VERSION 5.7 ;
  NOWIREEXTENSIONATPIN ON ;
  DIVIDERCHAR "/" ;
  BUSBITCHARS "[]" ;
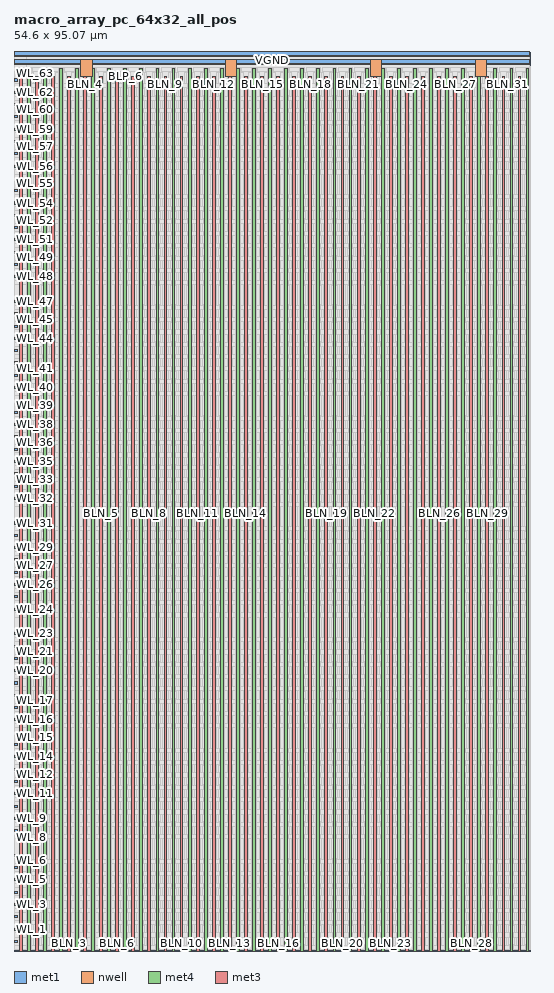
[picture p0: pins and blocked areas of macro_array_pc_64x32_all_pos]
MACRO macro_array_pc_64x32_all_pos
  CLASS BLOCK ;
  FOREIGN macro_array_pc_64x32_all_pos ;
  ORIGIN 0.000 0.000 ;
  SIZE 54.600 BY 95.070 ;
  PIN VPWR
    USE POWER ;
    PORT
      LAYER met1 ;
        RECT 0.000 93.750 54.500 94.150 ;
    END
    PORT
      LAYER nwell ;
        RECT 7.050 92.400 8.250 94.120 ;
    END
    PORT
      LAYER nwell ;
        RECT 22.350 92.400 23.550 94.120 ;
    END
    PORT
      LAYER nwell ;
        RECT 37.650 92.400 38.850 94.120 ;
    END
    PORT
      LAYER nwell ;
        RECT 48.700 92.400 49.900 94.120 ;
    END
    PORT
      LAYER met4 ;
        RECT 0.000 93.680 54.500 94.220 ;
    END
  END VPWR
  PIN VGND
    USE GROUND ;
    PORT
      LAYER met1 ;
        RECT 0.000 94.600 54.500 95.000 ;
    END
    PORT
      LAYER met4 ;
        RECT 0.000 94.530 54.500 95.070 ;
    END
  END VGND
  PIN BLP_0
    ANTENNADIFFAREA 253.343994 ;
    PORT
      LAYER met4 ;
        RECT 1.400 0.000 1.700 93.250 ;
    END
  END BLP_0
  PIN BLN_0
    PORT
      LAYER met3 ;
        RECT 0.550 0.000 0.850 92.400 ;
    END
  END BLN_0
  PIN BLP_1
    ANTENNADIFFAREA 253.222198 ;
    PORT
      LAYER met4 ;
        RECT 3.100 0.000 3.400 93.250 ;
    END
  END BLP_1
  PIN BLN_1
    PORT
      LAYER met3 ;
        RECT 2.250 0.000 2.550 92.400 ;
    END
  END BLN_1
  PIN BLP_2
    ANTENNADIFFAREA 253.100388 ;
    PORT
      LAYER met4 ;
        RECT 4.800 0.000 5.100 93.250 ;
    END
  END BLP_2
  PIN BLN_2
    PORT
      LAYER met3 ;
        RECT 3.950 0.000 4.250 92.400 ;
    END
  END BLN_2
  PIN BLP_3
    ANTENNADIFFAREA 252.978592 ;
    PORT
      LAYER met4 ;
        RECT 6.500 0.000 6.800 93.250 ;
    END
  END BLP_3
  PIN BLN_3
    PORT
      LAYER met3 ;
        RECT 5.650 0.000 5.950 92.400 ;
    END
  END BLN_3
  PIN BLP_4
    ANTENNADIFFAREA 252.856796 ;
    PORT
      LAYER met4 ;
        RECT 8.200 0.000 8.500 93.250 ;
    END
  END BLP_4
  PIN BLN_4
    PORT
      LAYER met3 ;
        RECT 7.350 0.000 7.650 92.400 ;
    END
  END BLN_4
  PIN BLP_5
    ANTENNADIFFAREA 252.735001 ;
    PORT
      LAYER met4 ;
        RECT 9.900 0.000 10.200 93.250 ;
    END
  END BLP_5
  PIN BLN_5
    PORT
      LAYER met3 ;
        RECT 9.050 0.000 9.350 92.400 ;
    END
  END BLN_5
  PIN BLP_6
    ANTENNADIFFAREA 252.613190 ;
    PORT
      LAYER met4 ;
        RECT 11.600 0.000 11.900 93.250 ;
    END
  END BLP_6
  PIN BLN_6
    PORT
      LAYER met3 ;
        RECT 10.750 0.000 11.050 92.400 ;
    END
  END BLN_6
  PIN BLP_7
    ANTENNADIFFAREA 252.491394 ;
    PORT
      LAYER met4 ;
        RECT 13.300 0.000 13.600 93.250 ;
    END
  END BLP_7
  PIN BLN_7
    PORT
      LAYER met3 ;
        RECT 12.450 0.000 12.750 92.400 ;
    END
  END BLN_7
  PIN BLP_8
    ANTENNADIFFAREA 252.369598 ;
    PORT
      LAYER met4 ;
        RECT 15.000 0.000 15.300 93.250 ;
    END
  END BLP_8
  PIN BLN_8
    PORT
      LAYER met3 ;
        RECT 14.150 0.000 14.450 92.400 ;
    END
  END BLN_8
  PIN BLP_9
    ANTENNADIFFAREA 252.247787 ;
    PORT
      LAYER met4 ;
        RECT 16.700 0.000 17.000 93.250 ;
    END
  END BLP_9
  PIN BLN_9
    PORT
      LAYER met3 ;
        RECT 15.850 0.000 16.150 92.400 ;
    END
  END BLN_9
  PIN BLP_10
    ANTENNADIFFAREA 252.125992 ;
    PORT
      LAYER met4 ;
        RECT 18.400 0.000 18.700 93.250 ;
    END
  END BLP_10
  PIN BLN_10
    PORT
      LAYER met3 ;
        RECT 17.550 0.000 17.850 92.400 ;
    END
  END BLN_10
  PIN BLP_11
    ANTENNADIFFAREA 252.004196 ;
    PORT
      LAYER met4 ;
        RECT 20.100 0.000 20.400 93.250 ;
    END
  END BLP_11
  PIN BLN_11
    PORT
      LAYER met3 ;
        RECT 19.250 0.000 19.550 92.400 ;
    END
  END BLN_11
  PIN BLP_12
    ANTENNADIFFAREA 251.882401 ;
    PORT
      LAYER met4 ;
        RECT 21.800 0.000 22.100 93.250 ;
    END
  END BLP_12
  PIN BLN_12
    PORT
      LAYER met3 ;
        RECT 20.950 0.000 21.250 92.400 ;
    END
  END BLN_12
  PIN BLP_13
    ANTENNADIFFAREA 251.760590 ;
    PORT
      LAYER met4 ;
        RECT 23.500 0.000 23.800 93.250 ;
    END
  END BLP_13
  PIN BLN_13
    PORT
      LAYER met3 ;
        RECT 22.650 0.000 22.950 92.400 ;
    END
  END BLN_13
  PIN BLP_14
    ANTENNADIFFAREA 251.638794 ;
    PORT
      LAYER met4 ;
        RECT 25.200 0.000 25.500 93.250 ;
    END
  END BLP_14
  PIN BLN_14
    PORT
      LAYER met3 ;
        RECT 24.350 0.000 24.650 92.400 ;
    END
  END BLN_14
  PIN BLP_15
    ANTENNADIFFAREA 251.516998 ;
    PORT
      LAYER met4 ;
        RECT 26.900 0.000 27.200 93.250 ;
    END
  END BLP_15
  PIN BLN_15
    PORT
      LAYER met3 ;
        RECT 26.050 0.000 26.350 92.400 ;
    END
  END BLN_15
  PIN BLP_16
    ANTENNADIFFAREA 251.395187 ;
    PORT
      LAYER met4 ;
        RECT 28.600 0.000 28.900 93.250 ;
    END
  END BLP_16
  PIN BLN_16
    PORT
      LAYER met3 ;
        RECT 27.750 0.000 28.050 92.400 ;
    END
  END BLN_16
  PIN BLP_17
    ANTENNADIFFAREA 251.273392 ;
    PORT
      LAYER met4 ;
        RECT 30.300 0.000 30.600 93.250 ;
    END
  END BLP_17
  PIN BLN_17
    PORT
      LAYER met3 ;
        RECT 29.450 0.000 29.750 92.400 ;
    END
  END BLN_17
  PIN BLP_18
    ANTENNADIFFAREA 251.151596 ;
    PORT
      LAYER met4 ;
        RECT 32.000 0.000 32.300 93.250 ;
    END
  END BLP_18
  PIN BLN_18
    PORT
      LAYER met3 ;
        RECT 31.150 0.000 31.450 92.400 ;
    END
  END BLN_18
  PIN BLP_19
    ANTENNADIFFAREA 251.029800 ;
    PORT
      LAYER met4 ;
        RECT 33.700 0.000 34.000 93.250 ;
    END
  END BLP_19
  PIN BLN_19
    PORT
      LAYER met3 ;
        RECT 32.850 0.000 33.150 92.400 ;
    END
  END BLN_19
  PIN BLP_20
    ANTENNADIFFAREA 250.907990 ;
    PORT
      LAYER met4 ;
        RECT 35.400 0.000 35.700 93.250 ;
    END
  END BLP_20
  PIN BLN_20
    PORT
      LAYER met3 ;
        RECT 34.550 0.000 34.850 92.400 ;
    END
  END BLN_20
  PIN BLP_21
    ANTENNADIFFAREA 250.786194 ;
    PORT
      LAYER met4 ;
        RECT 37.100 0.000 37.400 93.250 ;
    END
  END BLP_21
  PIN BLN_21
    PORT
      LAYER met3 ;
        RECT 36.250 0.000 36.550 92.400 ;
    END
  END BLN_21
  PIN BLP_22
    ANTENNADIFFAREA 250.664398 ;
    PORT
      LAYER met4 ;
        RECT 38.800 0.000 39.100 93.250 ;
    END
  END BLP_22
  PIN BLN_22
    PORT
      LAYER met3 ;
        RECT 37.950 0.000 38.250 92.400 ;
    END
  END BLN_22
  PIN BLP_23
    ANTENNADIFFAREA 250.542587 ;
    PORT
      LAYER met4 ;
        RECT 40.500 0.000 40.800 93.250 ;
    END
  END BLP_23
  PIN BLN_23
    PORT
      LAYER met3 ;
        RECT 39.650 0.000 39.950 92.400 ;
    END
  END BLN_23
  PIN BLP_24
    ANTENNADIFFAREA 250.420792 ;
    PORT
      LAYER met4 ;
        RECT 42.200 0.000 42.500 93.250 ;
    END
  END BLP_24
  PIN BLN_24
    PORT
      LAYER met3 ;
        RECT 41.350 0.000 41.650 92.400 ;
    END
  END BLN_24
  PIN BLP_25
    ANTENNADIFFAREA 250.298996 ;
    PORT
      LAYER met4 ;
        RECT 43.900 0.000 44.200 93.250 ;
    END
  END BLP_25
  PIN BLN_25
    PORT
      LAYER met3 ;
        RECT 43.050 0.000 43.350 92.400 ;
    END
  END BLN_25
  PIN BLP_26
    ANTENNADIFFAREA 250.177200 ;
    PORT
      LAYER met4 ;
        RECT 45.600 0.000 45.900 93.250 ;
    END
  END BLP_26
  PIN BLN_26
    PORT
      LAYER met3 ;
        RECT 44.750 0.000 45.050 92.400 ;
    END
  END BLN_26
  PIN BLP_27
    ANTENNADIFFAREA 250.055389 ;
    PORT
      LAYER met4 ;
        RECT 47.300 0.000 47.600 93.250 ;
    END
  END BLP_27
  PIN BLN_27
    PORT
      LAYER met3 ;
        RECT 46.450 0.000 46.750 92.400 ;
    END
  END BLN_27
  PIN BLP_28
    ANTENNADIFFAREA 249.933594 ;
    PORT
      LAYER met4 ;
        RECT 49.000 0.000 49.300 93.250 ;
    END
  END BLP_28
  PIN BLN_28
    PORT
      LAYER met3 ;
        RECT 48.150 0.000 48.450 92.400 ;
    END
  END BLN_28
  PIN BLP_29
    ANTENNADIFFAREA 249.811798 ;
    PORT
      LAYER met4 ;
        RECT 50.700 0.000 51.000 93.250 ;
    END
  END BLP_29
  PIN BLN_29
    PORT
      LAYER met3 ;
        RECT 49.850 0.000 50.150 92.400 ;
    END
  END BLN_29
  PIN BLP_30
    ANTENNADIFFAREA 249.689987 ;
    PORT
      LAYER met4 ;
        RECT 52.400 0.000 52.700 93.250 ;
    END
  END BLP_30
  PIN BLN_30
    PORT
      LAYER met3 ;
        RECT 51.550 0.000 51.850 92.400 ;
    END
  END BLN_30
  PIN BLP_31
    ANTENNADIFFAREA 249.568192 ;
    PORT
      LAYER met4 ;
        RECT 54.100 0.000 54.400 93.250 ;
    END
  END BLP_31
  PIN BLN_31
    PORT
      LAYER met3 ;
        RECT 53.250 0.000 53.550 92.400 ;
    END
  END BLN_31
  PIN WL_0
    ANTENNAGATEAREA 2.284800 ;
    PORT
      LAYER met1 ;
        RECT 0.000 0.900 0.390 1.120 ;
    END
  END WL_0
  PIN WL_1
    ANTENNAGATEAREA 2.284800 ;
    PORT
      LAYER met1 ;
        RECT 0.000 2.200 0.390 2.420 ;
    END
  END WL_1
  PIN WL_2
    ANTENNAGATEAREA 2.284800 ;
    PORT
      LAYER met1 ;
        RECT 0.000 3.500 0.390 3.720 ;
    END
  END WL_2
  PIN WL_3
    ANTENNAGATEAREA 2.284800 ;
    PORT
      LAYER met1 ;
        RECT 0.000 4.800 0.390 5.020 ;
    END
  END WL_3
  PIN WL_4
    ANTENNAGATEAREA 2.284800 ;
    PORT
      LAYER met1 ;
        RECT 0.000 6.100 0.390 6.320 ;
    END
  END WL_4
  PIN WL_5
    ANTENNAGATEAREA 2.284800 ;
    PORT
      LAYER met1 ;
        RECT 0.000 7.400 0.390 7.620 ;
    END
  END WL_5
  PIN WL_6
    ANTENNAGATEAREA 2.284800 ;
    PORT
      LAYER met1 ;
        RECT 0.000 8.700 0.390 8.920 ;
    END
  END WL_6
  PIN WL_7
    ANTENNAGATEAREA 2.284800 ;
    PORT
      LAYER met1 ;
        RECT 0.000 10.000 0.390 10.220 ;
    END
  END WL_7
  PIN WL_8
    ANTENNAGATEAREA 2.284800 ;
    PORT
      LAYER met1 ;
        RECT 0.000 12.600 0.390 12.820 ;
    END
  END WL_8
  PIN WL_9
    ANTENNAGATEAREA 2.284800 ;
    PORT
      LAYER met1 ;
        RECT 0.000 13.900 0.390 14.120 ;
    END
  END WL_9
  PIN WL_10
    ANTENNAGATEAREA 2.284800 ;
    PORT
      LAYER met1 ;
        RECT 0.000 15.200 0.390 15.420 ;
    END
  END WL_10
  PIN WL_11
    ANTENNAGATEAREA 2.284800 ;
    PORT
      LAYER met1 ;
        RECT 0.000 16.500 0.390 16.720 ;
    END
  END WL_11
  PIN WL_12
    ANTENNAGATEAREA 2.284800 ;
    PORT
      LAYER met1 ;
        RECT 0.000 17.800 0.390 18.020 ;
    END
  END WL_12
  PIN WL_13
    ANTENNAGATEAREA 2.284800 ;
    PORT
      LAYER met1 ;
        RECT 0.000 19.100 0.390 19.320 ;
    END
  END WL_13
  PIN WL_14
    ANTENNAGATEAREA 2.284800 ;
    PORT
      LAYER met1 ;
        RECT 0.000 20.400 0.390 20.620 ;
    END
  END WL_14
  PIN WL_15
    ANTENNAGATEAREA 2.284800 ;
    PORT
      LAYER met1 ;
        RECT 0.000 21.700 0.390 21.920 ;
    END
  END WL_15
  PIN WL_16
    ANTENNAGATEAREA 2.284800 ;
    PORT
      LAYER met1 ;
        RECT 0.000 24.300 0.390 24.520 ;
    END
  END WL_16
  PIN WL_17
    ANTENNAGATEAREA 2.284800 ;
    PORT
      LAYER met1 ;
        RECT 0.000 25.600 0.390 25.820 ;
    END
  END WL_17
  PIN WL_18
    ANTENNAGATEAREA 2.284800 ;
    PORT
      LAYER met1 ;
        RECT 0.000 26.900 0.390 27.120 ;
    END
  END WL_18
  PIN WL_19
    ANTENNAGATEAREA 2.284800 ;
    PORT
      LAYER met1 ;
        RECT 0.000 28.200 0.390 28.420 ;
    END
  END WL_19
  PIN WL_20
    ANTENNAGATEAREA 2.284800 ;
    PORT
      LAYER met1 ;
        RECT 0.000 29.500 0.390 29.720 ;
    END
  END WL_20
  PIN WL_21
    ANTENNAGATEAREA 2.284800 ;
    PORT
      LAYER met1 ;
        RECT 0.000 30.800 0.390 31.020 ;
    END
  END WL_21
  PIN WL_22
    ANTENNAGATEAREA 2.284800 ;
    PORT
      LAYER met1 ;
        RECT 0.000 32.100 0.390 32.320 ;
    END
  END WL_22
  PIN WL_23
    ANTENNAGATEAREA 2.284800 ;
    PORT
      LAYER met1 ;
        RECT 0.000 33.400 0.390 33.620 ;
    END
  END WL_23
  PIN WL_24
    ANTENNAGATEAREA 2.284800 ;
    PORT
      LAYER met1 ;
        RECT 0.000 36.000 0.390 36.220 ;
    END
  END WL_24
  PIN WL_25
    ANTENNAGATEAREA 2.284800 ;
    PORT
      LAYER met1 ;
        RECT 0.000 37.300 0.390 37.520 ;
    END
  END WL_25
  PIN WL_26
    ANTENNAGATEAREA 2.284800 ;
    PORT
      LAYER met1 ;
        RECT 0.000 38.600 0.390 38.820 ;
    END
  END WL_26
  PIN WL_27
    ANTENNAGATEAREA 2.284800 ;
    PORT
      LAYER met1 ;
        RECT 0.000 39.900 0.390 40.120 ;
    END
  END WL_27
  PIN WL_28
    ANTENNAGATEAREA 2.284800 ;
    PORT
      LAYER met1 ;
        RECT 0.000 41.200 0.390 41.420 ;
    END
  END WL_28
  PIN WL_29
    ANTENNAGATEAREA 2.284800 ;
    PORT
      LAYER met1 ;
        RECT 0.000 42.500 0.390 42.720 ;
    END
  END WL_29
  PIN WL_30
    ANTENNAGATEAREA 2.284800 ;
    PORT
      LAYER met1 ;
        RECT 0.000 43.800 0.390 44.020 ;
    END
  END WL_30
  PIN WL_31
    ANTENNAGATEAREA 2.284800 ;
    PORT
      LAYER met1 ;
        RECT 0.000 45.100 0.390 45.320 ;
    END
  END WL_31
  PIN WL_32
    ANTENNAGATEAREA 2.284800 ;
    PORT
      LAYER met1 ;
        RECT 0.000 47.700 0.390 47.920 ;
    END
  END WL_32
  PIN WL_33
    ANTENNAGATEAREA 2.284800 ;
    PORT
      LAYER met1 ;
        RECT 0.000 49.000 0.390 49.220 ;
    END
  END WL_33
  PIN WL_34
    ANTENNAGATEAREA 2.284800 ;
    PORT
      LAYER met1 ;
        RECT 0.000 50.300 0.390 50.520 ;
    END
  END WL_34
  PIN WL_35
    ANTENNAGATEAREA 2.284800 ;
    PORT
      LAYER met1 ;
        RECT 0.000 51.600 0.390 51.820 ;
    END
  END WL_35
  PIN WL_36
    ANTENNAGATEAREA 2.284800 ;
    PORT
      LAYER met1 ;
        RECT 0.000 52.900 0.390 53.120 ;
    END
  END WL_36
  PIN WL_37
    ANTENNAGATEAREA 2.284800 ;
    PORT
      LAYER met1 ;
        RECT 0.000 54.200 0.390 54.420 ;
    END
  END WL_37
  PIN WL_38
    ANTENNAGATEAREA 2.284800 ;
    PORT
      LAYER met1 ;
        RECT 0.000 55.500 0.390 55.720 ;
    END
  END WL_38
  PIN WL_39
    ANTENNAGATEAREA 2.284800 ;
    PORT
      LAYER met1 ;
        RECT 0.000 56.800 0.390 57.020 ;
    END
  END WL_39
  PIN WL_40
    ANTENNAGATEAREA 2.284800 ;
    PORT
      LAYER met1 ;
        RECT 0.000 59.400 0.390 59.620 ;
    END
  END WL_40
  PIN WL_41
    ANTENNAGATEAREA 2.284800 ;
    PORT
      LAYER met1 ;
        RECT 0.000 60.700 0.390 60.920 ;
    END
  END WL_41
  PIN WL_42
    ANTENNAGATEAREA 2.284800 ;
    PORT
      LAYER met1 ;
        RECT 0.000 62.000 0.390 62.220 ;
    END
  END WL_42
  PIN WL_43
    ANTENNAGATEAREA 2.284800 ;
    PORT
      LAYER met1 ;
        RECT 0.000 63.300 0.390 63.520 ;
    END
  END WL_43
  PIN WL_44
    ANTENNAGATEAREA 2.284800 ;
    PORT
      LAYER met1 ;
        RECT 0.000 64.600 0.390 64.820 ;
    END
  END WL_44
  PIN WL_45
    ANTENNAGATEAREA 2.284800 ;
    PORT
      LAYER met1 ;
        RECT 0.000 65.900 0.390 66.120 ;
    END
  END WL_45
  PIN WL_46
    ANTENNAGATEAREA 2.284800 ;
    PORT
      LAYER met1 ;
        RECT 0.000 67.200 0.390 67.420 ;
    END
  END WL_46
  PIN WL_47
    ANTENNAGATEAREA 2.284800 ;
    PORT
      LAYER met1 ;
        RECT 0.000 68.500 0.390 68.720 ;
    END
  END WL_47
  PIN WL_48
    ANTENNAGATEAREA 2.284800 ;
    PORT
      LAYER met1 ;
        RECT 0.000 71.100 0.390 71.320 ;
    END
  END WL_48
  PIN WL_49
    ANTENNAGATEAREA 2.284800 ;
    PORT
      LAYER met1 ;
        RECT 0.000 72.400 0.390 72.620 ;
    END
  END WL_49
  PIN WL_50
    ANTENNAGATEAREA 2.284800 ;
    PORT
      LAYER met1 ;
        RECT 0.000 73.700 0.390 73.920 ;
    END
  END WL_50
  PIN WL_51
    ANTENNAGATEAREA 2.284800 ;
    PORT
      LAYER met1 ;
        RECT 0.000 75.000 0.390 75.220 ;
    END
  END WL_51
  PIN WL_52
    ANTENNAGATEAREA 2.284800 ;
    PORT
      LAYER met1 ;
        RECT 0.000 76.300 0.390 76.520 ;
    END
  END WL_52
  PIN WL_53
    ANTENNAGATEAREA 2.284800 ;
    PORT
      LAYER met1 ;
        RECT 0.000 77.600 0.390 77.820 ;
    END
  END WL_53
  PIN WL_54
    ANTENNAGATEAREA 2.284800 ;
    PORT
      LAYER met1 ;
        RECT 0.000 78.900 0.390 79.120 ;
    END
  END WL_54
  PIN WL_55
    ANTENNAGATEAREA 2.284800 ;
    PORT
      LAYER met1 ;
        RECT 0.000 80.200 0.390 80.420 ;
    END
  END WL_55
  PIN WL_56
    ANTENNAGATEAREA 2.284800 ;
    PORT
      LAYER met1 ;
        RECT 0.000 82.800 0.390 83.020 ;
    END
  END WL_56
  PIN WL_57
    ANTENNAGATEAREA 2.284800 ;
    PORT
      LAYER met1 ;
        RECT 0.000 84.100 0.390 84.320 ;
    END
  END WL_57
  PIN WL_58
    ANTENNAGATEAREA 2.284800 ;
    PORT
      LAYER met1 ;
        RECT 0.000 85.400 0.390 85.620 ;
    END
  END WL_58
  PIN WL_59
    ANTENNAGATEAREA 2.284800 ;
    PORT
      LAYER met1 ;
        RECT 0.000 86.700 0.390 86.920 ;
    END
  END WL_59
  PIN WL_60
    ANTENNAGATEAREA 2.284800 ;
    PORT
      LAYER met1 ;
        RECT 0.000 88.000 0.390 88.220 ;
    END
  END WL_60
  PIN WL_61
    ANTENNAGATEAREA 2.284800 ;
    PORT
      LAYER met1 ;
        RECT 0.000 89.300 0.390 89.520 ;
    END
  END WL_61
  PIN WL_62
    ANTENNAGATEAREA 2.284800 ;
    PORT
      LAYER met1 ;
        RECT 0.000 90.600 0.390 90.820 ;
    END
  END WL_62
  PIN WL_63
    ANTENNAGATEAREA 2.284800 ;
    PORT
      LAYER met1 ;
        RECT 0.000 91.900 0.390 92.120 ;
    END
  END WL_63
  OBS
      LAYER nwell ;
        RECT 0.100 92.400 5.780 93.550 ;
        RECT 9.520 92.400 21.080 93.550 ;
        RECT 24.820 92.400 36.380 93.550 ;
        RECT 40.120 92.400 47.430 93.550 ;
        RECT 51.170 92.400 54.040 93.550 ;
      LAYER li1 ;
        RECT 0.140 0.160 53.750 93.845 ;
      LAYER met1 ;
        RECT 0.080 92.400 54.600 93.470 ;
        RECT 0.670 91.620 54.600 92.400 ;
        RECT 0.080 91.100 54.600 91.620 ;
        RECT 0.670 90.320 54.600 91.100 ;
        RECT 0.080 89.800 54.600 90.320 ;
        RECT 0.670 89.020 54.600 89.800 ;
        RECT 0.080 88.500 54.600 89.020 ;
        RECT 0.670 87.720 54.600 88.500 ;
        RECT 0.080 87.200 54.600 87.720 ;
        RECT 0.670 86.420 54.600 87.200 ;
        RECT 0.080 85.900 54.600 86.420 ;
        RECT 0.670 85.120 54.600 85.900 ;
        RECT 0.080 84.600 54.600 85.120 ;
        RECT 0.670 83.820 54.600 84.600 ;
        RECT 0.080 83.300 54.600 83.820 ;
        RECT 0.670 82.520 54.600 83.300 ;
        RECT 0.080 80.700 54.600 82.520 ;
        RECT 0.670 79.920 54.600 80.700 ;
        RECT 0.080 79.400 54.600 79.920 ;
        RECT 0.670 78.620 54.600 79.400 ;
        RECT 0.080 78.100 54.600 78.620 ;
        RECT 0.670 77.320 54.600 78.100 ;
        RECT 0.080 76.800 54.600 77.320 ;
        RECT 0.670 76.020 54.600 76.800 ;
        RECT 0.080 75.500 54.600 76.020 ;
        RECT 0.670 74.720 54.600 75.500 ;
        RECT 0.080 74.200 54.600 74.720 ;
        RECT 0.670 73.420 54.600 74.200 ;
        RECT 0.080 72.900 54.600 73.420 ;
        RECT 0.670 72.120 54.600 72.900 ;
        RECT 0.080 71.600 54.600 72.120 ;
        RECT 0.670 70.820 54.600 71.600 ;
        RECT 0.080 69.000 54.600 70.820 ;
        RECT 0.670 68.220 54.600 69.000 ;
        RECT 0.080 67.700 54.600 68.220 ;
        RECT 0.670 66.920 54.600 67.700 ;
        RECT 0.080 66.400 54.600 66.920 ;
        RECT 0.670 65.620 54.600 66.400 ;
        RECT 0.080 65.100 54.600 65.620 ;
        RECT 0.670 64.320 54.600 65.100 ;
        RECT 0.080 63.800 54.600 64.320 ;
        RECT 0.670 63.020 54.600 63.800 ;
        RECT 0.080 62.500 54.600 63.020 ;
        RECT 0.670 61.720 54.600 62.500 ;
        RECT 0.080 61.200 54.600 61.720 ;
        RECT 0.670 60.420 54.600 61.200 ;
        RECT 0.080 59.900 54.600 60.420 ;
        RECT 0.670 59.120 54.600 59.900 ;
        RECT 0.080 57.300 54.600 59.120 ;
        RECT 0.670 56.520 54.600 57.300 ;
        RECT 0.080 56.000 54.600 56.520 ;
        RECT 0.670 55.220 54.600 56.000 ;
        RECT 0.080 54.700 54.600 55.220 ;
        RECT 0.670 53.920 54.600 54.700 ;
        RECT 0.080 53.400 54.600 53.920 ;
        RECT 0.670 52.620 54.600 53.400 ;
        RECT 0.080 52.100 54.600 52.620 ;
        RECT 0.670 51.320 54.600 52.100 ;
        RECT 0.080 50.800 54.600 51.320 ;
        RECT 0.670 50.020 54.600 50.800 ;
        RECT 0.080 49.500 54.600 50.020 ;
        RECT 0.670 48.720 54.600 49.500 ;
        RECT 0.080 48.200 54.600 48.720 ;
        RECT 0.670 47.420 54.600 48.200 ;
        RECT 0.080 45.600 54.600 47.420 ;
        RECT 0.670 44.820 54.600 45.600 ;
        RECT 0.080 44.300 54.600 44.820 ;
        RECT 0.670 43.520 54.600 44.300 ;
        RECT 0.080 43.000 54.600 43.520 ;
        RECT 0.670 42.220 54.600 43.000 ;
        RECT 0.080 41.700 54.600 42.220 ;
        RECT 0.670 40.920 54.600 41.700 ;
        RECT 0.080 40.400 54.600 40.920 ;
        RECT 0.670 39.620 54.600 40.400 ;
        RECT 0.080 39.100 54.600 39.620 ;
        RECT 0.670 38.320 54.600 39.100 ;
        RECT 0.080 37.800 54.600 38.320 ;
        RECT 0.670 37.020 54.600 37.800 ;
        RECT 0.080 36.500 54.600 37.020 ;
        RECT 0.670 35.720 54.600 36.500 ;
        RECT 0.080 33.900 54.600 35.720 ;
        RECT 0.670 33.120 54.600 33.900 ;
        RECT 0.080 32.600 54.600 33.120 ;
        RECT 0.670 31.820 54.600 32.600 ;
        RECT 0.080 31.300 54.600 31.820 ;
        RECT 0.670 30.520 54.600 31.300 ;
        RECT 0.080 30.000 54.600 30.520 ;
        RECT 0.670 29.220 54.600 30.000 ;
        RECT 0.080 28.700 54.600 29.220 ;
        RECT 0.670 27.920 54.600 28.700 ;
        RECT 0.080 27.400 54.600 27.920 ;
        RECT 0.670 26.620 54.600 27.400 ;
        RECT 0.080 26.100 54.600 26.620 ;
        RECT 0.670 25.320 54.600 26.100 ;
        RECT 0.080 24.800 54.600 25.320 ;
        RECT 0.670 24.020 54.600 24.800 ;
        RECT 0.080 22.200 54.600 24.020 ;
        RECT 0.670 21.420 54.600 22.200 ;
        RECT 0.080 20.900 54.600 21.420 ;
        RECT 0.670 20.120 54.600 20.900 ;
        RECT 0.080 19.600 54.600 20.120 ;
        RECT 0.670 18.820 54.600 19.600 ;
        RECT 0.080 18.300 54.600 18.820 ;
        RECT 0.670 17.520 54.600 18.300 ;
        RECT 0.080 17.000 54.600 17.520 ;
        RECT 0.670 16.220 54.600 17.000 ;
        RECT 0.080 15.700 54.600 16.220 ;
        RECT 0.670 14.920 54.600 15.700 ;
        RECT 0.080 14.400 54.600 14.920 ;
        RECT 0.670 13.620 54.600 14.400 ;
        RECT 0.080 13.100 54.600 13.620 ;
        RECT 0.670 12.320 54.600 13.100 ;
        RECT 0.080 10.500 54.600 12.320 ;
        RECT 0.670 9.720 54.600 10.500 ;
        RECT 0.080 9.200 54.600 9.720 ;
        RECT 0.670 8.420 54.600 9.200 ;
        RECT 0.080 7.900 54.600 8.420 ;
        RECT 0.670 7.120 54.600 7.900 ;
        RECT 0.080 6.600 54.600 7.120 ;
        RECT 0.670 5.820 54.600 6.600 ;
        RECT 0.080 5.300 54.600 5.820 ;
        RECT 0.670 4.520 54.600 5.300 ;
        RECT 0.080 4.000 54.600 4.520 ;
        RECT 0.670 3.220 54.600 4.000 ;
        RECT 0.080 2.700 54.600 3.220 ;
        RECT 0.670 1.920 54.600 2.700 ;
        RECT 0.080 1.400 54.600 1.920 ;
        RECT 0.670 0.620 54.600 1.400 ;
        RECT 0.080 0.170 54.600 0.620 ;
      LAYER met2 ;
        RECT 0.080 0.170 54.500 95.060 ;
      LAYER met3 ;
        RECT 1.300 92.800 54.500 95.070 ;
        RECT 1.300 0.140 1.850 92.800 ;
        RECT 2.950 0.140 3.550 92.800 ;
        RECT 4.650 0.140 5.250 92.800 ;
        RECT 6.350 0.140 6.950 92.800 ;
        RECT 8.050 0.140 8.650 92.800 ;
        RECT 9.750 0.140 10.350 92.800 ;
        RECT 11.450 0.140 12.050 92.800 ;
        RECT 13.150 0.140 13.750 92.800 ;
        RECT 14.850 0.140 15.450 92.800 ;
        RECT 16.550 0.140 17.150 92.800 ;
        RECT 18.250 0.140 18.850 92.800 ;
        RECT 19.950 0.140 20.550 92.800 ;
        RECT 21.650 0.140 22.250 92.800 ;
        RECT 23.350 0.140 23.950 92.800 ;
        RECT 25.050 0.140 25.650 92.800 ;
        RECT 26.750 0.140 27.350 92.800 ;
        RECT 28.450 0.140 29.050 92.800 ;
        RECT 30.150 0.140 30.750 92.800 ;
        RECT 31.850 0.140 32.450 92.800 ;
        RECT 33.550 0.140 34.150 92.800 ;
        RECT 35.250 0.140 35.850 92.800 ;
        RECT 36.950 0.140 37.550 92.800 ;
        RECT 38.650 0.140 39.250 92.800 ;
        RECT 40.350 0.140 40.950 92.800 ;
        RECT 42.050 0.140 42.650 92.800 ;
        RECT 43.750 0.140 44.350 92.800 ;
        RECT 45.450 0.140 46.050 92.800 ;
        RECT 47.150 0.140 47.750 92.800 ;
        RECT 48.850 0.140 49.450 92.800 ;
        RECT 50.550 0.140 51.150 92.800 ;
        RECT 52.250 0.140 52.850 92.800 ;
        RECT 53.950 0.140 54.500 92.800 ;
      LAYER met4 ;
        RECT 2.100 0.140 2.700 93.280 ;
        RECT 3.800 0.140 4.400 93.280 ;
        RECT 5.500 0.140 6.100 93.280 ;
        RECT 7.200 0.140 7.800 93.280 ;
        RECT 8.900 0.140 9.500 93.280 ;
        RECT 10.600 0.140 11.200 93.280 ;
        RECT 12.300 0.140 12.900 93.280 ;
        RECT 14.000 0.140 14.600 93.280 ;
        RECT 15.700 0.140 16.300 93.280 ;
        RECT 17.400 0.140 18.000 93.280 ;
        RECT 19.100 0.140 19.700 93.280 ;
        RECT 20.800 0.140 21.400 93.280 ;
        RECT 22.500 0.140 23.100 93.280 ;
        RECT 24.200 0.140 24.800 93.280 ;
        RECT 25.900 0.140 26.500 93.280 ;
        RECT 27.600 0.140 28.200 93.280 ;
        RECT 29.300 0.140 29.900 93.280 ;
        RECT 31.000 0.140 31.600 93.280 ;
        RECT 32.700 0.140 33.300 93.280 ;
        RECT 34.400 0.140 35.000 93.280 ;
        RECT 36.100 0.140 36.700 93.280 ;
        RECT 37.800 0.140 38.400 93.280 ;
        RECT 39.500 0.140 40.100 93.280 ;
        RECT 41.200 0.140 41.800 93.280 ;
        RECT 42.900 0.140 43.500 93.280 ;
        RECT 44.600 0.140 45.200 93.280 ;
        RECT 46.300 0.140 46.900 93.280 ;
        RECT 48.000 0.140 48.600 93.280 ;
        RECT 49.700 0.140 50.300 93.280 ;
        RECT 51.400 0.140 52.000 93.280 ;
        RECT 53.100 0.140 53.700 93.280 ;
      LAYER met2 ;
        RECT 0.080 0.170 54.500 0.610 ;
        RECT 0.080 1.470 54.500 1.910 ;
        RECT 0.080 2.770 54.500 3.210 ;
        RECT 0.080 4.070 54.500 4.510 ;
        RECT 0.080 5.370 54.500 5.810 ;
        RECT 0.080 6.670 54.500 7.110 ;
        RECT 0.080 7.970 54.500 8.410 ;
        RECT 0.080 9.270 54.500 9.710 ;
        RECT 0.080 11.870 54.500 12.310 ;
        RECT 0.080 13.170 54.500 13.610 ;
        RECT 0.080 14.470 54.500 14.910 ;
        RECT 0.080 15.770 54.500 16.210 ;
        RECT 0.080 17.070 54.500 17.510 ;
        RECT 0.080 18.370 54.500 18.810 ;
        RECT 0.080 19.670 54.500 20.110 ;
        RECT 0.080 20.970 54.500 21.410 ;
        RECT 0.080 23.570 54.500 24.010 ;
        RECT 0.080 24.870 54.500 25.310 ;
        RECT 0.080 26.170 54.500 26.610 ;
        RECT 0.080 27.470 54.500 27.910 ;
        RECT 0.080 28.770 54.500 29.210 ;
        RECT 0.080 30.070 54.500 30.510 ;
        RECT 0.080 31.370 54.500 31.810 ;
        RECT 0.080 32.670 54.500 33.110 ;
        RECT 0.080 35.270 54.500 35.710 ;
        RECT 0.080 36.570 54.500 37.010 ;
        RECT 0.080 37.870 54.500 38.310 ;
        RECT 0.080 39.170 54.500 39.610 ;
        RECT 0.080 40.470 54.500 40.910 ;
        RECT 0.080 41.770 54.500 42.210 ;
        RECT 0.080 43.070 54.500 43.510 ;
        RECT 0.080 44.370 54.500 44.810 ;
        RECT 0.080 46.970 54.500 47.410 ;
        RECT 0.080 48.270 54.500 48.710 ;
        RECT 0.080 49.570 54.500 50.010 ;
        RECT 0.080 50.870 54.500 51.310 ;
        RECT 0.080 52.170 54.500 52.610 ;
        RECT 0.080 53.470 54.500 53.910 ;
        RECT 0.080 54.770 54.500 55.210 ;
        RECT 0.080 56.070 54.500 56.510 ;
        RECT 0.080 58.670 54.500 59.110 ;
        RECT 0.080 59.970 54.500 60.410 ;
        RECT 0.080 61.270 54.500 61.710 ;
        RECT 0.080 62.570 54.500 63.010 ;
        RECT 0.080 63.870 54.500 64.310 ;
        RECT 0.080 65.170 54.500 65.610 ;
        RECT 0.080 66.470 54.500 66.910 ;
        RECT 0.080 67.770 54.500 68.210 ;
        RECT 0.080 70.370 54.500 70.810 ;
        RECT 0.080 71.670 54.500 72.110 ;
        RECT 0.080 72.970 54.500 73.410 ;
        RECT 0.080 74.270 54.500 74.710 ;
        RECT 0.080 75.570 54.500 76.010 ;
        RECT 0.080 76.870 54.500 77.310 ;
        RECT 0.080 78.170 54.500 78.610 ;
        RECT 0.080 79.470 54.500 79.910 ;
        RECT 0.080 82.070 54.500 82.510 ;
        RECT 0.080 83.370 54.500 83.810 ;
        RECT 0.080 84.670 54.500 85.110 ;
        RECT 0.080 85.970 54.500 86.410 ;
        RECT 0.080 87.270 54.500 87.710 ;
        RECT 0.080 88.570 54.500 89.010 ;
        RECT 0.080 89.870 54.500 90.310 ;
        RECT 0.080 91.170 54.500 91.610 ;
        RECT 0.245 92.870 1.800 93.340 ;
        RECT 1.945 92.870 3.500 93.340 ;
        RECT 3.645 92.870 5.200 93.340 ;
        RECT 5.345 92.870 6.900 93.340 ;
        RECT 7.045 92.870 8.600 93.340 ;
        RECT 8.745 92.870 10.300 93.340 ;
        RECT 10.445 92.870 12.000 93.340 ;
        RECT 12.145 92.870 13.700 93.340 ;
        RECT 13.845 92.870 15.400 93.340 ;
        RECT 15.545 92.870 17.100 93.340 ;
        RECT 17.245 92.870 18.800 93.340 ;
        RECT 18.945 92.870 20.500 93.340 ;
        RECT 20.645 92.870 22.200 93.340 ;
        RECT 22.345 92.870 23.900 93.340 ;
        RECT 24.045 92.870 25.600 93.340 ;
        RECT 25.745 92.870 27.300 93.340 ;
        RECT 27.445 92.870 29.000 93.340 ;
        RECT 29.145 92.870 30.700 93.340 ;
        RECT 30.845 92.870 32.400 93.340 ;
        RECT 32.545 92.870 34.100 93.340 ;
        RECT 34.245 92.870 35.800 93.340 ;
        RECT 35.945 92.870 37.500 93.340 ;
        RECT 37.645 92.870 39.200 93.340 ;
        RECT 39.345 92.870 40.900 93.340 ;
        RECT 41.045 92.870 42.600 93.340 ;
        RECT 42.745 92.870 44.300 93.340 ;
        RECT 44.445 92.870 46.000 93.340 ;
        RECT 46.145 92.870 47.700 93.340 ;
        RECT 47.845 92.870 49.400 93.340 ;
        RECT 49.545 92.870 51.100 93.340 ;
        RECT 51.245 92.870 52.800 93.340 ;
        RECT 52.945 92.870 54.500 93.340 ;
        RECT 7.940 93.690 8.460 94.210 ;
        RECT 29.940 94.540 30.460 95.060 ;
      LAYER met3 ;
        RECT 48.900 83.340 49.400 83.840 ;
        RECT 50.600 83.340 51.100 83.840 ;
        RECT 52.300 83.340 52.800 83.840 ;
        RECT 54.000 83.340 54.500 83.840 ;
        RECT 48.900 84.640 49.400 85.140 ;
        RECT 50.600 84.640 51.100 85.140 ;
        RECT 52.300 84.640 52.800 85.140 ;
        RECT 54.000 84.640 54.500 85.140 ;
        RECT 48.900 85.940 49.400 86.440 ;
        RECT 50.600 85.940 51.100 86.440 ;
        RECT 52.300 85.940 52.800 86.440 ;
        RECT 54.000 85.940 54.500 86.440 ;
        RECT 48.900 87.240 49.400 87.740 ;
        RECT 50.600 87.240 51.100 87.740 ;
        RECT 52.300 87.240 52.800 87.740 ;
        RECT 54.000 87.240 54.500 87.740 ;
        RECT 48.900 88.540 49.400 89.040 ;
        RECT 50.600 88.540 51.100 89.040 ;
        RECT 52.300 88.540 52.800 89.040 ;
        RECT 54.000 88.540 54.500 89.040 ;
        RECT 48.900 89.840 49.400 90.340 ;
        RECT 50.600 89.840 51.100 90.340 ;
        RECT 52.300 89.840 52.800 90.340 ;
        RECT 54.000 89.840 54.500 90.340 ;
        RECT 48.900 91.140 49.400 91.640 ;
        RECT 50.600 91.140 51.100 91.640 ;
        RECT 52.300 91.140 52.800 91.640 ;
        RECT 54.000 91.140 54.500 91.640 ;
        RECT 48.900 92.820 49.400 93.320 ;
        RECT 50.600 92.820 51.100 93.320 ;
        RECT 52.300 92.820 52.800 93.320 ;
        RECT 54.000 92.820 54.500 93.320 ;
        RECT 42.100 88.540 42.600 89.040 ;
        RECT 43.800 88.540 44.300 89.040 ;
        RECT 45.500 88.540 46.000 89.040 ;
        RECT 47.200 88.540 47.700 89.040 ;
        RECT 42.100 85.940 42.600 86.440 ;
        RECT 43.800 85.940 44.300 86.440 ;
        RECT 45.500 85.940 46.000 86.440 ;
        RECT 47.200 85.940 47.700 86.440 ;
        RECT 42.100 89.840 42.600 90.340 ;
        RECT 43.800 89.840 44.300 90.340 ;
        RECT 45.500 89.840 46.000 90.340 ;
        RECT 47.200 89.840 47.700 90.340 ;
        RECT 42.100 84.640 42.600 85.140 ;
        RECT 43.800 84.640 44.300 85.140 ;
        RECT 45.500 84.640 46.000 85.140 ;
        RECT 47.200 84.640 47.700 85.140 ;
        RECT 42.100 91.140 42.600 91.640 ;
        RECT 43.800 91.140 44.300 91.640 ;
        RECT 45.500 91.140 46.000 91.640 ;
        RECT 47.200 91.140 47.700 91.640 ;
        RECT 42.100 87.240 42.600 87.740 ;
        RECT 43.800 87.240 44.300 87.740 ;
        RECT 45.500 87.240 46.000 87.740 ;
        RECT 47.200 87.240 47.700 87.740 ;
        RECT 42.100 92.820 42.600 93.320 ;
        RECT 43.800 92.820 44.300 93.320 ;
        RECT 45.500 92.820 46.000 93.320 ;
        RECT 47.200 92.820 47.700 93.320 ;
        RECT 42.100 83.340 42.600 83.840 ;
        RECT 43.800 83.340 44.300 83.840 ;
        RECT 45.500 83.340 46.000 83.840 ;
        RECT 47.200 83.340 47.700 83.840 ;
        RECT 42.100 71.640 42.600 72.140 ;
        RECT 43.800 71.640 44.300 72.140 ;
        RECT 45.500 71.640 46.000 72.140 ;
        RECT 47.200 71.640 47.700 72.140 ;
        RECT 42.100 72.940 42.600 73.440 ;
        RECT 43.800 72.940 44.300 73.440 ;
        RECT 45.500 72.940 46.000 73.440 ;
        RECT 47.200 72.940 47.700 73.440 ;
        RECT 42.100 74.240 42.600 74.740 ;
        RECT 43.800 74.240 44.300 74.740 ;
        RECT 45.500 74.240 46.000 74.740 ;
        RECT 47.200 74.240 47.700 74.740 ;
        RECT 42.100 75.540 42.600 76.040 ;
        RECT 43.800 75.540 44.300 76.040 ;
        RECT 45.500 75.540 46.000 76.040 ;
        RECT 47.200 75.540 47.700 76.040 ;
        RECT 42.100 76.840 42.600 77.340 ;
        RECT 43.800 76.840 44.300 77.340 ;
        RECT 45.500 76.840 46.000 77.340 ;
        RECT 47.200 76.840 47.700 77.340 ;
        RECT 42.100 78.140 42.600 78.640 ;
        RECT 43.800 78.140 44.300 78.640 ;
        RECT 45.500 78.140 46.000 78.640 ;
        RECT 47.200 78.140 47.700 78.640 ;
        RECT 42.100 79.440 42.600 79.940 ;
        RECT 43.800 79.440 44.300 79.940 ;
        RECT 45.500 79.440 46.000 79.940 ;
        RECT 47.200 79.440 47.700 79.940 ;
        RECT 42.100 82.040 42.600 82.540 ;
        RECT 43.800 82.040 44.300 82.540 ;
        RECT 45.500 82.040 46.000 82.540 ;
        RECT 47.200 82.040 47.700 82.540 ;
        RECT 48.900 71.640 49.400 72.140 ;
        RECT 50.600 71.640 51.100 72.140 ;
        RECT 52.300 71.640 52.800 72.140 ;
        RECT 54.000 71.640 54.500 72.140 ;
        RECT 48.900 76.840 49.400 77.340 ;
        RECT 50.600 76.840 51.100 77.340 ;
        RECT 52.300 76.840 52.800 77.340 ;
        RECT 54.000 76.840 54.500 77.340 ;
        RECT 48.900 74.240 49.400 74.740 ;
        RECT 50.600 74.240 51.100 74.740 ;
        RECT 52.300 74.240 52.800 74.740 ;
        RECT 54.000 74.240 54.500 74.740 ;
        RECT 48.900 78.140 49.400 78.640 ;
        RECT 50.600 78.140 51.100 78.640 ;
        RECT 52.300 78.140 52.800 78.640 ;
        RECT 54.000 78.140 54.500 78.640 ;
        RECT 48.900 72.940 49.400 73.440 ;
        RECT 50.600 72.940 51.100 73.440 ;
        RECT 52.300 72.940 52.800 73.440 ;
        RECT 54.000 72.940 54.500 73.440 ;
        RECT 48.900 79.440 49.400 79.940 ;
        RECT 50.600 79.440 51.100 79.940 ;
        RECT 52.300 79.440 52.800 79.940 ;
        RECT 54.000 79.440 54.500 79.940 ;
        RECT 48.900 75.540 49.400 76.040 ;
        RECT 50.600 75.540 51.100 76.040 ;
        RECT 52.300 75.540 52.800 76.040 ;
        RECT 54.000 75.540 54.500 76.040 ;
        RECT 48.900 82.040 49.400 82.540 ;
        RECT 50.600 82.040 51.100 82.540 ;
        RECT 52.300 82.040 52.800 82.540 ;
        RECT 54.000 82.040 54.500 82.540 ;
        RECT 35.300 83.340 35.800 83.840 ;
        RECT 37.000 83.340 37.500 83.840 ;
        RECT 38.700 83.340 39.200 83.840 ;
        RECT 40.400 83.340 40.900 83.840 ;
        RECT 35.300 84.640 35.800 85.140 ;
        RECT 37.000 84.640 37.500 85.140 ;
        RECT 38.700 84.640 39.200 85.140 ;
        RECT 40.400 84.640 40.900 85.140 ;
        RECT 35.300 85.940 35.800 86.440 ;
        RECT 37.000 85.940 37.500 86.440 ;
        RECT 38.700 85.940 39.200 86.440 ;
        RECT 40.400 85.940 40.900 86.440 ;
        RECT 35.300 87.240 35.800 87.740 ;
        RECT 37.000 87.240 37.500 87.740 ;
        RECT 38.700 87.240 39.200 87.740 ;
        RECT 40.400 87.240 40.900 87.740 ;
        RECT 35.300 88.540 35.800 89.040 ;
        RECT 37.000 88.540 37.500 89.040 ;
        RECT 38.700 88.540 39.200 89.040 ;
        RECT 40.400 88.540 40.900 89.040 ;
        RECT 35.300 89.840 35.800 90.340 ;
        RECT 37.000 89.840 37.500 90.340 ;
        RECT 38.700 89.840 39.200 90.340 ;
        RECT 40.400 89.840 40.900 90.340 ;
        RECT 35.300 91.140 35.800 91.640 ;
        RECT 37.000 91.140 37.500 91.640 ;
        RECT 38.700 91.140 39.200 91.640 ;
        RECT 40.400 91.140 40.900 91.640 ;
        RECT 35.300 92.820 35.800 93.320 ;
        RECT 37.000 92.820 37.500 93.320 ;
        RECT 38.700 92.820 39.200 93.320 ;
        RECT 40.400 92.820 40.900 93.320 ;
        RECT 28.500 88.540 29.000 89.040 ;
        RECT 30.200 88.540 30.700 89.040 ;
        RECT 31.900 88.540 32.400 89.040 ;
        RECT 33.600 88.540 34.100 89.040 ;
        RECT 28.500 85.940 29.000 86.440 ;
        RECT 30.200 85.940 30.700 86.440 ;
        RECT 31.900 85.940 32.400 86.440 ;
        RECT 33.600 85.940 34.100 86.440 ;
        RECT 28.500 89.840 29.000 90.340 ;
        RECT 30.200 89.840 30.700 90.340 ;
        RECT 31.900 89.840 32.400 90.340 ;
        RECT 33.600 89.840 34.100 90.340 ;
        RECT 28.500 84.640 29.000 85.140 ;
        RECT 30.200 84.640 30.700 85.140 ;
        RECT 31.900 84.640 32.400 85.140 ;
        RECT 33.600 84.640 34.100 85.140 ;
        RECT 28.500 91.140 29.000 91.640 ;
        RECT 30.200 91.140 30.700 91.640 ;
        RECT 31.900 91.140 32.400 91.640 ;
        RECT 33.600 91.140 34.100 91.640 ;
        RECT 28.500 87.240 29.000 87.740 ;
        RECT 30.200 87.240 30.700 87.740 ;
        RECT 31.900 87.240 32.400 87.740 ;
        RECT 33.600 87.240 34.100 87.740 ;
        RECT 28.500 92.820 29.000 93.320 ;
        RECT 30.200 92.820 30.700 93.320 ;
        RECT 31.900 92.820 32.400 93.320 ;
        RECT 33.600 92.820 34.100 93.320 ;
        RECT 28.500 83.340 29.000 83.840 ;
        RECT 30.200 83.340 30.700 83.840 ;
        RECT 31.900 83.340 32.400 83.840 ;
        RECT 33.600 83.340 34.100 83.840 ;
        RECT 29.930 94.530 30.470 95.070 ;
        RECT 30.200 72.940 30.700 73.440 ;
        RECT 31.900 72.940 32.400 73.440 ;
        RECT 33.600 72.940 34.100 73.440 ;
        RECT 28.500 75.540 29.000 76.040 ;
        RECT 30.200 75.540 30.700 76.040 ;
        RECT 31.900 75.540 32.400 76.040 ;
        RECT 33.600 75.540 34.100 76.040 ;
        RECT 28.500 78.140 29.000 78.640 ;
        RECT 30.200 78.140 30.700 78.640 ;
        RECT 31.900 78.140 32.400 78.640 ;
        RECT 33.600 78.140 34.100 78.640 ;
        RECT 28.500 76.840 29.000 77.340 ;
        RECT 30.200 76.840 30.700 77.340 ;
        RECT 31.900 76.840 32.400 77.340 ;
        RECT 33.600 76.840 34.100 77.340 ;
        RECT 28.500 82.040 29.000 82.540 ;
        RECT 30.200 82.040 30.700 82.540 ;
        RECT 31.900 82.040 32.400 82.540 ;
        RECT 33.600 82.040 34.100 82.540 ;
        RECT 28.500 79.440 29.000 79.940 ;
        RECT 30.200 79.440 30.700 79.940 ;
        RECT 31.900 79.440 32.400 79.940 ;
        RECT 33.600 79.440 34.100 79.940 ;
        RECT 28.500 74.240 29.000 74.740 ;
        RECT 30.200 74.240 30.700 74.740 ;
        RECT 31.900 74.240 32.400 74.740 ;
        RECT 33.600 74.240 34.100 74.740 ;
        RECT 28.500 71.640 29.000 72.140 ;
        RECT 30.200 71.640 30.700 72.140 ;
        RECT 31.900 71.640 32.400 72.140 ;
        RECT 33.600 71.640 34.100 72.140 ;
        RECT 28.500 72.940 29.000 73.440 ;
        RECT 37.000 78.140 37.500 78.640 ;
        RECT 38.700 78.140 39.200 78.640 ;
        RECT 40.400 78.140 40.900 78.640 ;
        RECT 35.300 79.440 35.800 79.940 ;
        RECT 37.000 79.440 37.500 79.940 ;
        RECT 38.700 79.440 39.200 79.940 ;
        RECT 40.400 79.440 40.900 79.940 ;
        RECT 35.300 72.940 35.800 73.440 ;
        RECT 37.000 72.940 37.500 73.440 ;
        RECT 38.700 72.940 39.200 73.440 ;
        RECT 40.400 72.940 40.900 73.440 ;
        RECT 35.300 82.040 35.800 82.540 ;
        RECT 37.000 82.040 37.500 82.540 ;
        RECT 38.700 82.040 39.200 82.540 ;
        RECT 40.400 82.040 40.900 82.540 ;
        RECT 35.300 74.240 35.800 74.740 ;
        RECT 37.000 74.240 37.500 74.740 ;
        RECT 38.700 74.240 39.200 74.740 ;
        RECT 40.400 74.240 40.900 74.740 ;
        RECT 35.300 76.840 35.800 77.340 ;
        RECT 37.000 76.840 37.500 77.340 ;
        RECT 38.700 76.840 39.200 77.340 ;
        RECT 40.400 76.840 40.900 77.340 ;
        RECT 35.300 75.540 35.800 76.040 ;
        RECT 37.000 75.540 37.500 76.040 ;
        RECT 38.700 75.540 39.200 76.040 ;
        RECT 40.400 75.540 40.900 76.040 ;
        RECT 35.300 71.640 35.800 72.140 ;
        RECT 37.000 71.640 37.500 72.140 ;
        RECT 38.700 71.640 39.200 72.140 ;
        RECT 40.400 71.640 40.900 72.140 ;
        RECT 35.300 78.140 35.800 78.640 ;
        RECT 35.300 59.940 35.800 60.440 ;
        RECT 37.000 59.940 37.500 60.440 ;
        RECT 38.700 59.940 39.200 60.440 ;
        RECT 40.400 59.940 40.900 60.440 ;
        RECT 35.300 61.240 35.800 61.740 ;
        RECT 37.000 61.240 37.500 61.740 ;
        RECT 38.700 61.240 39.200 61.740 ;
        RECT 40.400 61.240 40.900 61.740 ;
        RECT 35.300 62.540 35.800 63.040 ;
        RECT 37.000 62.540 37.500 63.040 ;
        RECT 38.700 62.540 39.200 63.040 ;
        RECT 40.400 62.540 40.900 63.040 ;
        RECT 35.300 63.840 35.800 64.340 ;
        RECT 37.000 63.840 37.500 64.340 ;
        RECT 38.700 63.840 39.200 64.340 ;
        RECT 40.400 63.840 40.900 64.340 ;
        RECT 35.300 65.140 35.800 65.640 ;
        RECT 37.000 65.140 37.500 65.640 ;
        RECT 38.700 65.140 39.200 65.640 ;
        RECT 40.400 65.140 40.900 65.640 ;
        RECT 35.300 66.440 35.800 66.940 ;
        RECT 37.000 66.440 37.500 66.940 ;
        RECT 38.700 66.440 39.200 66.940 ;
        RECT 40.400 66.440 40.900 66.940 ;
        RECT 35.300 67.740 35.800 68.240 ;
        RECT 37.000 67.740 37.500 68.240 ;
        RECT 38.700 67.740 39.200 68.240 ;
        RECT 40.400 67.740 40.900 68.240 ;
        RECT 35.300 70.340 35.800 70.840 ;
        RECT 37.000 70.340 37.500 70.840 ;
        RECT 38.700 70.340 39.200 70.840 ;
        RECT 40.400 70.340 40.900 70.840 ;
        RECT 28.500 65.140 29.000 65.640 ;
        RECT 30.200 65.140 30.700 65.640 ;
        RECT 31.900 65.140 32.400 65.640 ;
        RECT 33.600 65.140 34.100 65.640 ;
        RECT 28.500 62.540 29.000 63.040 ;
        RECT 30.200 62.540 30.700 63.040 ;
        RECT 31.900 62.540 32.400 63.040 ;
        RECT 33.600 62.540 34.100 63.040 ;
        RECT 28.500 66.440 29.000 66.940 ;
        RECT 30.200 66.440 30.700 66.940 ;
        RECT 31.900 66.440 32.400 66.940 ;
        RECT 33.600 66.440 34.100 66.940 ;
        RECT 28.500 61.240 29.000 61.740 ;
        RECT 30.200 61.240 30.700 61.740 ;
        RECT 31.900 61.240 32.400 61.740 ;
        RECT 33.600 61.240 34.100 61.740 ;
        RECT 28.500 67.740 29.000 68.240 ;
        RECT 30.200 67.740 30.700 68.240 ;
        RECT 31.900 67.740 32.400 68.240 ;
        RECT 33.600 67.740 34.100 68.240 ;
        RECT 28.500 63.840 29.000 64.340 ;
        RECT 30.200 63.840 30.700 64.340 ;
        RECT 31.900 63.840 32.400 64.340 ;
        RECT 33.600 63.840 34.100 64.340 ;
        RECT 28.500 70.340 29.000 70.840 ;
        RECT 30.200 70.340 30.700 70.840 ;
        RECT 31.900 70.340 32.400 70.840 ;
        RECT 33.600 70.340 34.100 70.840 ;
        RECT 28.500 59.940 29.000 60.440 ;
        RECT 30.200 59.940 30.700 60.440 ;
        RECT 31.900 59.940 32.400 60.440 ;
        RECT 33.600 59.940 34.100 60.440 ;
        RECT 33.600 48.240 34.100 48.740 ;
        RECT 28.500 49.540 29.000 50.040 ;
        RECT 30.200 49.540 30.700 50.040 ;
        RECT 31.900 49.540 32.400 50.040 ;
        RECT 33.600 49.540 34.100 50.040 ;
        RECT 28.500 50.840 29.000 51.340 ;
        RECT 30.200 50.840 30.700 51.340 ;
        RECT 31.900 50.840 32.400 51.340 ;
        RECT 33.600 50.840 34.100 51.340 ;
        RECT 28.500 52.140 29.000 52.640 ;
        RECT 30.200 52.140 30.700 52.640 ;
        RECT 31.900 52.140 32.400 52.640 ;
        RECT 33.600 52.140 34.100 52.640 ;
        RECT 28.500 53.440 29.000 53.940 ;
        RECT 30.200 53.440 30.700 53.940 ;
        RECT 31.900 53.440 32.400 53.940 ;
        RECT 33.600 53.440 34.100 53.940 ;
        RECT 28.500 54.740 29.000 55.240 ;
        RECT 30.200 54.740 30.700 55.240 ;
        RECT 31.900 54.740 32.400 55.240 ;
        RECT 33.600 54.740 34.100 55.240 ;
        RECT 28.500 56.040 29.000 56.540 ;
        RECT 30.200 56.040 30.700 56.540 ;
        RECT 31.900 56.040 32.400 56.540 ;
        RECT 33.600 56.040 34.100 56.540 ;
        RECT 28.500 58.640 29.000 59.140 ;
        RECT 30.200 58.640 30.700 59.140 ;
        RECT 31.900 58.640 32.400 59.140 ;
        RECT 33.600 58.640 34.100 59.140 ;
        RECT 30.200 48.240 30.700 48.740 ;
        RECT 31.900 48.240 32.400 48.740 ;
        RECT 28.500 48.240 29.000 48.740 ;
        RECT 37.000 48.240 37.500 48.740 ;
        RECT 38.700 48.240 39.200 48.740 ;
        RECT 40.400 48.240 40.900 48.740 ;
        RECT 35.300 53.440 35.800 53.940 ;
        RECT 37.000 53.440 37.500 53.940 ;
        RECT 38.700 53.440 39.200 53.940 ;
        RECT 40.400 53.440 40.900 53.940 ;
        RECT 35.300 50.840 35.800 51.340 ;
        RECT 37.000 50.840 37.500 51.340 ;
        RECT 38.700 50.840 39.200 51.340 ;
        RECT 40.400 50.840 40.900 51.340 ;
        RECT 35.300 54.740 35.800 55.240 ;
        RECT 37.000 54.740 37.500 55.240 ;
        RECT 38.700 54.740 39.200 55.240 ;
        RECT 40.400 54.740 40.900 55.240 ;
        RECT 35.300 49.540 35.800 50.040 ;
        RECT 37.000 49.540 37.500 50.040 ;
        RECT 38.700 49.540 39.200 50.040 ;
        RECT 40.400 49.540 40.900 50.040 ;
        RECT 35.300 56.040 35.800 56.540 ;
        RECT 37.000 56.040 37.500 56.540 ;
        RECT 38.700 56.040 39.200 56.540 ;
        RECT 40.400 56.040 40.900 56.540 ;
        RECT 35.300 52.140 35.800 52.640 ;
        RECT 37.000 52.140 37.500 52.640 ;
        RECT 38.700 52.140 39.200 52.640 ;
        RECT 40.400 52.140 40.900 52.640 ;
        RECT 35.300 58.640 35.800 59.140 ;
        RECT 37.000 58.640 37.500 59.140 ;
        RECT 38.700 58.640 39.200 59.140 ;
        RECT 40.400 58.640 40.900 59.140 ;
        RECT 35.300 48.240 35.800 48.740 ;
        RECT 48.900 59.940 49.400 60.440 ;
        RECT 50.600 59.940 51.100 60.440 ;
        RECT 52.300 59.940 52.800 60.440 ;
        RECT 54.000 59.940 54.500 60.440 ;
        RECT 48.900 61.240 49.400 61.740 ;
        RECT 50.600 61.240 51.100 61.740 ;
        RECT 52.300 61.240 52.800 61.740 ;
        RECT 54.000 61.240 54.500 61.740 ;
        RECT 48.900 62.540 49.400 63.040 ;
        RECT 50.600 62.540 51.100 63.040 ;
        RECT 52.300 62.540 52.800 63.040 ;
        RECT 54.000 62.540 54.500 63.040 ;
        RECT 48.900 63.840 49.400 64.340 ;
        RECT 50.600 63.840 51.100 64.340 ;
        RECT 52.300 63.840 52.800 64.340 ;
        RECT 54.000 63.840 54.500 64.340 ;
        RECT 48.900 65.140 49.400 65.640 ;
        RECT 50.600 65.140 51.100 65.640 ;
        RECT 52.300 65.140 52.800 65.640 ;
        RECT 54.000 65.140 54.500 65.640 ;
        RECT 48.900 66.440 49.400 66.940 ;
        RECT 50.600 66.440 51.100 66.940 ;
        RECT 52.300 66.440 52.800 66.940 ;
        RECT 54.000 66.440 54.500 66.940 ;
        RECT 48.900 67.740 49.400 68.240 ;
        RECT 50.600 67.740 51.100 68.240 ;
        RECT 52.300 67.740 52.800 68.240 ;
        RECT 54.000 67.740 54.500 68.240 ;
        RECT 48.900 70.340 49.400 70.840 ;
        RECT 50.600 70.340 51.100 70.840 ;
        RECT 52.300 70.340 52.800 70.840 ;
        RECT 54.000 70.340 54.500 70.840 ;
        RECT 42.100 65.140 42.600 65.640 ;
        RECT 43.800 65.140 44.300 65.640 ;
        RECT 45.500 65.140 46.000 65.640 ;
        RECT 47.200 65.140 47.700 65.640 ;
        RECT 42.100 62.540 42.600 63.040 ;
        RECT 43.800 62.540 44.300 63.040 ;
        RECT 45.500 62.540 46.000 63.040 ;
        RECT 47.200 62.540 47.700 63.040 ;
        RECT 42.100 66.440 42.600 66.940 ;
        RECT 43.800 66.440 44.300 66.940 ;
        RECT 45.500 66.440 46.000 66.940 ;
        RECT 47.200 66.440 47.700 66.940 ;
        RECT 42.100 61.240 42.600 61.740 ;
        RECT 43.800 61.240 44.300 61.740 ;
        RECT 45.500 61.240 46.000 61.740 ;
        RECT 47.200 61.240 47.700 61.740 ;
        RECT 42.100 67.740 42.600 68.240 ;
        RECT 43.800 67.740 44.300 68.240 ;
        RECT 45.500 67.740 46.000 68.240 ;
        RECT 47.200 67.740 47.700 68.240 ;
        RECT 42.100 63.840 42.600 64.340 ;
        RECT 43.800 63.840 44.300 64.340 ;
        RECT 45.500 63.840 46.000 64.340 ;
        RECT 47.200 63.840 47.700 64.340 ;
        RECT 42.100 70.340 42.600 70.840 ;
        RECT 43.800 70.340 44.300 70.840 ;
        RECT 45.500 70.340 46.000 70.840 ;
        RECT 47.200 70.340 47.700 70.840 ;
        RECT 42.100 59.940 42.600 60.440 ;
        RECT 43.800 59.940 44.300 60.440 ;
        RECT 45.500 59.940 46.000 60.440 ;
        RECT 47.200 59.940 47.700 60.440 ;
        RECT 47.200 50.840 47.700 51.340 ;
        RECT 43.800 48.240 44.300 48.740 ;
        RECT 45.500 48.240 46.000 48.740 ;
        RECT 42.100 53.440 42.600 53.940 ;
        RECT 43.800 53.440 44.300 53.940 ;
        RECT 45.500 53.440 46.000 53.940 ;
        RECT 42.100 49.540 42.600 50.040 ;
        RECT 42.100 52.140 42.600 52.640 ;
        RECT 43.800 52.140 44.300 52.640 ;
        RECT 45.500 52.140 46.000 52.640 ;
        RECT 47.200 52.140 47.700 52.640 ;
        RECT 43.800 49.540 44.300 50.040 ;
        RECT 45.500 49.540 46.000 50.040 ;
        RECT 47.200 49.540 47.700 50.040 ;
        RECT 47.200 53.440 47.700 53.940 ;
        RECT 47.200 48.240 47.700 48.740 ;
        RECT 42.100 50.840 42.600 51.340 ;
        RECT 42.100 54.740 42.600 55.240 ;
        RECT 43.800 54.740 44.300 55.240 ;
        RECT 42.100 58.640 42.600 59.140 ;
        RECT 43.800 58.640 44.300 59.140 ;
        RECT 45.500 58.640 46.000 59.140 ;
        RECT 47.200 58.640 47.700 59.140 ;
        RECT 45.500 54.740 46.000 55.240 ;
        RECT 47.200 54.740 47.700 55.240 ;
        RECT 43.800 50.840 44.300 51.340 ;
        RECT 42.100 56.040 42.600 56.540 ;
        RECT 43.800 56.040 44.300 56.540 ;
        RECT 45.500 56.040 46.000 56.540 ;
        RECT 47.200 56.040 47.700 56.540 ;
        RECT 45.500 50.840 46.000 51.340 ;
        RECT 42.100 48.240 42.600 48.740 ;
        RECT 50.600 54.740 51.100 55.240 ;
        RECT 52.300 54.740 52.800 55.240 ;
        RECT 54.000 54.740 54.500 55.240 ;
        RECT 48.900 52.140 49.400 52.640 ;
        RECT 50.600 52.140 51.100 52.640 ;
        RECT 52.300 52.140 52.800 52.640 ;
        RECT 54.000 52.140 54.500 52.640 ;
        RECT 48.900 53.440 49.400 53.940 ;
        RECT 50.600 53.440 51.100 53.940 ;
        RECT 52.300 53.440 52.800 53.940 ;
        RECT 54.000 53.440 54.500 53.940 ;
        RECT 48.900 48.240 49.400 48.740 ;
        RECT 50.600 48.240 51.100 48.740 ;
        RECT 52.300 48.240 52.800 48.740 ;
        RECT 54.000 48.240 54.500 48.740 ;
        RECT 48.900 56.040 49.400 56.540 ;
        RECT 50.600 56.040 51.100 56.540 ;
        RECT 52.300 56.040 52.800 56.540 ;
        RECT 54.000 56.040 54.500 56.540 ;
        RECT 48.900 58.640 49.400 59.140 ;
        RECT 50.600 58.640 51.100 59.140 ;
        RECT 52.300 58.640 52.800 59.140 ;
        RECT 54.000 58.640 54.500 59.140 ;
        RECT 48.900 50.840 49.400 51.340 ;
        RECT 50.600 50.840 51.100 51.340 ;
        RECT 52.300 50.840 52.800 51.340 ;
        RECT 54.000 50.840 54.500 51.340 ;
        RECT 48.900 49.540 49.400 50.040 ;
        RECT 50.600 49.540 51.100 50.040 ;
        RECT 52.300 49.540 52.800 50.040 ;
        RECT 54.000 49.540 54.500 50.040 ;
        RECT 48.900 54.740 49.400 55.240 ;
        RECT 21.700 83.340 22.200 83.840 ;
        RECT 23.400 83.340 23.900 83.840 ;
        RECT 25.100 83.340 25.600 83.840 ;
        RECT 26.800 83.340 27.300 83.840 ;
        RECT 21.700 84.640 22.200 85.140 ;
        RECT 23.400 84.640 23.900 85.140 ;
        RECT 25.100 84.640 25.600 85.140 ;
        RECT 26.800 84.640 27.300 85.140 ;
        RECT 21.700 85.940 22.200 86.440 ;
        RECT 23.400 85.940 23.900 86.440 ;
        RECT 25.100 85.940 25.600 86.440 ;
        RECT 26.800 85.940 27.300 86.440 ;
        RECT 21.700 87.240 22.200 87.740 ;
        RECT 23.400 87.240 23.900 87.740 ;
        RECT 25.100 87.240 25.600 87.740 ;
        RECT 26.800 87.240 27.300 87.740 ;
        RECT 21.700 88.540 22.200 89.040 ;
        RECT 23.400 88.540 23.900 89.040 ;
        RECT 25.100 88.540 25.600 89.040 ;
        RECT 26.800 88.540 27.300 89.040 ;
        RECT 21.700 89.840 22.200 90.340 ;
        RECT 23.400 89.840 23.900 90.340 ;
        RECT 25.100 89.840 25.600 90.340 ;
        RECT 26.800 89.840 27.300 90.340 ;
        RECT 21.700 91.140 22.200 91.640 ;
        RECT 23.400 91.140 23.900 91.640 ;
        RECT 25.100 91.140 25.600 91.640 ;
        RECT 26.800 91.140 27.300 91.640 ;
        RECT 21.700 92.820 22.200 93.320 ;
        RECT 23.400 92.820 23.900 93.320 ;
        RECT 25.100 92.820 25.600 93.320 ;
        RECT 26.800 92.820 27.300 93.320 ;
        RECT 14.900 88.540 15.400 89.040 ;
        RECT 16.600 88.540 17.100 89.040 ;
        RECT 18.300 88.540 18.800 89.040 ;
        RECT 20.000 88.540 20.500 89.040 ;
        RECT 14.900 85.940 15.400 86.440 ;
        RECT 16.600 85.940 17.100 86.440 ;
        RECT 18.300 85.940 18.800 86.440 ;
        RECT 20.000 85.940 20.500 86.440 ;
        RECT 14.900 89.840 15.400 90.340 ;
        RECT 16.600 89.840 17.100 90.340 ;
        RECT 18.300 89.840 18.800 90.340 ;
        RECT 20.000 89.840 20.500 90.340 ;
        RECT 14.900 84.640 15.400 85.140 ;
        RECT 16.600 84.640 17.100 85.140 ;
        RECT 18.300 84.640 18.800 85.140 ;
        RECT 20.000 84.640 20.500 85.140 ;
        RECT 14.900 91.140 15.400 91.640 ;
        RECT 16.600 91.140 17.100 91.640 ;
        RECT 18.300 91.140 18.800 91.640 ;
        RECT 20.000 91.140 20.500 91.640 ;
        RECT 14.900 87.240 15.400 87.740 ;
        RECT 16.600 87.240 17.100 87.740 ;
        RECT 18.300 87.240 18.800 87.740 ;
        RECT 20.000 87.240 20.500 87.740 ;
        RECT 14.900 92.820 15.400 93.320 ;
        RECT 16.600 92.820 17.100 93.320 ;
        RECT 18.300 92.820 18.800 93.320 ;
        RECT 20.000 92.820 20.500 93.320 ;
        RECT 14.900 83.340 15.400 83.840 ;
        RECT 16.600 83.340 17.100 83.840 ;
        RECT 18.300 83.340 18.800 83.840 ;
        RECT 20.000 83.340 20.500 83.840 ;
        RECT 14.900 71.640 15.400 72.140 ;
        RECT 16.600 71.640 17.100 72.140 ;
        RECT 18.300 71.640 18.800 72.140 ;
        RECT 20.000 71.640 20.500 72.140 ;
        RECT 14.900 72.940 15.400 73.440 ;
        RECT 16.600 72.940 17.100 73.440 ;
        RECT 18.300 72.940 18.800 73.440 ;
        RECT 20.000 72.940 20.500 73.440 ;
        RECT 14.900 74.240 15.400 74.740 ;
        RECT 16.600 74.240 17.100 74.740 ;
        RECT 18.300 74.240 18.800 74.740 ;
        RECT 20.000 74.240 20.500 74.740 ;
        RECT 14.900 75.540 15.400 76.040 ;
        RECT 16.600 75.540 17.100 76.040 ;
        RECT 18.300 75.540 18.800 76.040 ;
        RECT 20.000 75.540 20.500 76.040 ;
        RECT 14.900 76.840 15.400 77.340 ;
        RECT 16.600 76.840 17.100 77.340 ;
        RECT 18.300 76.840 18.800 77.340 ;
        RECT 20.000 76.840 20.500 77.340 ;
        RECT 14.900 78.140 15.400 78.640 ;
        RECT 16.600 78.140 17.100 78.640 ;
        RECT 18.300 78.140 18.800 78.640 ;
        RECT 20.000 78.140 20.500 78.640 ;
        RECT 14.900 79.440 15.400 79.940 ;
        RECT 16.600 79.440 17.100 79.940 ;
        RECT 18.300 79.440 18.800 79.940 ;
        RECT 20.000 79.440 20.500 79.940 ;
        RECT 14.900 82.040 15.400 82.540 ;
        RECT 16.600 82.040 17.100 82.540 ;
        RECT 18.300 82.040 18.800 82.540 ;
        RECT 20.000 82.040 20.500 82.540 ;
        RECT 21.700 71.640 22.200 72.140 ;
        RECT 23.400 71.640 23.900 72.140 ;
        RECT 25.100 71.640 25.600 72.140 ;
        RECT 26.800 71.640 27.300 72.140 ;
        RECT 21.700 76.840 22.200 77.340 ;
        RECT 23.400 76.840 23.900 77.340 ;
        RECT 25.100 76.840 25.600 77.340 ;
        RECT 26.800 76.840 27.300 77.340 ;
        RECT 21.700 74.240 22.200 74.740 ;
        RECT 23.400 74.240 23.900 74.740 ;
        RECT 25.100 74.240 25.600 74.740 ;
        RECT 26.800 74.240 27.300 74.740 ;
        RECT 21.700 78.140 22.200 78.640 ;
        RECT 23.400 78.140 23.900 78.640 ;
        RECT 25.100 78.140 25.600 78.640 ;
        RECT 26.800 78.140 27.300 78.640 ;
        RECT 21.700 72.940 22.200 73.440 ;
        RECT 23.400 72.940 23.900 73.440 ;
        RECT 25.100 72.940 25.600 73.440 ;
        RECT 26.800 72.940 27.300 73.440 ;
        RECT 21.700 79.440 22.200 79.940 ;
        RECT 23.400 79.440 23.900 79.940 ;
        RECT 25.100 79.440 25.600 79.940 ;
        RECT 26.800 79.440 27.300 79.940 ;
        RECT 21.700 75.540 22.200 76.040 ;
        RECT 23.400 75.540 23.900 76.040 ;
        RECT 25.100 75.540 25.600 76.040 ;
        RECT 26.800 75.540 27.300 76.040 ;
        RECT 21.700 82.040 22.200 82.540 ;
        RECT 23.400 82.040 23.900 82.540 ;
        RECT 25.100 82.040 25.600 82.540 ;
        RECT 26.800 82.040 27.300 82.540 ;
        RECT 7.930 93.680 8.470 94.220 ;
        RECT 9.800 83.340 10.300 83.840 ;
        RECT 11.500 83.340 12.000 83.840 ;
        RECT 13.200 83.340 13.700 83.840 ;
        RECT 8.100 84.640 8.600 85.140 ;
        RECT 9.800 84.640 10.300 85.140 ;
        RECT 11.500 84.640 12.000 85.140 ;
        RECT 13.200 84.640 13.700 85.140 ;
        RECT 8.100 85.940 8.600 86.440 ;
        RECT 9.800 85.940 10.300 86.440 ;
        RECT 11.500 85.940 12.000 86.440 ;
        RECT 13.200 85.940 13.700 86.440 ;
        RECT 8.100 87.240 8.600 87.740 ;
        RECT 9.800 87.240 10.300 87.740 ;
        RECT 11.500 87.240 12.000 87.740 ;
        RECT 13.200 87.240 13.700 87.740 ;
        RECT 8.100 88.540 8.600 89.040 ;
        RECT 9.800 88.540 10.300 89.040 ;
        RECT 11.500 88.540 12.000 89.040 ;
        RECT 13.200 88.540 13.700 89.040 ;
        RECT 8.100 89.840 8.600 90.340 ;
        RECT 9.800 89.840 10.300 90.340 ;
        RECT 11.500 89.840 12.000 90.340 ;
        RECT 13.200 89.840 13.700 90.340 ;
        RECT 8.100 91.140 8.600 91.640 ;
        RECT 9.800 91.140 10.300 91.640 ;
        RECT 11.500 91.140 12.000 91.640 ;
        RECT 13.200 91.140 13.700 91.640 ;
        RECT 8.100 92.820 8.600 93.320 ;
        RECT 9.800 92.820 10.300 93.320 ;
        RECT 11.500 92.820 12.000 93.320 ;
        RECT 13.200 92.820 13.700 93.320 ;
        RECT 8.100 83.340 8.600 83.840 ;
        RECT 4.700 88.540 5.200 89.040 ;
        RECT 6.400 88.540 6.900 89.040 ;
        RECT 3.000 85.940 3.500 86.440 ;
        RECT 4.700 85.940 5.200 86.440 ;
        RECT 6.400 85.940 6.900 86.440 ;
        RECT 3.000 84.640 3.500 85.140 ;
        RECT 1.300 89.840 1.800 90.340 ;
        RECT 3.000 89.840 3.500 90.340 ;
        RECT 4.700 89.840 5.200 90.340 ;
        RECT 6.400 89.840 6.900 90.340 ;
        RECT 4.700 84.640 5.200 85.140 ;
        RECT 6.400 84.640 6.900 85.140 ;
        RECT 4.700 83.340 5.200 83.840 ;
        RECT 1.300 87.240 1.800 87.740 ;
        RECT 1.300 91.140 1.800 91.640 ;
        RECT 3.000 91.140 3.500 91.640 ;
        RECT 4.700 91.140 5.200 91.640 ;
        RECT 6.400 91.140 6.900 91.640 ;
        RECT 3.000 87.240 3.500 87.740 ;
        RECT 4.700 87.240 5.200 87.740 ;
        RECT 6.400 87.240 6.900 87.740 ;
        RECT 6.400 83.340 6.900 83.840 ;
        RECT 1.300 92.820 1.800 93.320 ;
        RECT 3.000 92.820 3.500 93.320 ;
        RECT 4.700 92.820 5.200 93.320 ;
        RECT 6.400 92.820 6.900 93.320 ;
        RECT 3.000 83.340 3.500 83.840 ;
        RECT 1.300 84.640 1.800 85.140 ;
        RECT 1.300 85.940 1.800 86.440 ;
        RECT 1.300 88.540 1.800 89.040 ;
        RECT 1.300 83.340 1.800 83.840 ;
        RECT 3.000 88.540 3.500 89.040 ;
        RECT 1.300 75.540 1.800 76.040 ;
        RECT 1.300 79.440 1.800 79.940 ;
        RECT 4.700 75.540 5.200 76.040 ;
        RECT 6.400 75.540 6.900 76.040 ;
        RECT 6.400 71.640 6.900 72.140 ;
        RECT 1.300 82.040 1.800 82.540 ;
        RECT 3.000 78.140 3.500 78.640 ;
        RECT 4.700 78.140 5.200 78.640 ;
        RECT 6.400 78.140 6.900 78.640 ;
        RECT 4.700 72.940 5.200 73.440 ;
        RECT 3.000 76.840 3.500 77.340 ;
        RECT 4.700 76.840 5.200 77.340 ;
        RECT 6.400 76.840 6.900 77.340 ;
        RECT 3.000 74.240 3.500 74.740 ;
        RECT 3.000 82.040 3.500 82.540 ;
        RECT 4.700 82.040 5.200 82.540 ;
        RECT 6.400 82.040 6.900 82.540 ;
        RECT 3.000 79.440 3.500 79.940 ;
        RECT 4.700 79.440 5.200 79.940 ;
        RECT 6.400 79.440 6.900 79.940 ;
        RECT 3.000 75.540 3.500 76.040 ;
        RECT 4.700 74.240 5.200 74.740 ;
        RECT 6.400 74.240 6.900 74.740 ;
        RECT 3.000 72.940 3.500 73.440 ;
        RECT 1.300 78.140 1.800 78.640 ;
        RECT 3.000 71.640 3.500 72.140 ;
        RECT 1.300 72.940 1.800 73.440 ;
        RECT 1.300 74.240 1.800 74.740 ;
        RECT 1.300 76.840 1.800 77.340 ;
        RECT 6.400 72.940 6.900 73.440 ;
        RECT 4.700 71.640 5.200 72.140 ;
        RECT 1.300 71.640 1.800 72.140 ;
        RECT 9.800 72.940 10.300 73.440 ;
        RECT 8.100 79.440 8.600 79.940 ;
        RECT 9.800 79.440 10.300 79.940 ;
        RECT 11.500 79.440 12.000 79.940 ;
        RECT 13.200 79.440 13.700 79.940 ;
        RECT 11.500 72.940 12.000 73.440 ;
        RECT 13.200 72.940 13.700 73.440 ;
        RECT 11.500 78.140 12.000 78.640 ;
        RECT 13.200 78.140 13.700 78.640 ;
        RECT 8.100 82.040 8.600 82.540 ;
        RECT 9.800 82.040 10.300 82.540 ;
        RECT 11.500 82.040 12.000 82.540 ;
        RECT 13.200 82.040 13.700 82.540 ;
        RECT 8.100 71.640 8.600 72.140 ;
        RECT 9.800 74.240 10.300 74.740 ;
        RECT 11.500 74.240 12.000 74.740 ;
        RECT 13.200 74.240 13.700 74.740 ;
        RECT 13.200 76.840 13.700 77.340 ;
        RECT 8.100 76.840 8.600 77.340 ;
        RECT 9.800 76.840 10.300 77.340 ;
        RECT 11.500 76.840 12.000 77.340 ;
        RECT 8.100 75.540 8.600 76.040 ;
        RECT 9.800 71.640 10.300 72.140 ;
        RECT 11.500 71.640 12.000 72.140 ;
        RECT 13.200 71.640 13.700 72.140 ;
        RECT 9.800 75.540 10.300 76.040 ;
        RECT 11.500 75.540 12.000 76.040 ;
        RECT 13.200 75.540 13.700 76.040 ;
        RECT 8.100 74.240 8.600 74.740 ;
        RECT 8.100 78.140 8.600 78.640 ;
        RECT 9.800 78.140 10.300 78.640 ;
        RECT 8.100 72.940 8.600 73.440 ;
        RECT 8.100 66.440 8.600 66.940 ;
        RECT 9.800 66.440 10.300 66.940 ;
        RECT 11.500 66.440 12.000 66.940 ;
        RECT 13.200 66.440 13.700 66.940 ;
        RECT 8.100 67.740 8.600 68.240 ;
        RECT 9.800 67.740 10.300 68.240 ;
        RECT 11.500 67.740 12.000 68.240 ;
        RECT 13.200 67.740 13.700 68.240 ;
        RECT 8.100 65.140 8.600 65.640 ;
        RECT 9.800 65.140 10.300 65.640 ;
        RECT 11.500 65.140 12.000 65.640 ;
        RECT 13.200 65.140 13.700 65.640 ;
        RECT 8.100 61.240 8.600 61.740 ;
        RECT 9.800 61.240 10.300 61.740 ;
        RECT 11.500 61.240 12.000 61.740 ;
        RECT 13.200 61.240 13.700 61.740 ;
        RECT 8.100 59.940 8.600 60.440 ;
        RECT 9.800 59.940 10.300 60.440 ;
        RECT 11.500 59.940 12.000 60.440 ;
        RECT 13.200 59.940 13.700 60.440 ;
        RECT 8.100 70.340 8.600 70.840 ;
        RECT 9.800 70.340 10.300 70.840 ;
        RECT 11.500 70.340 12.000 70.840 ;
        RECT 13.200 70.340 13.700 70.840 ;
        RECT 8.100 63.840 8.600 64.340 ;
        RECT 9.800 63.840 10.300 64.340 ;
        RECT 11.500 63.840 12.000 64.340 ;
        RECT 13.200 63.840 13.700 64.340 ;
        RECT 8.100 62.540 8.600 63.040 ;
        RECT 9.800 62.540 10.300 63.040 ;
        RECT 11.500 62.540 12.000 63.040 ;
        RECT 13.200 62.540 13.700 63.040 ;
        RECT 4.700 59.940 5.200 60.440 ;
        RECT 6.400 59.940 6.900 60.440 ;
        RECT 4.700 65.140 5.200 65.640 ;
        RECT 6.400 65.140 6.900 65.640 ;
        RECT 4.700 67.740 5.200 68.240 ;
        RECT 6.400 67.740 6.900 68.240 ;
        RECT 1.300 70.340 1.800 70.840 ;
        RECT 3.000 70.340 3.500 70.840 ;
        RECT 4.700 70.340 5.200 70.840 ;
        RECT 6.400 70.340 6.900 70.840 ;
        RECT 4.700 66.440 5.200 66.940 ;
        RECT 6.400 66.440 6.900 66.940 ;
        RECT 1.300 61.240 1.800 61.740 ;
        RECT 3.000 61.240 3.500 61.740 ;
        RECT 1.300 63.840 1.800 64.340 ;
        RECT 3.000 63.840 3.500 64.340 ;
        RECT 4.700 63.840 5.200 64.340 ;
        RECT 6.400 63.840 6.900 64.340 ;
        RECT 4.700 61.240 5.200 61.740 ;
        RECT 6.400 61.240 6.900 61.740 ;
        RECT 1.300 67.740 1.800 68.240 ;
        RECT 3.000 67.740 3.500 68.240 ;
        RECT 1.300 62.540 1.800 63.040 ;
        RECT 3.000 62.540 3.500 63.040 ;
        RECT 4.700 62.540 5.200 63.040 ;
        RECT 6.400 62.540 6.900 63.040 ;
        RECT 1.300 65.140 1.800 65.640 ;
        RECT 3.000 65.140 3.500 65.640 ;
        RECT 1.300 59.940 1.800 60.440 ;
        RECT 3.000 59.940 3.500 60.440 ;
        RECT 1.300 66.440 1.800 66.940 ;
        RECT 3.000 66.440 3.500 66.940 ;
        RECT 4.700 56.040 5.200 56.540 ;
        RECT 6.400 56.040 6.900 56.540 ;
        RECT 1.300 50.840 1.800 51.340 ;
        RECT 3.000 50.840 3.500 51.340 ;
        RECT 4.700 50.840 5.200 51.340 ;
        RECT 6.400 50.840 6.900 51.340 ;
        RECT 1.300 54.740 1.800 55.240 ;
        RECT 3.000 54.740 3.500 55.240 ;
        RECT 4.700 54.740 5.200 55.240 ;
        RECT 6.400 54.740 6.900 55.240 ;
        RECT 1.300 53.440 1.800 53.940 ;
        RECT 3.000 53.440 3.500 53.940 ;
        RECT 4.700 53.440 5.200 53.940 ;
        RECT 6.400 53.440 6.900 53.940 ;
        RECT 1.300 58.640 1.800 59.140 ;
        RECT 3.000 58.640 3.500 59.140 ;
        RECT 4.700 58.640 5.200 59.140 ;
        RECT 6.400 58.640 6.900 59.140 ;
        RECT 1.300 49.540 1.800 50.040 ;
        RECT 3.000 49.540 3.500 50.040 ;
        RECT 4.700 49.540 5.200 50.040 ;
        RECT 6.400 49.540 6.900 50.040 ;
        RECT 1.300 52.140 1.800 52.640 ;
        RECT 3.000 52.140 3.500 52.640 ;
        RECT 4.700 52.140 5.200 52.640 ;
        RECT 6.400 52.140 6.900 52.640 ;
        RECT 1.300 48.240 1.800 48.740 ;
        RECT 3.000 48.240 3.500 48.740 ;
        RECT 4.700 48.240 5.200 48.740 ;
        RECT 6.400 48.240 6.900 48.740 ;
        RECT 1.300 56.040 1.800 56.540 ;
        RECT 3.000 56.040 3.500 56.540 ;
        RECT 11.500 52.140 12.000 52.640 ;
        RECT 13.200 52.140 13.700 52.640 ;
        RECT 8.100 49.540 8.600 50.040 ;
        RECT 9.800 49.540 10.300 50.040 ;
        RECT 11.500 49.540 12.000 50.040 ;
        RECT 13.200 49.540 13.700 50.040 ;
        RECT 8.100 58.640 8.600 59.140 ;
        RECT 9.800 58.640 10.300 59.140 ;
        RECT 11.500 58.640 12.000 59.140 ;
        RECT 13.200 58.640 13.700 59.140 ;
        RECT 8.100 50.840 8.600 51.340 ;
        RECT 9.800 50.840 10.300 51.340 ;
        RECT 11.500 50.840 12.000 51.340 ;
        RECT 13.200 50.840 13.700 51.340 ;
        RECT 8.100 53.440 8.600 53.940 ;
        RECT 9.800 53.440 10.300 53.940 ;
        RECT 11.500 53.440 12.000 53.940 ;
        RECT 13.200 53.440 13.700 53.940 ;
        RECT 8.100 54.740 8.600 55.240 ;
        RECT 9.800 54.740 10.300 55.240 ;
        RECT 11.500 54.740 12.000 55.240 ;
        RECT 13.200 54.740 13.700 55.240 ;
        RECT 8.100 56.040 8.600 56.540 ;
        RECT 9.800 56.040 10.300 56.540 ;
        RECT 11.500 56.040 12.000 56.540 ;
        RECT 13.200 56.040 13.700 56.540 ;
        RECT 8.100 48.240 8.600 48.740 ;
        RECT 9.800 48.240 10.300 48.740 ;
        RECT 11.500 48.240 12.000 48.740 ;
        RECT 13.200 48.240 13.700 48.740 ;
        RECT 8.100 52.140 8.600 52.640 ;
        RECT 9.800 52.140 10.300 52.640 ;
        RECT 21.700 63.840 22.200 64.340 ;
        RECT 23.400 63.840 23.900 64.340 ;
        RECT 25.100 63.840 25.600 64.340 ;
        RECT 26.800 63.840 27.300 64.340 ;
        RECT 21.700 59.940 22.200 60.440 ;
        RECT 23.400 59.940 23.900 60.440 ;
        RECT 25.100 59.940 25.600 60.440 ;
        RECT 26.800 59.940 27.300 60.440 ;
        RECT 21.700 67.740 22.200 68.240 ;
        RECT 23.400 67.740 23.900 68.240 ;
        RECT 25.100 67.740 25.600 68.240 ;
        RECT 26.800 67.740 27.300 68.240 ;
        RECT 21.700 61.240 22.200 61.740 ;
        RECT 23.400 61.240 23.900 61.740 ;
        RECT 25.100 61.240 25.600 61.740 ;
        RECT 26.800 61.240 27.300 61.740 ;
        RECT 21.700 66.440 22.200 66.940 ;
        RECT 23.400 66.440 23.900 66.940 ;
        RECT 25.100 66.440 25.600 66.940 ;
        RECT 26.800 66.440 27.300 66.940 ;
        RECT 21.700 62.540 22.200 63.040 ;
        RECT 23.400 62.540 23.900 63.040 ;
        RECT 25.100 62.540 25.600 63.040 ;
        RECT 26.800 62.540 27.300 63.040 ;
        RECT 21.700 70.340 22.200 70.840 ;
        RECT 23.400 70.340 23.900 70.840 ;
        RECT 25.100 70.340 25.600 70.840 ;
        RECT 26.800 70.340 27.300 70.840 ;
        RECT 21.700 65.140 22.200 65.640 ;
        RECT 23.400 65.140 23.900 65.640 ;
        RECT 25.100 65.140 25.600 65.640 ;
        RECT 26.800 65.140 27.300 65.640 ;
        RECT 18.300 66.440 18.800 66.940 ;
        RECT 20.000 66.440 20.500 66.940 ;
        RECT 18.300 67.740 18.800 68.240 ;
        RECT 20.000 67.740 20.500 68.240 ;
        RECT 18.300 59.940 18.800 60.440 ;
        RECT 20.000 59.940 20.500 60.440 ;
        RECT 14.900 62.540 15.400 63.040 ;
        RECT 16.600 62.540 17.100 63.040 ;
        RECT 18.300 62.540 18.800 63.040 ;
        RECT 20.000 62.540 20.500 63.040 ;
        RECT 18.300 63.840 18.800 64.340 ;
        RECT 20.000 63.840 20.500 64.340 ;
        RECT 14.900 61.240 15.400 61.740 ;
        RECT 16.600 61.240 17.100 61.740 ;
        RECT 14.900 70.340 15.400 70.840 ;
        RECT 16.600 70.340 17.100 70.840 ;
        RECT 18.300 70.340 18.800 70.840 ;
        RECT 20.000 70.340 20.500 70.840 ;
        RECT 18.300 61.240 18.800 61.740 ;
        RECT 20.000 61.240 20.500 61.740 ;
        RECT 14.900 59.940 15.400 60.440 ;
        RECT 16.600 59.940 17.100 60.440 ;
        RECT 14.900 65.140 15.400 65.640 ;
        RECT 16.600 65.140 17.100 65.640 ;
        RECT 18.300 65.140 18.800 65.640 ;
        RECT 20.000 65.140 20.500 65.640 ;
        RECT 14.900 67.740 15.400 68.240 ;
        RECT 16.600 67.740 17.100 68.240 ;
        RECT 14.900 66.440 15.400 66.940 ;
        RECT 16.600 66.440 17.100 66.940 ;
        RECT 14.900 63.840 15.400 64.340 ;
        RECT 16.600 63.840 17.100 64.340 ;
        RECT 18.300 53.440 18.800 53.940 ;
        RECT 20.000 53.440 20.500 53.940 ;
        RECT 14.900 56.040 15.400 56.540 ;
        RECT 16.600 56.040 17.100 56.540 ;
        RECT 18.300 56.040 18.800 56.540 ;
        RECT 20.000 56.040 20.500 56.540 ;
        RECT 14.900 54.740 15.400 55.240 ;
        RECT 16.600 54.740 17.100 55.240 ;
        RECT 18.300 54.740 18.800 55.240 ;
        RECT 20.000 54.740 20.500 55.240 ;
        RECT 14.900 50.840 15.400 51.340 ;
        RECT 16.600 50.840 17.100 51.340 ;
        RECT 18.300 50.840 18.800 51.340 ;
        RECT 20.000 50.840 20.500 51.340 ;
        RECT 14.900 49.540 15.400 50.040 ;
        RECT 16.600 49.540 17.100 50.040 ;
        RECT 18.300 49.540 18.800 50.040 ;
        RECT 20.000 49.540 20.500 50.040 ;
        RECT 14.900 58.640 15.400 59.140 ;
        RECT 16.600 58.640 17.100 59.140 ;
        RECT 18.300 58.640 18.800 59.140 ;
        RECT 20.000 58.640 20.500 59.140 ;
        RECT 14.900 52.140 15.400 52.640 ;
        RECT 16.600 52.140 17.100 52.640 ;
        RECT 18.300 52.140 18.800 52.640 ;
        RECT 20.000 52.140 20.500 52.640 ;
        RECT 14.900 48.240 15.400 48.740 ;
        RECT 16.600 48.240 17.100 48.740 ;
        RECT 18.300 48.240 18.800 48.740 ;
        RECT 20.000 48.240 20.500 48.740 ;
        RECT 14.900 53.440 15.400 53.940 ;
        RECT 16.600 53.440 17.100 53.940 ;
        RECT 25.100 53.440 25.600 53.940 ;
        RECT 26.800 53.440 27.300 53.940 ;
        RECT 21.700 50.840 22.200 51.340 ;
        RECT 23.400 50.840 23.900 51.340 ;
        RECT 25.100 50.840 25.600 51.340 ;
        RECT 26.800 50.840 27.300 51.340 ;
        RECT 21.700 58.640 22.200 59.140 ;
        RECT 23.400 58.640 23.900 59.140 ;
        RECT 25.100 58.640 25.600 59.140 ;
        RECT 26.800 58.640 27.300 59.140 ;
        RECT 21.700 54.740 22.200 55.240 ;
        RECT 23.400 54.740 23.900 55.240 ;
        RECT 25.100 54.740 25.600 55.240 ;
        RECT 26.800 54.740 27.300 55.240 ;
        RECT 21.700 56.040 22.200 56.540 ;
        RECT 23.400 56.040 23.900 56.540 ;
        RECT 25.100 56.040 25.600 56.540 ;
        RECT 26.800 56.040 27.300 56.540 ;
        RECT 21.700 52.140 22.200 52.640 ;
        RECT 23.400 52.140 23.900 52.640 ;
        RECT 25.100 52.140 25.600 52.640 ;
        RECT 26.800 52.140 27.300 52.640 ;
        RECT 21.700 49.540 22.200 50.040 ;
        RECT 23.400 49.540 23.900 50.040 ;
        RECT 25.100 49.540 25.600 50.040 ;
        RECT 26.800 49.540 27.300 50.040 ;
        RECT 21.700 48.240 22.200 48.740 ;
        RECT 23.400 48.240 23.900 48.740 ;
        RECT 25.100 48.240 25.600 48.740 ;
        RECT 26.800 48.240 27.300 48.740 ;
        RECT 21.700 53.440 22.200 53.940 ;
        RECT 23.400 53.440 23.900 53.940 ;
        RECT 1.300 23.540 1.800 24.040 ;
        RECT 3.000 23.540 3.500 24.040 ;
        RECT 4.700 23.540 5.200 24.040 ;
        RECT 6.400 23.540 6.900 24.040 ;
        RECT 8.100 23.540 8.600 24.040 ;
        RECT 9.800 23.540 10.300 24.040 ;
        RECT 11.500 23.540 12.000 24.040 ;
        RECT 13.200 23.540 13.700 24.040 ;
        RECT 14.900 23.540 15.400 24.040 ;
        RECT 16.600 23.540 17.100 24.040 ;
        RECT 18.300 23.540 18.800 24.040 ;
        RECT 20.000 23.540 20.500 24.040 ;
        RECT 21.700 23.540 22.200 24.040 ;
        RECT 23.400 23.540 23.900 24.040 ;
        RECT 25.100 23.540 25.600 24.040 ;
        RECT 26.800 23.540 27.300 24.040 ;
        RECT 14.900 35.240 15.400 35.740 ;
        RECT 16.600 35.240 17.100 35.740 ;
        RECT 18.300 35.240 18.800 35.740 ;
        RECT 20.000 35.240 20.500 35.740 ;
        RECT 21.700 35.240 22.200 35.740 ;
        RECT 23.400 35.240 23.900 35.740 ;
        RECT 25.100 35.240 25.600 35.740 ;
        RECT 26.800 35.240 27.300 35.740 ;
        RECT 21.700 44.340 22.200 44.840 ;
        RECT 23.400 44.340 23.900 44.840 ;
        RECT 25.100 44.340 25.600 44.840 ;
        RECT 26.800 44.340 27.300 44.840 ;
        RECT 21.700 46.940 22.200 47.440 ;
        RECT 23.400 46.940 23.900 47.440 ;
        RECT 25.100 46.940 25.600 47.440 ;
        RECT 26.800 46.940 27.300 47.440 ;
        RECT 21.700 36.540 22.200 37.040 ;
        RECT 23.400 36.540 23.900 37.040 ;
        RECT 25.100 36.540 25.600 37.040 ;
        RECT 26.800 36.540 27.300 37.040 ;
        RECT 21.700 37.840 22.200 38.340 ;
        RECT 23.400 37.840 23.900 38.340 ;
        RECT 25.100 37.840 25.600 38.340 ;
        RECT 26.800 37.840 27.300 38.340 ;
        RECT 21.700 39.140 22.200 39.640 ;
        RECT 23.400 39.140 23.900 39.640 ;
        RECT 25.100 39.140 25.600 39.640 ;
        RECT 26.800 39.140 27.300 39.640 ;
        RECT 21.700 40.440 22.200 40.940 ;
        RECT 23.400 40.440 23.900 40.940 ;
        RECT 25.100 40.440 25.600 40.940 ;
        RECT 26.800 40.440 27.300 40.940 ;
        RECT 21.700 41.740 22.200 42.240 ;
        RECT 23.400 41.740 23.900 42.240 ;
        RECT 25.100 41.740 25.600 42.240 ;
        RECT 26.800 41.740 27.300 42.240 ;
        RECT 21.700 43.040 22.200 43.540 ;
        RECT 23.400 43.040 23.900 43.540 ;
        RECT 25.100 43.040 25.600 43.540 ;
        RECT 26.800 43.040 27.300 43.540 ;
        RECT 14.900 39.140 15.400 39.640 ;
        RECT 16.600 39.140 17.100 39.640 ;
        RECT 18.300 39.140 18.800 39.640 ;
        RECT 20.000 39.140 20.500 39.640 ;
        RECT 14.900 36.540 15.400 37.040 ;
        RECT 16.600 36.540 17.100 37.040 ;
        RECT 18.300 36.540 18.800 37.040 ;
        RECT 20.000 36.540 20.500 37.040 ;
        RECT 14.900 40.440 15.400 40.940 ;
        RECT 16.600 40.440 17.100 40.940 ;
        RECT 18.300 40.440 18.800 40.940 ;
        RECT 20.000 40.440 20.500 40.940 ;
        RECT 14.900 46.940 15.400 47.440 ;
        RECT 16.600 46.940 17.100 47.440 ;
        RECT 18.300 46.940 18.800 47.440 ;
        RECT 20.000 46.940 20.500 47.440 ;
        RECT 14.900 41.740 15.400 42.240 ;
        RECT 16.600 41.740 17.100 42.240 ;
        RECT 18.300 41.740 18.800 42.240 ;
        RECT 20.000 41.740 20.500 42.240 ;
        RECT 14.900 37.840 15.400 38.340 ;
        RECT 16.600 37.840 17.100 38.340 ;
        RECT 18.300 37.840 18.800 38.340 ;
        RECT 20.000 37.840 20.500 38.340 ;
        RECT 14.900 43.040 15.400 43.540 ;
        RECT 16.600 43.040 17.100 43.540 ;
        RECT 18.300 43.040 18.800 43.540 ;
        RECT 20.000 43.040 20.500 43.540 ;
        RECT 14.900 44.340 15.400 44.840 ;
        RECT 16.600 44.340 17.100 44.840 ;
        RECT 18.300 44.340 18.800 44.840 ;
        RECT 20.000 44.340 20.500 44.840 ;
        RECT 14.900 24.840 15.400 25.340 ;
        RECT 16.600 24.840 17.100 25.340 ;
        RECT 18.300 24.840 18.800 25.340 ;
        RECT 20.000 24.840 20.500 25.340 ;
        RECT 14.900 26.140 15.400 26.640 ;
        RECT 16.600 26.140 17.100 26.640 ;
        RECT 18.300 26.140 18.800 26.640 ;
        RECT 20.000 26.140 20.500 26.640 ;
        RECT 14.900 27.440 15.400 27.940 ;
        RECT 16.600 27.440 17.100 27.940 ;
        RECT 18.300 27.440 18.800 27.940 ;
        RECT 20.000 27.440 20.500 27.940 ;
        RECT 14.900 28.740 15.400 29.240 ;
        RECT 16.600 28.740 17.100 29.240 ;
        RECT 18.300 28.740 18.800 29.240 ;
        RECT 20.000 28.740 20.500 29.240 ;
        RECT 14.900 30.040 15.400 30.540 ;
        RECT 16.600 30.040 17.100 30.540 ;
        RECT 18.300 30.040 18.800 30.540 ;
        RECT 20.000 30.040 20.500 30.540 ;
        RECT 14.900 31.340 15.400 31.840 ;
        RECT 16.600 31.340 17.100 31.840 ;
        RECT 18.300 31.340 18.800 31.840 ;
        RECT 20.000 31.340 20.500 31.840 ;
        RECT 14.900 32.640 15.400 33.140 ;
        RECT 16.600 32.640 17.100 33.140 ;
        RECT 18.300 32.640 18.800 33.140 ;
        RECT 20.000 32.640 20.500 33.140 ;
        RECT 21.700 28.740 22.200 29.240 ;
        RECT 23.400 28.740 23.900 29.240 ;
        RECT 25.100 28.740 25.600 29.240 ;
        RECT 26.800 28.740 27.300 29.240 ;
        RECT 21.700 24.840 22.200 25.340 ;
        RECT 23.400 24.840 23.900 25.340 ;
        RECT 25.100 24.840 25.600 25.340 ;
        RECT 26.800 24.840 27.300 25.340 ;
        RECT 21.700 30.040 22.200 30.540 ;
        RECT 23.400 30.040 23.900 30.540 ;
        RECT 25.100 30.040 25.600 30.540 ;
        RECT 26.800 30.040 27.300 30.540 ;
        RECT 21.700 27.440 22.200 27.940 ;
        RECT 23.400 27.440 23.900 27.940 ;
        RECT 25.100 27.440 25.600 27.940 ;
        RECT 26.800 27.440 27.300 27.940 ;
        RECT 21.700 31.340 22.200 31.840 ;
        RECT 23.400 31.340 23.900 31.840 ;
        RECT 25.100 31.340 25.600 31.840 ;
        RECT 26.800 31.340 27.300 31.840 ;
        RECT 21.700 26.140 22.200 26.640 ;
        RECT 23.400 26.140 23.900 26.640 ;
        RECT 25.100 26.140 25.600 26.640 ;
        RECT 26.800 26.140 27.300 26.640 ;
        RECT 21.700 32.640 22.200 33.140 ;
        RECT 23.400 32.640 23.900 33.140 ;
        RECT 25.100 32.640 25.600 33.140 ;
        RECT 26.800 32.640 27.300 33.140 ;
        RECT 1.300 35.240 1.800 35.740 ;
        RECT 3.000 35.240 3.500 35.740 ;
        RECT 4.700 35.240 5.200 35.740 ;
        RECT 6.400 35.240 6.900 35.740 ;
        RECT 8.100 35.240 8.600 35.740 ;
        RECT 9.800 35.240 10.300 35.740 ;
        RECT 11.500 35.240 12.000 35.740 ;
        RECT 13.200 35.240 13.700 35.740 ;
        RECT 8.100 46.940 8.600 47.440 ;
        RECT 9.800 46.940 10.300 47.440 ;
        RECT 8.100 36.540 8.600 37.040 ;
        RECT 9.800 36.540 10.300 37.040 ;
        RECT 11.500 36.540 12.000 37.040 ;
        RECT 13.200 36.540 13.700 37.040 ;
        RECT 11.500 46.940 12.000 47.440 ;
        RECT 13.200 46.940 13.700 47.440 ;
        RECT 8.100 37.840 8.600 38.340 ;
        RECT 9.800 37.840 10.300 38.340 ;
        RECT 11.500 37.840 12.000 38.340 ;
        RECT 13.200 37.840 13.700 38.340 ;
        RECT 8.100 44.340 8.600 44.840 ;
        RECT 9.800 44.340 10.300 44.840 ;
        RECT 11.500 44.340 12.000 44.840 ;
        RECT 13.200 44.340 13.700 44.840 ;
        RECT 8.100 39.140 8.600 39.640 ;
        RECT 9.800 39.140 10.300 39.640 ;
        RECT 11.500 39.140 12.000 39.640 ;
        RECT 13.200 39.140 13.700 39.640 ;
        RECT 8.100 40.440 8.600 40.940 ;
        RECT 9.800 40.440 10.300 40.940 ;
        RECT 11.500 40.440 12.000 40.940 ;
        RECT 13.200 40.440 13.700 40.940 ;
        RECT 8.100 41.740 8.600 42.240 ;
        RECT 9.800 41.740 10.300 42.240 ;
        RECT 11.500 41.740 12.000 42.240 ;
        RECT 13.200 41.740 13.700 42.240 ;
        RECT 8.100 43.040 8.600 43.540 ;
        RECT 9.800 43.040 10.300 43.540 ;
        RECT 11.500 43.040 12.000 43.540 ;
        RECT 13.200 43.040 13.700 43.540 ;
        RECT 1.300 40.440 1.800 40.940 ;
        RECT 3.000 40.440 3.500 40.940 ;
        RECT 4.700 40.440 5.200 40.940 ;
        RECT 6.400 40.440 6.900 40.940 ;
        RECT 1.300 37.840 1.800 38.340 ;
        RECT 3.000 37.840 3.500 38.340 ;
        RECT 4.700 37.840 5.200 38.340 ;
        RECT 6.400 37.840 6.900 38.340 ;
        RECT 4.700 44.340 5.200 44.840 ;
        RECT 6.400 44.340 6.900 44.840 ;
        RECT 1.300 41.740 1.800 42.240 ;
        RECT 3.000 41.740 3.500 42.240 ;
        RECT 4.700 41.740 5.200 42.240 ;
        RECT 6.400 41.740 6.900 42.240 ;
        RECT 1.300 39.140 1.800 39.640 ;
        RECT 3.000 39.140 3.500 39.640 ;
        RECT 4.700 39.140 5.200 39.640 ;
        RECT 6.400 39.140 6.900 39.640 ;
        RECT 1.300 46.940 1.800 47.440 ;
        RECT 3.000 46.940 3.500 47.440 ;
        RECT 1.300 43.040 1.800 43.540 ;
        RECT 3.000 43.040 3.500 43.540 ;
        RECT 4.700 43.040 5.200 43.540 ;
        RECT 6.400 43.040 6.900 43.540 ;
        RECT 4.700 36.540 5.200 37.040 ;
        RECT 6.400 36.540 6.900 37.040 ;
        RECT 1.300 36.540 1.800 37.040 ;
        RECT 3.000 36.540 3.500 37.040 ;
        RECT 4.700 46.940 5.200 47.440 ;
        RECT 6.400 46.940 6.900 47.440 ;
        RECT 1.300 44.340 1.800 44.840 ;
        RECT 3.000 44.340 3.500 44.840 ;
        RECT 4.700 24.840 5.200 25.340 ;
        RECT 6.400 24.840 6.900 25.340 ;
        RECT 4.700 30.040 5.200 30.540 ;
        RECT 6.400 30.040 6.900 30.540 ;
        RECT 4.700 26.140 5.200 26.640 ;
        RECT 6.400 26.140 6.900 26.640 ;
        RECT 4.700 31.340 5.200 31.840 ;
        RECT 6.400 31.340 6.900 31.840 ;
        RECT 4.700 32.640 5.200 33.140 ;
        RECT 6.400 32.640 6.900 33.140 ;
        RECT 1.300 26.140 1.800 26.640 ;
        RECT 3.000 26.140 3.500 26.640 ;
        RECT 1.300 30.040 1.800 30.540 ;
        RECT 3.000 30.040 3.500 30.540 ;
        RECT 4.700 27.440 5.200 27.940 ;
        RECT 6.400 27.440 6.900 27.940 ;
        RECT 1.300 28.740 1.800 29.240 ;
        RECT 3.000 28.740 3.500 29.240 ;
        RECT 1.300 31.340 1.800 31.840 ;
        RECT 3.000 31.340 3.500 31.840 ;
        RECT 1.300 24.840 1.800 25.340 ;
        RECT 3.000 24.840 3.500 25.340 ;
        RECT 1.300 27.440 1.800 27.940 ;
        RECT 3.000 27.440 3.500 27.940 ;
        RECT 1.300 32.640 1.800 33.140 ;
        RECT 3.000 32.640 3.500 33.140 ;
        RECT 4.700 28.740 5.200 29.240 ;
        RECT 6.400 28.740 6.900 29.240 ;
        RECT 8.100 28.740 8.600 29.240 ;
        RECT 9.800 28.740 10.300 29.240 ;
        RECT 11.500 28.740 12.000 29.240 ;
        RECT 13.200 28.740 13.700 29.240 ;
        RECT 8.100 31.340 8.600 31.840 ;
        RECT 9.800 31.340 10.300 31.840 ;
        RECT 11.500 31.340 12.000 31.840 ;
        RECT 13.200 31.340 13.700 31.840 ;
        RECT 8.100 27.440 8.600 27.940 ;
        RECT 9.800 27.440 10.300 27.940 ;
        RECT 11.500 27.440 12.000 27.940 ;
        RECT 13.200 27.440 13.700 27.940 ;
        RECT 11.500 32.640 12.000 33.140 ;
        RECT 13.200 32.640 13.700 33.140 ;
        RECT 8.100 26.140 8.600 26.640 ;
        RECT 9.800 26.140 10.300 26.640 ;
        RECT 11.500 26.140 12.000 26.640 ;
        RECT 13.200 26.140 13.700 26.640 ;
        RECT 8.100 24.840 8.600 25.340 ;
        RECT 9.800 24.840 10.300 25.340 ;
        RECT 11.500 24.840 12.000 25.340 ;
        RECT 13.200 24.840 13.700 25.340 ;
        RECT 8.100 32.640 8.600 33.140 ;
        RECT 9.800 32.640 10.300 33.140 ;
        RECT 8.100 30.040 8.600 30.540 ;
        RECT 9.800 30.040 10.300 30.540 ;
        RECT 11.500 30.040 12.000 30.540 ;
        RECT 13.200 30.040 13.700 30.540 ;
        RECT 1.300 11.840 1.800 12.340 ;
        RECT 3.000 11.840 3.500 12.340 ;
        RECT 4.700 11.840 5.200 12.340 ;
        RECT 6.400 11.840 6.900 12.340 ;
        RECT 8.100 11.840 8.600 12.340 ;
        RECT 9.800 11.840 10.300 12.340 ;
        RECT 11.500 11.840 12.000 12.340 ;
        RECT 13.200 11.840 13.700 12.340 ;
        RECT 8.100 19.640 8.600 20.140 ;
        RECT 9.800 19.640 10.300 20.140 ;
        RECT 11.500 19.640 12.000 20.140 ;
        RECT 13.200 19.640 13.700 20.140 ;
        RECT 8.100 20.940 8.600 21.440 ;
        RECT 9.800 20.940 10.300 21.440 ;
        RECT 11.500 20.940 12.000 21.440 ;
        RECT 13.200 20.940 13.700 21.440 ;
        RECT 8.100 13.140 8.600 13.640 ;
        RECT 9.800 13.140 10.300 13.640 ;
        RECT 11.500 13.140 12.000 13.640 ;
        RECT 13.200 13.140 13.700 13.640 ;
        RECT 8.100 14.440 8.600 14.940 ;
        RECT 9.800 14.440 10.300 14.940 ;
        RECT 11.500 14.440 12.000 14.940 ;
        RECT 13.200 14.440 13.700 14.940 ;
        RECT 8.100 15.740 8.600 16.240 ;
        RECT 9.800 15.740 10.300 16.240 ;
        RECT 11.500 15.740 12.000 16.240 ;
        RECT 13.200 15.740 13.700 16.240 ;
        RECT 8.100 17.040 8.600 17.540 ;
        RECT 9.800 17.040 10.300 17.540 ;
        RECT 11.500 17.040 12.000 17.540 ;
        RECT 13.200 17.040 13.700 17.540 ;
        RECT 8.100 18.340 8.600 18.840 ;
        RECT 9.800 18.340 10.300 18.840 ;
        RECT 11.500 18.340 12.000 18.840 ;
        RECT 13.200 18.340 13.700 18.840 ;
        RECT 1.300 13.140 1.800 13.640 ;
        RECT 3.000 13.140 3.500 13.640 ;
        RECT 1.300 15.740 1.800 16.240 ;
        RECT 3.000 15.740 3.500 16.240 ;
        RECT 4.700 15.740 5.200 16.240 ;
        RECT 6.400 15.740 6.900 16.240 ;
        RECT 4.700 13.140 5.200 13.640 ;
        RECT 6.400 13.140 6.900 13.640 ;
        RECT 4.700 19.640 5.200 20.140 ;
        RECT 6.400 19.640 6.900 20.140 ;
        RECT 1.300 17.040 1.800 17.540 ;
        RECT 3.000 17.040 3.500 17.540 ;
        RECT 4.700 17.040 5.200 17.540 ;
        RECT 6.400 17.040 6.900 17.540 ;
        RECT 1.300 20.940 1.800 21.440 ;
        RECT 3.000 20.940 3.500 21.440 ;
        RECT 1.300 14.440 1.800 14.940 ;
        RECT 3.000 14.440 3.500 14.940 ;
        RECT 1.300 18.340 1.800 18.840 ;
        RECT 3.000 18.340 3.500 18.840 ;
        RECT 4.700 18.340 5.200 18.840 ;
        RECT 6.400 18.340 6.900 18.840 ;
        RECT 4.700 14.440 5.200 14.940 ;
        RECT 6.400 14.440 6.900 14.940 ;
        RECT 4.700 20.940 5.200 21.440 ;
        RECT 6.400 20.940 6.900 21.440 ;
        RECT 1.300 19.640 1.800 20.140 ;
        RECT 3.000 19.640 3.500 20.140 ;
        RECT 4.700 5.340 5.200 5.840 ;
        RECT 6.400 5.340 6.900 5.840 ;
        RECT 1.300 6.640 1.800 7.140 ;
        RECT 3.000 6.640 3.500 7.140 ;
        RECT 4.700 6.640 5.200 7.140 ;
        RECT 6.400 6.640 6.900 7.140 ;
        RECT 1.300 7.940 1.800 8.440 ;
        RECT 3.000 7.940 3.500 8.440 ;
        RECT 4.700 7.940 5.200 8.440 ;
        RECT 6.400 7.940 6.900 8.440 ;
        RECT 1.300 9.240 1.800 9.740 ;
        RECT 3.000 9.240 3.500 9.740 ;
        RECT 4.700 9.240 5.200 9.740 ;
        RECT 6.400 9.240 6.900 9.740 ;
        RECT 1.300 0.140 1.800 0.640 ;
        RECT 3.000 0.140 3.500 0.640 ;
        RECT 4.700 0.140 5.200 0.640 ;
        RECT 6.400 0.140 6.900 0.640 ;
        RECT 1.300 1.440 1.800 1.940 ;
        RECT 3.000 1.440 3.500 1.940 ;
        RECT 4.700 1.440 5.200 1.940 ;
        RECT 6.400 1.440 6.900 1.940 ;
        RECT 1.300 2.740 1.800 3.240 ;
        RECT 3.000 2.740 3.500 3.240 ;
        RECT 4.700 2.740 5.200 3.240 ;
        RECT 6.400 2.740 6.900 3.240 ;
        RECT 1.300 4.040 1.800 4.540 ;
        RECT 3.000 4.040 3.500 4.540 ;
        RECT 4.700 4.040 5.200 4.540 ;
        RECT 6.400 4.040 6.900 4.540 ;
        RECT 1.300 5.340 1.800 5.840 ;
        RECT 3.000 5.340 3.500 5.840 ;
        RECT 11.500 1.440 12.000 1.940 ;
        RECT 13.200 1.440 13.700 1.940 ;
        RECT 8.100 7.940 8.600 8.440 ;
        RECT 9.800 7.940 10.300 8.440 ;
        RECT 11.500 7.940 12.000 8.440 ;
        RECT 13.200 7.940 13.700 8.440 ;
        RECT 8.100 4.040 8.600 4.540 ;
        RECT 9.800 4.040 10.300 4.540 ;
        RECT 11.500 4.040 12.000 4.540 ;
        RECT 13.200 4.040 13.700 4.540 ;
        RECT 8.100 9.240 8.600 9.740 ;
        RECT 9.800 9.240 10.300 9.740 ;
        RECT 11.500 9.240 12.000 9.740 ;
        RECT 13.200 9.240 13.700 9.740 ;
        RECT 8.100 0.140 8.600 0.640 ;
        RECT 9.800 0.140 10.300 0.640 ;
        RECT 11.500 0.140 12.000 0.640 ;
        RECT 13.200 0.140 13.700 0.640 ;
        RECT 8.100 5.340 8.600 5.840 ;
        RECT 9.800 5.340 10.300 5.840 ;
        RECT 11.500 5.340 12.000 5.840 ;
        RECT 13.200 5.340 13.700 5.840 ;
        RECT 8.100 2.740 8.600 3.240 ;
        RECT 9.800 2.740 10.300 3.240 ;
        RECT 11.500 2.740 12.000 3.240 ;
        RECT 13.200 2.740 13.700 3.240 ;
        RECT 8.100 6.640 8.600 7.140 ;
        RECT 9.800 6.640 10.300 7.140 ;
        RECT 11.500 6.640 12.000 7.140 ;
        RECT 13.200 6.640 13.700 7.140 ;
        RECT 8.100 1.440 8.600 1.940 ;
        RECT 9.800 1.440 10.300 1.940 ;
        RECT 14.900 11.840 15.400 12.340 ;
        RECT 16.600 11.840 17.100 12.340 ;
        RECT 18.300 11.840 18.800 12.340 ;
        RECT 20.000 11.840 20.500 12.340 ;
        RECT 21.700 11.840 22.200 12.340 ;
        RECT 23.400 11.840 23.900 12.340 ;
        RECT 25.100 11.840 25.600 12.340 ;
        RECT 26.800 11.840 27.300 12.340 ;
        RECT 21.700 20.940 22.200 21.440 ;
        RECT 23.400 20.940 23.900 21.440 ;
        RECT 25.100 20.940 25.600 21.440 ;
        RECT 26.800 20.940 27.300 21.440 ;
        RECT 21.700 13.140 22.200 13.640 ;
        RECT 23.400 13.140 23.900 13.640 ;
        RECT 25.100 13.140 25.600 13.640 ;
        RECT 26.800 13.140 27.300 13.640 ;
        RECT 21.700 14.440 22.200 14.940 ;
        RECT 23.400 14.440 23.900 14.940 ;
        RECT 25.100 14.440 25.600 14.940 ;
        RECT 26.800 14.440 27.300 14.940 ;
        RECT 21.700 15.740 22.200 16.240 ;
        RECT 23.400 15.740 23.900 16.240 ;
        RECT 25.100 15.740 25.600 16.240 ;
        RECT 26.800 15.740 27.300 16.240 ;
        RECT 21.700 17.040 22.200 17.540 ;
        RECT 23.400 17.040 23.900 17.540 ;
        RECT 25.100 17.040 25.600 17.540 ;
        RECT 26.800 17.040 27.300 17.540 ;
        RECT 21.700 18.340 22.200 18.840 ;
        RECT 23.400 18.340 23.900 18.840 ;
        RECT 25.100 18.340 25.600 18.840 ;
        RECT 26.800 18.340 27.300 18.840 ;
        RECT 21.700 19.640 22.200 20.140 ;
        RECT 23.400 19.640 23.900 20.140 ;
        RECT 25.100 19.640 25.600 20.140 ;
        RECT 26.800 19.640 27.300 20.140 ;
        RECT 14.900 20.940 15.400 21.440 ;
        RECT 16.600 20.940 17.100 21.440 ;
        RECT 18.300 20.940 18.800 21.440 ;
        RECT 20.000 20.940 20.500 21.440 ;
        RECT 14.900 17.040 15.400 17.540 ;
        RECT 16.600 17.040 17.100 17.540 ;
        RECT 18.300 17.040 18.800 17.540 ;
        RECT 20.000 17.040 20.500 17.540 ;
        RECT 14.900 14.440 15.400 14.940 ;
        RECT 16.600 14.440 17.100 14.940 ;
        RECT 18.300 14.440 18.800 14.940 ;
        RECT 20.000 14.440 20.500 14.940 ;
        RECT 14.900 18.340 15.400 18.840 ;
        RECT 16.600 18.340 17.100 18.840 ;
        RECT 18.300 18.340 18.800 18.840 ;
        RECT 20.000 18.340 20.500 18.840 ;
        RECT 14.900 13.140 15.400 13.640 ;
        RECT 16.600 13.140 17.100 13.640 ;
        RECT 18.300 13.140 18.800 13.640 ;
        RECT 20.000 13.140 20.500 13.640 ;
        RECT 14.900 19.640 15.400 20.140 ;
        RECT 16.600 19.640 17.100 20.140 ;
        RECT 18.300 19.640 18.800 20.140 ;
        RECT 20.000 19.640 20.500 20.140 ;
        RECT 14.900 15.740 15.400 16.240 ;
        RECT 16.600 15.740 17.100 16.240 ;
        RECT 18.300 15.740 18.800 16.240 ;
        RECT 20.000 15.740 20.500 16.240 ;
        RECT 18.300 0.140 18.800 0.640 ;
        RECT 20.000 0.140 20.500 0.640 ;
        RECT 18.300 9.240 18.800 9.740 ;
        RECT 20.000 9.240 20.500 9.740 ;
        RECT 14.900 6.640 15.400 7.140 ;
        RECT 16.600 6.640 17.100 7.140 ;
        RECT 14.900 7.940 15.400 8.440 ;
        RECT 16.600 7.940 17.100 8.440 ;
        RECT 18.300 7.940 18.800 8.440 ;
        RECT 20.000 7.940 20.500 8.440 ;
        RECT 18.300 6.640 18.800 7.140 ;
        RECT 20.000 6.640 20.500 7.140 ;
        RECT 14.900 5.340 15.400 5.840 ;
        RECT 16.600 5.340 17.100 5.840 ;
        RECT 14.900 2.740 15.400 3.240 ;
        RECT 16.600 2.740 17.100 3.240 ;
        RECT 18.300 2.740 18.800 3.240 ;
        RECT 20.000 2.740 20.500 3.240 ;
        RECT 14.900 4.040 15.400 4.540 ;
        RECT 16.600 4.040 17.100 4.540 ;
        RECT 18.300 4.040 18.800 4.540 ;
        RECT 20.000 4.040 20.500 4.540 ;
        RECT 18.300 5.340 18.800 5.840 ;
        RECT 20.000 5.340 20.500 5.840 ;
        RECT 14.900 1.440 15.400 1.940 ;
        RECT 16.600 1.440 17.100 1.940 ;
        RECT 18.300 1.440 18.800 1.940 ;
        RECT 20.000 1.440 20.500 1.940 ;
        RECT 14.900 0.140 15.400 0.640 ;
        RECT 16.600 0.140 17.100 0.640 ;
        RECT 14.900 9.240 15.400 9.740 ;
        RECT 16.600 9.240 17.100 9.740 ;
        RECT 25.100 2.740 25.600 3.240 ;
        RECT 26.800 2.740 27.300 3.240 ;
        RECT 21.700 7.940 22.200 8.440 ;
        RECT 23.400 7.940 23.900 8.440 ;
        RECT 25.100 7.940 25.600 8.440 ;
        RECT 26.800 7.940 27.300 8.440 ;
        RECT 21.700 0.140 22.200 0.640 ;
        RECT 23.400 0.140 23.900 0.640 ;
        RECT 25.100 0.140 25.600 0.640 ;
        RECT 26.800 0.140 27.300 0.640 ;
        RECT 21.700 9.240 22.200 9.740 ;
        RECT 23.400 9.240 23.900 9.740 ;
        RECT 25.100 9.240 25.600 9.740 ;
        RECT 26.800 9.240 27.300 9.740 ;
        RECT 21.700 1.440 22.200 1.940 ;
        RECT 23.400 1.440 23.900 1.940 ;
        RECT 25.100 1.440 25.600 1.940 ;
        RECT 26.800 1.440 27.300 1.940 ;
        RECT 21.700 4.040 22.200 4.540 ;
        RECT 23.400 4.040 23.900 4.540 ;
        RECT 25.100 4.040 25.600 4.540 ;
        RECT 26.800 4.040 27.300 4.540 ;
        RECT 21.700 5.340 22.200 5.840 ;
        RECT 23.400 5.340 23.900 5.840 ;
        RECT 25.100 5.340 25.600 5.840 ;
        RECT 26.800 5.340 27.300 5.840 ;
        RECT 21.700 6.640 22.200 7.140 ;
        RECT 23.400 6.640 23.900 7.140 ;
        RECT 25.100 6.640 25.600 7.140 ;
        RECT 26.800 6.640 27.300 7.140 ;
        RECT 21.700 2.740 22.200 3.240 ;
        RECT 23.400 2.740 23.900 3.240 ;
        RECT 28.500 23.540 29.000 24.040 ;
        RECT 30.200 23.540 30.700 24.040 ;
        RECT 31.900 23.540 32.400 24.040 ;
        RECT 33.600 23.540 34.100 24.040 ;
        RECT 35.300 23.540 35.800 24.040 ;
        RECT 37.000 23.540 37.500 24.040 ;
        RECT 38.700 23.540 39.200 24.040 ;
        RECT 40.400 23.540 40.900 24.040 ;
        RECT 42.100 23.540 42.600 24.040 ;
        RECT 43.800 23.540 44.300 24.040 ;
        RECT 45.500 23.540 46.000 24.040 ;
        RECT 47.200 23.540 47.700 24.040 ;
        RECT 48.900 23.540 49.400 24.040 ;
        RECT 50.600 23.540 51.100 24.040 ;
        RECT 52.300 23.540 52.800 24.040 ;
        RECT 54.000 23.540 54.500 24.040 ;
        RECT 42.100 35.240 42.600 35.740 ;
        RECT 43.800 35.240 44.300 35.740 ;
        RECT 45.500 35.240 46.000 35.740 ;
        RECT 47.200 35.240 47.700 35.740 ;
        RECT 48.900 35.240 49.400 35.740 ;
        RECT 50.600 35.240 51.100 35.740 ;
        RECT 52.300 35.240 52.800 35.740 ;
        RECT 54.000 35.240 54.500 35.740 ;
        RECT 48.900 46.940 49.400 47.440 ;
        RECT 50.600 46.940 51.100 47.440 ;
        RECT 52.300 46.940 52.800 47.440 ;
        RECT 54.000 46.940 54.500 47.440 ;
        RECT 48.900 36.540 49.400 37.040 ;
        RECT 50.600 36.540 51.100 37.040 ;
        RECT 52.300 36.540 52.800 37.040 ;
        RECT 54.000 36.540 54.500 37.040 ;
        RECT 48.900 37.840 49.400 38.340 ;
        RECT 50.600 37.840 51.100 38.340 ;
        RECT 52.300 37.840 52.800 38.340 ;
        RECT 54.000 37.840 54.500 38.340 ;
        RECT 48.900 39.140 49.400 39.640 ;
        RECT 50.600 39.140 51.100 39.640 ;
        RECT 52.300 39.140 52.800 39.640 ;
        RECT 54.000 39.140 54.500 39.640 ;
        RECT 48.900 40.440 49.400 40.940 ;
        RECT 50.600 40.440 51.100 40.940 ;
        RECT 52.300 40.440 52.800 40.940 ;
        RECT 54.000 40.440 54.500 40.940 ;
        RECT 48.900 41.740 49.400 42.240 ;
        RECT 50.600 41.740 51.100 42.240 ;
        RECT 52.300 41.740 52.800 42.240 ;
        RECT 54.000 41.740 54.500 42.240 ;
        RECT 48.900 43.040 49.400 43.540 ;
        RECT 50.600 43.040 51.100 43.540 ;
        RECT 52.300 43.040 52.800 43.540 ;
        RECT 54.000 43.040 54.500 43.540 ;
        RECT 48.900 44.340 49.400 44.840 ;
        RECT 50.600 44.340 51.100 44.840 ;
        RECT 52.300 44.340 52.800 44.840 ;
        RECT 54.000 44.340 54.500 44.840 ;
        RECT 42.100 40.440 42.600 40.940 ;
        RECT 43.800 40.440 44.300 40.940 ;
        RECT 45.500 40.440 46.000 40.940 ;
        RECT 47.200 40.440 47.700 40.940 ;
        RECT 42.100 37.840 42.600 38.340 ;
        RECT 43.800 37.840 44.300 38.340 ;
        RECT 45.500 37.840 46.000 38.340 ;
        RECT 47.200 37.840 47.700 38.340 ;
        RECT 42.100 41.740 42.600 42.240 ;
        RECT 43.800 41.740 44.300 42.240 ;
        RECT 45.500 41.740 46.000 42.240 ;
        RECT 47.200 41.740 47.700 42.240 ;
        RECT 42.100 36.540 42.600 37.040 ;
        RECT 43.800 36.540 44.300 37.040 ;
        RECT 45.500 36.540 46.000 37.040 ;
        RECT 47.200 36.540 47.700 37.040 ;
        RECT 42.100 43.040 42.600 43.540 ;
        RECT 43.800 43.040 44.300 43.540 ;
        RECT 45.500 43.040 46.000 43.540 ;
        RECT 47.200 43.040 47.700 43.540 ;
        RECT 42.100 39.140 42.600 39.640 ;
        RECT 43.800 39.140 44.300 39.640 ;
        RECT 45.500 39.140 46.000 39.640 ;
        RECT 47.200 39.140 47.700 39.640 ;
        RECT 42.100 44.340 42.600 44.840 ;
        RECT 43.800 44.340 44.300 44.840 ;
        RECT 45.500 44.340 46.000 44.840 ;
        RECT 47.200 44.340 47.700 44.840 ;
        RECT 42.100 46.940 42.600 47.440 ;
        RECT 43.800 46.940 44.300 47.440 ;
        RECT 45.500 46.940 46.000 47.440 ;
        RECT 47.200 46.940 47.700 47.440 ;
        RECT 42.100 27.440 42.600 27.940 ;
        RECT 43.800 27.440 44.300 27.940 ;
        RECT 45.500 27.440 46.000 27.940 ;
        RECT 47.200 27.440 47.700 27.940 ;
        RECT 42.100 28.740 42.600 29.240 ;
        RECT 43.800 28.740 44.300 29.240 ;
        RECT 45.500 28.740 46.000 29.240 ;
        RECT 47.200 28.740 47.700 29.240 ;
        RECT 42.100 30.040 42.600 30.540 ;
        RECT 43.800 30.040 44.300 30.540 ;
        RECT 45.500 30.040 46.000 30.540 ;
        RECT 47.200 30.040 47.700 30.540 ;
        RECT 42.100 31.340 42.600 31.840 ;
        RECT 43.800 31.340 44.300 31.840 ;
        RECT 45.500 31.340 46.000 31.840 ;
        RECT 47.200 31.340 47.700 31.840 ;
        RECT 42.100 32.640 42.600 33.140 ;
        RECT 43.800 32.640 44.300 33.140 ;
        RECT 45.500 32.640 46.000 33.140 ;
        RECT 47.200 32.640 47.700 33.140 ;
        RECT 42.100 24.840 42.600 25.340 ;
        RECT 43.800 24.840 44.300 25.340 ;
        RECT 45.500 24.840 46.000 25.340 ;
        RECT 47.200 24.840 47.700 25.340 ;
        RECT 42.100 26.140 42.600 26.640 ;
        RECT 43.800 26.140 44.300 26.640 ;
        RECT 45.500 26.140 46.000 26.640 ;
        RECT 47.200 26.140 47.700 26.640 ;
        RECT 48.900 30.040 49.400 30.540 ;
        RECT 50.600 30.040 51.100 30.540 ;
        RECT 52.300 30.040 52.800 30.540 ;
        RECT 54.000 30.040 54.500 30.540 ;
        RECT 48.900 27.440 49.400 27.940 ;
        RECT 50.600 27.440 51.100 27.940 ;
        RECT 52.300 27.440 52.800 27.940 ;
        RECT 54.000 27.440 54.500 27.940 ;
        RECT 48.900 31.340 49.400 31.840 ;
        RECT 50.600 31.340 51.100 31.840 ;
        RECT 52.300 31.340 52.800 31.840 ;
        RECT 54.000 31.340 54.500 31.840 ;
        RECT 48.900 26.140 49.400 26.640 ;
        RECT 50.600 26.140 51.100 26.640 ;
        RECT 52.300 26.140 52.800 26.640 ;
        RECT 54.000 26.140 54.500 26.640 ;
        RECT 48.900 32.640 49.400 33.140 ;
        RECT 50.600 32.640 51.100 33.140 ;
        RECT 52.300 32.640 52.800 33.140 ;
        RECT 54.000 32.640 54.500 33.140 ;
        RECT 48.900 28.740 49.400 29.240 ;
        RECT 50.600 28.740 51.100 29.240 ;
        RECT 52.300 28.740 52.800 29.240 ;
        RECT 54.000 28.740 54.500 29.240 ;
        RECT 48.900 24.840 49.400 25.340 ;
        RECT 50.600 24.840 51.100 25.340 ;
        RECT 52.300 24.840 52.800 25.340 ;
        RECT 54.000 24.840 54.500 25.340 ;
        RECT 28.500 35.240 29.000 35.740 ;
        RECT 30.200 35.240 30.700 35.740 ;
        RECT 31.900 35.240 32.400 35.740 ;
        RECT 33.600 35.240 34.100 35.740 ;
        RECT 35.300 35.240 35.800 35.740 ;
        RECT 37.000 35.240 37.500 35.740 ;
        RECT 38.700 35.240 39.200 35.740 ;
        RECT 40.400 35.240 40.900 35.740 ;
        RECT 35.300 36.540 35.800 37.040 ;
        RECT 37.000 36.540 37.500 37.040 ;
        RECT 38.700 36.540 39.200 37.040 ;
        RECT 40.400 36.540 40.900 37.040 ;
        RECT 35.300 37.840 35.800 38.340 ;
        RECT 37.000 37.840 37.500 38.340 ;
        RECT 38.700 37.840 39.200 38.340 ;
        RECT 40.400 37.840 40.900 38.340 ;
        RECT 35.300 39.140 35.800 39.640 ;
        RECT 37.000 39.140 37.500 39.640 ;
        RECT 38.700 39.140 39.200 39.640 ;
        RECT 40.400 39.140 40.900 39.640 ;
        RECT 35.300 40.440 35.800 40.940 ;
        RECT 37.000 40.440 37.500 40.940 ;
        RECT 38.700 40.440 39.200 40.940 ;
        RECT 40.400 40.440 40.900 40.940 ;
        RECT 35.300 41.740 35.800 42.240 ;
        RECT 37.000 41.740 37.500 42.240 ;
        RECT 38.700 41.740 39.200 42.240 ;
        RECT 40.400 41.740 40.900 42.240 ;
        RECT 35.300 43.040 35.800 43.540 ;
        RECT 37.000 43.040 37.500 43.540 ;
        RECT 38.700 43.040 39.200 43.540 ;
        RECT 40.400 43.040 40.900 43.540 ;
        RECT 35.300 44.340 35.800 44.840 ;
        RECT 37.000 44.340 37.500 44.840 ;
        RECT 38.700 44.340 39.200 44.840 ;
        RECT 40.400 44.340 40.900 44.840 ;
        RECT 35.300 46.940 35.800 47.440 ;
        RECT 37.000 46.940 37.500 47.440 ;
        RECT 38.700 46.940 39.200 47.440 ;
        RECT 40.400 46.940 40.900 47.440 ;
        RECT 28.500 41.740 29.000 42.240 ;
        RECT 30.200 41.740 30.700 42.240 ;
        RECT 31.900 41.740 32.400 42.240 ;
        RECT 33.600 41.740 34.100 42.240 ;
        RECT 28.500 39.140 29.000 39.640 ;
        RECT 30.200 39.140 30.700 39.640 ;
        RECT 31.900 39.140 32.400 39.640 ;
        RECT 33.600 39.140 34.100 39.640 ;
        RECT 28.500 43.040 29.000 43.540 ;
        RECT 30.200 43.040 30.700 43.540 ;
        RECT 31.900 43.040 32.400 43.540 ;
        RECT 33.600 43.040 34.100 43.540 ;
        RECT 28.500 37.840 29.000 38.340 ;
        RECT 30.200 37.840 30.700 38.340 ;
        RECT 31.900 37.840 32.400 38.340 ;
        RECT 33.600 37.840 34.100 38.340 ;
        RECT 28.500 44.340 29.000 44.840 ;
        RECT 30.200 44.340 30.700 44.840 ;
        RECT 31.900 44.340 32.400 44.840 ;
        RECT 33.600 44.340 34.100 44.840 ;
        RECT 28.500 40.440 29.000 40.940 ;
        RECT 30.200 40.440 30.700 40.940 ;
        RECT 31.900 40.440 32.400 40.940 ;
        RECT 33.600 40.440 34.100 40.940 ;
        RECT 28.500 46.940 29.000 47.440 ;
        RECT 30.200 46.940 30.700 47.440 ;
        RECT 31.900 46.940 32.400 47.440 ;
        RECT 33.600 46.940 34.100 47.440 ;
        RECT 28.500 36.540 29.000 37.040 ;
        RECT 30.200 36.540 30.700 37.040 ;
        RECT 31.900 36.540 32.400 37.040 ;
        RECT 33.600 36.540 34.100 37.040 ;
        RECT 28.500 30.040 29.000 30.540 ;
        RECT 30.200 30.040 30.700 30.540 ;
        RECT 31.900 30.040 32.400 30.540 ;
        RECT 33.600 30.040 34.100 30.540 ;
        RECT 28.500 28.740 29.000 29.240 ;
        RECT 30.200 28.740 30.700 29.240 ;
        RECT 31.900 28.740 32.400 29.240 ;
        RECT 33.600 28.740 34.100 29.240 ;
        RECT 28.500 32.640 29.000 33.140 ;
        RECT 30.200 32.640 30.700 33.140 ;
        RECT 31.900 32.640 32.400 33.140 ;
        RECT 33.600 32.640 34.100 33.140 ;
        RECT 28.500 31.340 29.000 31.840 ;
        RECT 30.200 31.340 30.700 31.840 ;
        RECT 31.900 31.340 32.400 31.840 ;
        RECT 33.600 31.340 34.100 31.840 ;
        RECT 28.500 26.140 29.000 26.640 ;
        RECT 30.200 26.140 30.700 26.640 ;
        RECT 31.900 26.140 32.400 26.640 ;
        RECT 33.600 26.140 34.100 26.640 ;
        RECT 28.500 24.840 29.000 25.340 ;
        RECT 30.200 24.840 30.700 25.340 ;
        RECT 31.900 24.840 32.400 25.340 ;
        RECT 33.600 24.840 34.100 25.340 ;
        RECT 28.500 27.440 29.000 27.940 ;
        RECT 30.200 27.440 30.700 27.940 ;
        RECT 31.900 27.440 32.400 27.940 ;
        RECT 33.600 27.440 34.100 27.940 ;
        RECT 35.300 31.340 35.800 31.840 ;
        RECT 37.000 31.340 37.500 31.840 ;
        RECT 38.700 31.340 39.200 31.840 ;
        RECT 40.400 31.340 40.900 31.840 ;
        RECT 35.300 24.840 35.800 25.340 ;
        RECT 37.000 24.840 37.500 25.340 ;
        RECT 38.700 24.840 39.200 25.340 ;
        RECT 40.400 24.840 40.900 25.340 ;
        RECT 35.300 32.640 35.800 33.140 ;
        RECT 37.000 32.640 37.500 33.140 ;
        RECT 38.700 32.640 39.200 33.140 ;
        RECT 40.400 32.640 40.900 33.140 ;
        RECT 35.300 26.140 35.800 26.640 ;
        RECT 37.000 26.140 37.500 26.640 ;
        RECT 38.700 26.140 39.200 26.640 ;
        RECT 40.400 26.140 40.900 26.640 ;
        RECT 35.300 28.740 35.800 29.240 ;
        RECT 37.000 28.740 37.500 29.240 ;
        RECT 38.700 28.740 39.200 29.240 ;
        RECT 40.400 28.740 40.900 29.240 ;
        RECT 35.300 27.440 35.800 27.940 ;
        RECT 37.000 27.440 37.500 27.940 ;
        RECT 38.700 27.440 39.200 27.940 ;
        RECT 40.400 27.440 40.900 27.940 ;
        RECT 35.300 30.040 35.800 30.540 ;
        RECT 37.000 30.040 37.500 30.540 ;
        RECT 38.700 30.040 39.200 30.540 ;
        RECT 40.400 30.040 40.900 30.540 ;
        RECT 28.500 11.840 29.000 12.340 ;
        RECT 30.200 11.840 30.700 12.340 ;
        RECT 31.900 11.840 32.400 12.340 ;
        RECT 33.600 11.840 34.100 12.340 ;
        RECT 35.300 11.840 35.800 12.340 ;
        RECT 37.000 11.840 37.500 12.340 ;
        RECT 38.700 11.840 39.200 12.340 ;
        RECT 40.400 11.840 40.900 12.340 ;
        RECT 38.700 18.340 39.200 18.840 ;
        RECT 40.400 18.340 40.900 18.840 ;
        RECT 38.700 13.140 39.200 13.640 ;
        RECT 40.400 13.140 40.900 13.640 ;
        RECT 35.300 14.440 35.800 14.940 ;
        RECT 37.000 14.440 37.500 14.940 ;
        RECT 38.700 14.440 39.200 14.940 ;
        RECT 40.400 14.440 40.900 14.940 ;
        RECT 35.300 15.740 35.800 16.240 ;
        RECT 37.000 15.740 37.500 16.240 ;
        RECT 38.700 15.740 39.200 16.240 ;
        RECT 40.400 15.740 40.900 16.240 ;
        RECT 35.300 19.640 35.800 20.140 ;
        RECT 37.000 19.640 37.500 20.140 ;
        RECT 38.700 19.640 39.200 20.140 ;
        RECT 40.400 19.640 40.900 20.140 ;
        RECT 35.300 13.140 35.800 13.640 ;
        RECT 37.000 13.140 37.500 13.640 ;
        RECT 35.300 17.040 35.800 17.540 ;
        RECT 37.000 17.040 37.500 17.540 ;
        RECT 38.700 17.040 39.200 17.540 ;
        RECT 40.400 17.040 40.900 17.540 ;
        RECT 35.300 18.340 35.800 18.840 ;
        RECT 37.000 18.340 37.500 18.840 ;
        RECT 35.300 20.940 35.800 21.440 ;
        RECT 37.000 20.940 37.500 21.440 ;
        RECT 38.700 20.940 39.200 21.440 ;
        RECT 40.400 20.940 40.900 21.440 ;
        RECT 28.500 14.440 29.000 14.940 ;
        RECT 30.200 14.440 30.700 14.940 ;
        RECT 28.500 17.040 29.000 17.540 ;
        RECT 30.200 17.040 30.700 17.540 ;
        RECT 31.900 17.040 32.400 17.540 ;
        RECT 33.600 17.040 34.100 17.540 ;
        RECT 31.900 14.440 32.400 14.940 ;
        RECT 33.600 14.440 34.100 14.940 ;
        RECT 28.500 19.640 29.000 20.140 ;
        RECT 30.200 19.640 30.700 20.140 ;
        RECT 31.900 19.640 32.400 20.140 ;
        RECT 33.600 19.640 34.100 20.140 ;
        RECT 28.500 20.940 29.000 21.440 ;
        RECT 30.200 20.940 30.700 21.440 ;
        RECT 31.900 20.940 32.400 21.440 ;
        RECT 33.600 20.940 34.100 21.440 ;
        RECT 31.900 18.340 32.400 18.840 ;
        RECT 33.600 18.340 34.100 18.840 ;
        RECT 28.500 18.340 29.000 18.840 ;
        RECT 30.200 18.340 30.700 18.840 ;
        RECT 28.500 13.140 29.000 13.640 ;
        RECT 30.200 13.140 30.700 13.640 ;
        RECT 31.900 13.140 32.400 13.640 ;
        RECT 33.600 13.140 34.100 13.640 ;
        RECT 28.500 15.740 29.000 16.240 ;
        RECT 30.200 15.740 30.700 16.240 ;
        RECT 31.900 15.740 32.400 16.240 ;
        RECT 33.600 15.740 34.100 16.240 ;
        RECT 28.500 9.240 29.000 9.740 ;
        RECT 30.200 9.240 30.700 9.740 ;
        RECT 31.900 9.240 32.400 9.740 ;
        RECT 33.600 9.240 34.100 9.740 ;
        RECT 31.900 2.740 32.400 3.240 ;
        RECT 33.600 2.740 34.100 3.240 ;
        RECT 31.900 0.140 32.400 0.640 ;
        RECT 33.600 0.140 34.100 0.640 ;
        RECT 28.500 7.940 29.000 8.440 ;
        RECT 30.200 7.940 30.700 8.440 ;
        RECT 31.900 5.340 32.400 5.840 ;
        RECT 33.600 5.340 34.100 5.840 ;
        RECT 28.500 2.740 29.000 3.240 ;
        RECT 30.200 2.740 30.700 3.240 ;
        RECT 28.500 6.640 29.000 7.140 ;
        RECT 30.200 6.640 30.700 7.140 ;
        RECT 28.500 1.440 29.000 1.940 ;
        RECT 30.200 1.440 30.700 1.940 ;
        RECT 31.900 7.940 32.400 8.440 ;
        RECT 33.600 7.940 34.100 8.440 ;
        RECT 28.500 5.340 29.000 5.840 ;
        RECT 30.200 5.340 30.700 5.840 ;
        RECT 28.500 4.040 29.000 4.540 ;
        RECT 30.200 4.040 30.700 4.540 ;
        RECT 31.900 4.040 32.400 4.540 ;
        RECT 33.600 4.040 34.100 4.540 ;
        RECT 31.900 1.440 32.400 1.940 ;
        RECT 33.600 1.440 34.100 1.940 ;
        RECT 31.900 6.640 32.400 7.140 ;
        RECT 33.600 6.640 34.100 7.140 ;
        RECT 28.500 0.140 29.000 0.640 ;
        RECT 30.200 0.140 30.700 0.640 ;
        RECT 38.700 1.440 39.200 1.940 ;
        RECT 40.400 1.440 40.900 1.940 ;
        RECT 35.300 0.140 35.800 0.640 ;
        RECT 37.000 0.140 37.500 0.640 ;
        RECT 38.700 5.340 39.200 5.840 ;
        RECT 40.400 5.340 40.900 5.840 ;
        RECT 38.700 0.140 39.200 0.640 ;
        RECT 40.400 0.140 40.900 0.640 ;
        RECT 35.300 4.040 35.800 4.540 ;
        RECT 37.000 4.040 37.500 4.540 ;
        RECT 38.700 4.040 39.200 4.540 ;
        RECT 40.400 4.040 40.900 4.540 ;
        RECT 35.300 5.340 35.800 5.840 ;
        RECT 37.000 5.340 37.500 5.840 ;
        RECT 35.300 9.240 35.800 9.740 ;
        RECT 37.000 9.240 37.500 9.740 ;
        RECT 35.300 7.940 35.800 8.440 ;
        RECT 37.000 7.940 37.500 8.440 ;
        RECT 38.700 7.940 39.200 8.440 ;
        RECT 40.400 7.940 40.900 8.440 ;
        RECT 38.700 9.240 39.200 9.740 ;
        RECT 40.400 9.240 40.900 9.740 ;
        RECT 35.300 6.640 35.800 7.140 ;
        RECT 37.000 6.640 37.500 7.140 ;
        RECT 38.700 6.640 39.200 7.140 ;
        RECT 40.400 6.640 40.900 7.140 ;
        RECT 35.300 1.440 35.800 1.940 ;
        RECT 37.000 1.440 37.500 1.940 ;
        RECT 35.300 2.740 35.800 3.240 ;
        RECT 37.000 2.740 37.500 3.240 ;
        RECT 38.700 2.740 39.200 3.240 ;
        RECT 40.400 2.740 40.900 3.240 ;
        RECT 42.100 11.840 42.600 12.340 ;
        RECT 43.800 11.840 44.300 12.340 ;
        RECT 45.500 11.840 46.000 12.340 ;
        RECT 47.200 11.840 47.700 12.340 ;
        RECT 48.900 11.840 49.400 12.340 ;
        RECT 50.600 11.840 51.100 12.340 ;
        RECT 52.300 11.840 52.800 12.340 ;
        RECT 54.000 11.840 54.500 12.340 ;
        RECT 48.900 15.740 49.400 16.240 ;
        RECT 50.600 15.740 51.100 16.240 ;
        RECT 52.300 15.740 52.800 16.240 ;
        RECT 54.000 15.740 54.500 16.240 ;
        RECT 48.900 19.640 49.400 20.140 ;
        RECT 50.600 19.640 51.100 20.140 ;
        RECT 52.300 19.640 52.800 20.140 ;
        RECT 54.000 19.640 54.500 20.140 ;
        RECT 48.900 13.140 49.400 13.640 ;
        RECT 50.600 13.140 51.100 13.640 ;
        RECT 52.300 13.140 52.800 13.640 ;
        RECT 54.000 13.140 54.500 13.640 ;
        RECT 48.900 18.340 49.400 18.840 ;
        RECT 50.600 18.340 51.100 18.840 ;
        RECT 52.300 18.340 52.800 18.840 ;
        RECT 54.000 18.340 54.500 18.840 ;
        RECT 48.900 20.940 49.400 21.440 ;
        RECT 50.600 20.940 51.100 21.440 ;
        RECT 52.300 20.940 52.800 21.440 ;
        RECT 54.000 20.940 54.500 21.440 ;
        RECT 48.900 17.040 49.400 17.540 ;
        RECT 50.600 17.040 51.100 17.540 ;
        RECT 52.300 17.040 52.800 17.540 ;
        RECT 54.000 17.040 54.500 17.540 ;
        RECT 48.900 14.440 49.400 14.940 ;
        RECT 50.600 14.440 51.100 14.940 ;
        RECT 52.300 14.440 52.800 14.940 ;
        RECT 54.000 14.440 54.500 14.940 ;
        RECT 42.100 15.740 42.600 16.240 ;
        RECT 43.800 15.740 44.300 16.240 ;
        RECT 45.500 15.740 46.000 16.240 ;
        RECT 47.200 15.740 47.700 16.240 ;
        RECT 42.100 18.340 42.600 18.840 ;
        RECT 43.800 18.340 44.300 18.840 ;
        RECT 45.500 18.340 46.000 18.840 ;
        RECT 47.200 18.340 47.700 18.840 ;
        RECT 42.100 14.440 42.600 14.940 ;
        RECT 43.800 14.440 44.300 14.940 ;
        RECT 45.500 14.440 46.000 14.940 ;
        RECT 47.200 14.440 47.700 14.940 ;
        RECT 42.100 20.940 42.600 21.440 ;
        RECT 43.800 20.940 44.300 21.440 ;
        RECT 45.500 20.940 46.000 21.440 ;
        RECT 47.200 20.940 47.700 21.440 ;
        RECT 42.100 19.640 42.600 20.140 ;
        RECT 43.800 19.640 44.300 20.140 ;
        RECT 45.500 19.640 46.000 20.140 ;
        RECT 47.200 19.640 47.700 20.140 ;
        RECT 42.100 17.040 42.600 17.540 ;
        RECT 43.800 17.040 44.300 17.540 ;
        RECT 45.500 17.040 46.000 17.540 ;
        RECT 47.200 17.040 47.700 17.540 ;
        RECT 42.100 13.140 42.600 13.640 ;
        RECT 43.800 13.140 44.300 13.640 ;
        RECT 45.500 13.140 46.000 13.640 ;
        RECT 47.200 13.140 47.700 13.640 ;
        RECT 45.500 1.440 46.000 1.940 ;
        RECT 47.200 1.440 47.700 1.940 ;
        RECT 45.500 5.340 46.000 5.840 ;
        RECT 47.200 5.340 47.700 5.840 ;
        RECT 42.100 7.940 42.600 8.440 ;
        RECT 43.800 7.940 44.300 8.440 ;
        RECT 45.500 7.940 46.000 8.440 ;
        RECT 47.200 7.940 47.700 8.440 ;
        RECT 42.100 2.740 42.600 3.240 ;
        RECT 43.800 2.740 44.300 3.240 ;
        RECT 45.500 2.740 46.000 3.240 ;
        RECT 47.200 2.740 47.700 3.240 ;
        RECT 42.100 9.240 42.600 9.740 ;
        RECT 43.800 9.240 44.300 9.740 ;
        RECT 45.500 9.240 46.000 9.740 ;
        RECT 47.200 9.240 47.700 9.740 ;
        RECT 42.100 4.040 42.600 4.540 ;
        RECT 43.800 4.040 44.300 4.540 ;
        RECT 42.100 6.640 42.600 7.140 ;
        RECT 43.800 6.640 44.300 7.140 ;
        RECT 45.500 6.640 46.000 7.140 ;
        RECT 47.200 6.640 47.700 7.140 ;
        RECT 45.500 4.040 46.000 4.540 ;
        RECT 47.200 4.040 47.700 4.540 ;
        RECT 45.500 0.140 46.000 0.640 ;
        RECT 47.200 0.140 47.700 0.640 ;
        RECT 42.100 5.340 42.600 5.840 ;
        RECT 43.800 5.340 44.300 5.840 ;
        RECT 42.100 1.440 42.600 1.940 ;
        RECT 43.800 1.440 44.300 1.940 ;
        RECT 42.100 0.140 42.600 0.640 ;
        RECT 43.800 0.140 44.300 0.640 ;
        RECT 52.300 2.740 52.800 3.240 ;
        RECT 54.000 2.740 54.500 3.240 ;
        RECT 48.900 5.340 49.400 5.840 ;
        RECT 50.600 5.340 51.100 5.840 ;
        RECT 52.300 5.340 52.800 5.840 ;
        RECT 54.000 5.340 54.500 5.840 ;
        RECT 48.900 9.240 49.400 9.740 ;
        RECT 50.600 9.240 51.100 9.740 ;
        RECT 52.300 9.240 52.800 9.740 ;
        RECT 54.000 9.240 54.500 9.740 ;
        RECT 48.900 4.040 49.400 4.540 ;
        RECT 50.600 4.040 51.100 4.540 ;
        RECT 52.300 4.040 52.800 4.540 ;
        RECT 54.000 4.040 54.500 4.540 ;
        RECT 48.900 7.940 49.400 8.440 ;
        RECT 50.600 7.940 51.100 8.440 ;
        RECT 52.300 7.940 52.800 8.440 ;
        RECT 54.000 7.940 54.500 8.440 ;
        RECT 48.900 6.640 49.400 7.140 ;
        RECT 50.600 6.640 51.100 7.140 ;
        RECT 52.300 6.640 52.800 7.140 ;
        RECT 54.000 6.640 54.500 7.140 ;
        RECT 48.900 0.140 49.400 0.640 ;
        RECT 50.600 0.140 51.100 0.640 ;
        RECT 52.300 0.140 52.800 0.640 ;
        RECT 54.000 0.140 54.500 0.640 ;
        RECT 48.900 1.440 49.400 1.940 ;
        RECT 50.600 1.440 51.100 1.940 ;
        RECT 52.300 1.440 52.800 1.940 ;
        RECT 54.000 1.440 54.500 1.940 ;
        RECT 48.900 2.740 49.400 3.240 ;
        RECT 50.600 2.740 51.100 3.240 ;
      LAYER met4 ;
        RECT 27.200 0.140 27.300 0.640 ;
        RECT 27.200 1.440 27.300 1.940 ;
        RECT 27.200 2.740 27.300 3.240 ;
        RECT 27.200 4.040 27.300 4.540 ;
        RECT 27.200 5.340 27.300 5.840 ;
        RECT 27.200 6.640 27.300 7.140 ;
        RECT 27.200 7.940 27.300 8.440 ;
        RECT 27.200 9.240 27.300 9.740 ;
        RECT 27.200 11.840 27.300 12.340 ;
        RECT 27.200 13.140 27.300 13.640 ;
        RECT 27.200 14.440 27.300 14.940 ;
        RECT 27.200 15.740 27.300 16.240 ;
        RECT 27.200 17.040 27.300 17.540 ;
        RECT 27.200 18.340 27.300 18.840 ;
        RECT 27.200 19.640 27.300 20.140 ;
        RECT 27.200 20.940 27.300 21.440 ;
        RECT 27.200 23.540 27.300 24.040 ;
        RECT 27.200 24.840 27.300 25.340 ;
        RECT 27.200 26.140 27.300 26.640 ;
        RECT 27.200 27.440 27.300 27.940 ;
        RECT 27.200 28.740 27.300 29.240 ;
        RECT 27.200 30.040 27.300 30.540 ;
        RECT 27.200 31.340 27.300 31.840 ;
        RECT 27.200 32.640 27.300 33.140 ;
        RECT 27.200 35.240 27.300 35.740 ;
        RECT 27.200 36.540 27.300 37.040 ;
        RECT 27.200 37.840 27.300 38.340 ;
        RECT 27.200 39.140 27.300 39.640 ;
        RECT 27.200 40.440 27.300 40.940 ;
        RECT 27.200 41.740 27.300 42.240 ;
        RECT 27.200 43.040 27.300 43.540 ;
        RECT 27.200 44.340 27.300 44.840 ;
        RECT 27.200 46.940 27.300 47.440 ;
        RECT 27.200 48.240 27.300 48.740 ;
        RECT 27.200 49.540 27.300 50.040 ;
        RECT 27.200 50.840 27.300 51.340 ;
        RECT 27.200 52.140 27.300 52.640 ;
        RECT 27.200 53.440 27.300 53.940 ;
        RECT 27.200 54.740 27.300 55.240 ;
        RECT 27.200 56.040 27.300 56.540 ;
        RECT 27.200 58.640 27.300 59.140 ;
        RECT 27.200 59.940 27.300 60.440 ;
        RECT 27.200 61.240 27.300 61.740 ;
        RECT 27.200 62.540 27.300 63.040 ;
        RECT 27.200 63.840 27.300 64.340 ;
        RECT 27.200 65.140 27.300 65.640 ;
        RECT 27.200 66.440 27.300 66.940 ;
        RECT 27.200 67.740 27.300 68.240 ;
        RECT 27.200 70.340 27.300 70.840 ;
        RECT 27.200 71.640 27.300 72.140 ;
        RECT 27.200 72.940 27.300 73.440 ;
        RECT 27.200 74.240 27.300 74.740 ;
        RECT 27.200 75.540 27.300 76.040 ;
        RECT 27.200 76.840 27.300 77.340 ;
        RECT 27.200 78.140 27.300 78.640 ;
        RECT 27.200 79.440 27.300 79.940 ;
        RECT 27.200 82.040 27.300 82.540 ;
        RECT 27.200 83.340 27.300 83.840 ;
        RECT 27.200 84.640 27.300 85.140 ;
        RECT 27.200 85.940 27.300 86.440 ;
        RECT 27.200 87.240 27.300 87.740 ;
        RECT 27.200 88.540 27.300 89.040 ;
        RECT 27.200 89.840 27.300 90.340 ;
        RECT 27.200 91.140 27.300 91.640 ;
        RECT 26.800 92.820 27.300 93.320 ;
        RECT 0.000 93.680 54.500 94.220 ;
        RECT 0.000 94.530 54.500 95.070 ;
        RECT 40.800 49.540 40.900 50.040 ;
        RECT 40.800 50.840 40.900 51.340 ;
        RECT 40.800 52.140 40.900 52.640 ;
        RECT 40.800 53.440 40.900 53.940 ;
        RECT 40.800 54.740 40.900 55.240 ;
        RECT 40.800 56.040 40.900 56.540 ;
        RECT 40.800 58.640 40.900 59.140 ;
        RECT 40.800 59.940 40.900 60.440 ;
        RECT 40.800 61.240 40.900 61.740 ;
        RECT 40.800 62.540 40.900 63.040 ;
        RECT 40.800 63.840 40.900 64.340 ;
        RECT 40.800 65.140 40.900 65.640 ;
        RECT 40.800 66.440 40.900 66.940 ;
        RECT 40.800 67.740 40.900 68.240 ;
        RECT 40.800 70.340 40.900 70.840 ;
        RECT 40.800 48.240 40.900 48.740 ;
        RECT 40.800 71.640 40.900 72.140 ;
        RECT 40.800 72.940 40.900 73.440 ;
        RECT 40.800 74.240 40.900 74.740 ;
        RECT 40.800 75.540 40.900 76.040 ;
        RECT 40.800 76.840 40.900 77.340 ;
        RECT 40.800 78.140 40.900 78.640 ;
        RECT 40.800 79.440 40.900 79.940 ;
        RECT 40.800 82.040 40.900 82.540 ;
        RECT 40.800 83.340 40.900 83.840 ;
        RECT 40.800 84.640 40.900 85.140 ;
        RECT 40.800 85.940 40.900 86.440 ;
        RECT 40.800 87.240 40.900 87.740 ;
        RECT 40.800 88.540 40.900 89.040 ;
        RECT 40.800 89.840 40.900 90.340 ;
        RECT 40.800 91.140 40.900 91.640 ;
        RECT 40.400 92.820 40.900 93.320 ;
        RECT 47.600 72.940 47.700 73.440 ;
        RECT 47.600 74.240 47.700 74.740 ;
        RECT 47.600 75.540 47.700 76.040 ;
        RECT 47.600 76.840 47.700 77.340 ;
        RECT 47.600 78.140 47.700 78.640 ;
        RECT 47.600 79.440 47.700 79.940 ;
        RECT 47.600 82.040 47.700 82.540 ;
        RECT 47.600 71.640 47.700 72.140 ;
        RECT 47.600 83.340 47.700 83.840 ;
        RECT 47.600 84.640 47.700 85.140 ;
        RECT 47.600 85.940 47.700 86.440 ;
        RECT 47.600 87.240 47.700 87.740 ;
        RECT 47.600 88.540 47.700 89.040 ;
        RECT 47.600 89.840 47.700 90.340 ;
        RECT 47.600 91.140 47.700 91.640 ;
        RECT 47.200 92.820 47.700 93.320 ;
        RECT 54.400 83.340 54.500 83.840 ;
        RECT 48.900 83.340 49.000 83.840 ;
        RECT 48.900 84.640 49.000 85.140 ;
        RECT 49.300 84.640 49.400 85.140 ;
        RECT 50.600 84.640 50.700 85.140 ;
        RECT 51.000 84.640 51.100 85.140 ;
        RECT 52.300 84.640 52.400 85.140 ;
        RECT 52.700 84.640 52.800 85.140 ;
        RECT 54.000 84.640 54.100 85.140 ;
        RECT 54.400 84.640 54.500 85.140 ;
        RECT 49.300 83.340 49.400 83.840 ;
        RECT 48.900 85.940 49.000 86.440 ;
        RECT 49.300 85.940 49.400 86.440 ;
        RECT 50.600 85.940 50.700 86.440 ;
        RECT 51.000 85.940 51.100 86.440 ;
        RECT 52.300 85.940 52.400 86.440 ;
        RECT 52.700 85.940 52.800 86.440 ;
        RECT 54.000 85.940 54.100 86.440 ;
        RECT 54.400 85.940 54.500 86.440 ;
        RECT 50.600 83.340 50.700 83.840 ;
        RECT 48.900 87.240 49.000 87.740 ;
        RECT 49.300 87.240 49.400 87.740 ;
        RECT 50.600 87.240 50.700 87.740 ;
        RECT 51.000 87.240 51.100 87.740 ;
        RECT 52.300 87.240 52.400 87.740 ;
        RECT 52.700 87.240 52.800 87.740 ;
        RECT 54.000 87.240 54.100 87.740 ;
        RECT 54.400 87.240 54.500 87.740 ;
        RECT 51.000 83.340 51.100 83.840 ;
        RECT 48.900 88.540 49.000 89.040 ;
        RECT 49.300 88.540 49.400 89.040 ;
        RECT 50.600 88.540 50.700 89.040 ;
        RECT 51.000 88.540 51.100 89.040 ;
        RECT 52.300 88.540 52.400 89.040 ;
        RECT 52.700 88.540 52.800 89.040 ;
        RECT 54.000 88.540 54.100 89.040 ;
        RECT 54.400 88.540 54.500 89.040 ;
        RECT 52.300 83.340 52.400 83.840 ;
        RECT 48.900 89.840 49.000 90.340 ;
        RECT 49.300 89.840 49.400 90.340 ;
        RECT 50.600 89.840 50.700 90.340 ;
        RECT 51.000 89.840 51.100 90.340 ;
        RECT 52.300 89.840 52.400 90.340 ;
        RECT 52.700 89.840 52.800 90.340 ;
        RECT 54.000 89.840 54.100 90.340 ;
        RECT 54.400 89.840 54.500 90.340 ;
        RECT 52.700 83.340 52.800 83.840 ;
        RECT 48.900 91.140 49.000 91.640 ;
        RECT 49.300 91.140 49.400 91.640 ;
        RECT 50.600 91.140 50.700 91.640 ;
        RECT 51.000 91.140 51.100 91.640 ;
        RECT 52.300 91.140 52.400 91.640 ;
        RECT 52.700 91.140 52.800 91.640 ;
        RECT 54.000 91.140 54.100 91.640 ;
        RECT 54.400 91.140 54.500 91.640 ;
        RECT 54.000 83.340 54.100 83.840 ;
        RECT 48.900 92.820 49.400 93.320 ;
        RECT 50.600 92.820 51.100 93.320 ;
        RECT 52.300 92.820 52.800 93.320 ;
        RECT 54.000 92.820 54.500 93.320 ;
        RECT 45.500 88.540 45.600 89.040 ;
        RECT 45.900 88.540 46.000 89.040 ;
        RECT 47.200 88.540 47.300 89.040 ;
        RECT 45.500 85.940 45.600 86.440 ;
        RECT 45.900 85.940 46.000 86.440 ;
        RECT 47.200 85.940 47.300 86.440 ;
        RECT 43.800 84.640 43.900 85.140 ;
        RECT 44.200 84.640 44.300 85.140 ;
        RECT 45.500 84.640 45.600 85.140 ;
        RECT 45.900 84.640 46.000 85.140 ;
        RECT 47.200 84.640 47.300 85.140 ;
        RECT 43.800 83.340 43.900 83.840 ;
        RECT 42.100 89.840 42.200 90.340 ;
        RECT 42.500 89.840 42.600 90.340 ;
        RECT 43.800 89.840 43.900 90.340 ;
        RECT 44.200 89.840 44.300 90.340 ;
        RECT 45.500 89.840 45.600 90.340 ;
        RECT 45.900 89.840 46.000 90.340 ;
        RECT 47.200 89.840 47.300 90.340 ;
        RECT 44.200 83.340 44.300 83.840 ;
        RECT 45.500 83.340 45.600 83.840 ;
        RECT 45.900 83.340 46.000 83.840 ;
        RECT 42.100 87.240 42.200 87.740 ;
        RECT 42.500 87.240 42.600 87.740 ;
        RECT 43.800 87.240 43.900 87.740 ;
        RECT 44.200 87.240 44.300 87.740 ;
        RECT 45.500 87.240 45.600 87.740 ;
        RECT 45.900 87.240 46.000 87.740 ;
        RECT 42.100 91.140 42.200 91.640 ;
        RECT 42.500 91.140 42.600 91.640 ;
        RECT 43.800 91.140 43.900 91.640 ;
        RECT 44.200 91.140 44.300 91.640 ;
        RECT 45.500 91.140 45.600 91.640 ;
        RECT 45.900 91.140 46.000 91.640 ;
        RECT 47.200 91.140 47.300 91.640 ;
        RECT 47.200 87.240 47.300 87.740 ;
        RECT 47.200 83.340 47.300 83.840 ;
        RECT 42.100 83.340 42.200 83.840 ;
        RECT 42.500 83.340 42.600 83.840 ;
        RECT 42.100 84.640 42.200 85.140 ;
        RECT 42.500 84.640 42.600 85.140 ;
        RECT 42.100 85.940 42.200 86.440 ;
        RECT 42.500 85.940 42.600 86.440 ;
        RECT 43.800 85.940 43.900 86.440 ;
        RECT 42.100 92.820 42.600 93.320 ;
        RECT 43.800 92.820 44.300 93.320 ;
        RECT 45.500 92.820 46.000 93.320 ;
        RECT 44.200 85.940 44.300 86.440 ;
        RECT 42.100 88.540 42.200 89.040 ;
        RECT 42.500 88.540 42.600 89.040 ;
        RECT 43.800 88.540 43.900 89.040 ;
        RECT 44.200 88.540 44.300 89.040 ;
        RECT 47.200 74.240 47.300 74.740 ;
        RECT 42.100 72.940 42.200 73.440 ;
        RECT 43.800 71.640 43.900 72.140 ;
        RECT 42.100 75.540 42.200 76.040 ;
        RECT 42.500 75.540 42.600 76.040 ;
        RECT 43.800 75.540 43.900 76.040 ;
        RECT 44.200 75.540 44.300 76.040 ;
        RECT 45.500 75.540 45.600 76.040 ;
        RECT 45.900 75.540 46.000 76.040 ;
        RECT 47.200 75.540 47.300 76.040 ;
        RECT 42.500 72.940 42.600 73.440 ;
        RECT 44.200 71.640 44.300 72.140 ;
        RECT 42.100 76.840 42.200 77.340 ;
        RECT 42.500 76.840 42.600 77.340 ;
        RECT 43.800 76.840 43.900 77.340 ;
        RECT 44.200 76.840 44.300 77.340 ;
        RECT 45.500 76.840 45.600 77.340 ;
        RECT 45.900 76.840 46.000 77.340 ;
        RECT 47.200 76.840 47.300 77.340 ;
        RECT 43.800 72.940 43.900 73.440 ;
        RECT 45.500 71.640 45.600 72.140 ;
        RECT 42.100 78.140 42.200 78.640 ;
        RECT 42.500 78.140 42.600 78.640 ;
        RECT 43.800 78.140 43.900 78.640 ;
        RECT 44.200 78.140 44.300 78.640 ;
        RECT 45.500 78.140 45.600 78.640 ;
        RECT 45.900 78.140 46.000 78.640 ;
        RECT 47.200 78.140 47.300 78.640 ;
        RECT 44.200 72.940 44.300 73.440 ;
        RECT 45.900 71.640 46.000 72.140 ;
        RECT 42.100 79.440 42.200 79.940 ;
        RECT 42.500 79.440 42.600 79.940 ;
        RECT 43.800 79.440 43.900 79.940 ;
        RECT 44.200 79.440 44.300 79.940 ;
        RECT 45.500 79.440 45.600 79.940 ;
        RECT 45.900 79.440 46.000 79.940 ;
        RECT 47.200 79.440 47.300 79.940 ;
        RECT 45.500 72.940 45.600 73.440 ;
        RECT 47.200 71.640 47.300 72.140 ;
        RECT 42.100 82.040 42.200 82.540 ;
        RECT 42.500 82.040 42.600 82.540 ;
        RECT 43.800 82.040 43.900 82.540 ;
        RECT 44.200 82.040 44.300 82.540 ;
        RECT 45.500 82.040 45.600 82.540 ;
        RECT 45.900 82.040 46.000 82.540 ;
        RECT 47.200 82.040 47.300 82.540 ;
        RECT 45.900 72.940 46.000 73.440 ;
        RECT 47.200 72.940 47.300 73.440 ;
        RECT 42.100 71.640 42.200 72.140 ;
        RECT 42.500 71.640 42.600 72.140 ;
        RECT 42.100 74.240 42.200 74.740 ;
        RECT 42.500 74.240 42.600 74.740 ;
        RECT 43.800 74.240 43.900 74.740 ;
        RECT 44.200 74.240 44.300 74.740 ;
        RECT 45.500 74.240 45.600 74.740 ;
        RECT 45.900 74.240 46.000 74.740 ;
        RECT 54.000 76.840 54.100 77.340 ;
        RECT 54.400 76.840 54.500 77.340 ;
        RECT 48.900 72.940 49.000 73.440 ;
        RECT 49.300 72.940 49.400 73.440 ;
        RECT 51.000 71.640 51.100 72.140 ;
        RECT 50.600 72.940 50.700 73.440 ;
        RECT 51.000 72.940 51.100 73.440 ;
        RECT 52.300 72.940 52.400 73.440 ;
        RECT 52.700 72.940 52.800 73.440 ;
        RECT 54.000 72.940 54.100 73.440 ;
        RECT 54.400 72.940 54.500 73.440 ;
        RECT 48.900 75.540 49.000 76.040 ;
        RECT 48.900 78.140 49.000 78.640 ;
        RECT 49.300 78.140 49.400 78.640 ;
        RECT 48.900 71.640 49.000 72.140 ;
        RECT 50.600 78.140 50.700 78.640 ;
        RECT 51.000 78.140 51.100 78.640 ;
        RECT 52.300 78.140 52.400 78.640 ;
        RECT 52.700 78.140 52.800 78.640 ;
        RECT 54.000 78.140 54.100 78.640 ;
        RECT 54.400 78.140 54.500 78.640 ;
        RECT 52.300 71.640 52.400 72.140 ;
        RECT 49.300 75.540 49.400 76.040 ;
        RECT 50.600 75.540 50.700 76.040 ;
        RECT 51.000 75.540 51.100 76.040 ;
        RECT 52.300 75.540 52.400 76.040 ;
        RECT 52.700 75.540 52.800 76.040 ;
        RECT 54.000 75.540 54.100 76.040 ;
        RECT 54.400 75.540 54.500 76.040 ;
        RECT 48.900 74.240 49.000 74.740 ;
        RECT 49.300 74.240 49.400 74.740 ;
        RECT 48.900 79.440 49.000 79.940 ;
        RECT 49.300 71.640 49.400 72.140 ;
        RECT 49.300 79.440 49.400 79.940 ;
        RECT 50.600 79.440 50.700 79.940 ;
        RECT 51.000 79.440 51.100 79.940 ;
        RECT 52.300 79.440 52.400 79.940 ;
        RECT 52.700 79.440 52.800 79.940 ;
        RECT 52.700 71.640 52.800 72.140 ;
        RECT 54.000 79.440 54.100 79.940 ;
        RECT 54.400 79.440 54.500 79.940 ;
        RECT 50.600 74.240 50.700 74.740 ;
        RECT 51.000 74.240 51.100 74.740 ;
        RECT 52.300 74.240 52.400 74.740 ;
        RECT 52.700 74.240 52.800 74.740 ;
        RECT 54.000 74.240 54.100 74.740 ;
        RECT 54.400 74.240 54.500 74.740 ;
        RECT 54.400 71.640 54.500 72.140 ;
        RECT 48.900 76.840 49.000 77.340 ;
        RECT 49.300 76.840 49.400 77.340 ;
        RECT 50.600 71.640 50.700 72.140 ;
        RECT 48.900 82.040 49.000 82.540 ;
        RECT 49.300 82.040 49.400 82.540 ;
        RECT 50.600 82.040 50.700 82.540 ;
        RECT 51.000 82.040 51.100 82.540 ;
        RECT 54.000 71.640 54.100 72.140 ;
        RECT 52.300 82.040 52.400 82.540 ;
        RECT 52.700 82.040 52.800 82.540 ;
        RECT 54.000 82.040 54.100 82.540 ;
        RECT 54.400 82.040 54.500 82.540 ;
        RECT 50.600 76.840 50.700 77.340 ;
        RECT 51.000 76.840 51.100 77.340 ;
        RECT 52.300 76.840 52.400 77.340 ;
        RECT 52.700 76.840 52.800 77.340 ;
        RECT 34.000 74.240 34.100 74.740 ;
        RECT 34.000 84.640 34.100 85.140 ;
        RECT 34.000 72.940 34.100 73.440 ;
        RECT 34.000 78.140 34.100 78.640 ;
        RECT 34.000 85.940 34.100 86.440 ;
        RECT 34.000 87.240 34.100 87.740 ;
        RECT 34.000 79.440 34.100 79.940 ;
        RECT 34.000 88.540 34.100 89.040 ;
        RECT 34.000 75.540 34.100 76.040 ;
        RECT 34.000 71.640 34.100 72.140 ;
        RECT 34.000 89.840 34.100 90.340 ;
        RECT 34.000 82.040 34.100 82.540 ;
        RECT 34.000 91.140 34.100 91.640 ;
        RECT 33.600 92.820 34.100 93.320 ;
        RECT 34.000 76.840 34.100 77.340 ;
        RECT 34.000 83.340 34.100 83.840 ;
        RECT 37.000 83.340 37.100 83.840 ;
        RECT 37.400 83.340 37.500 83.840 ;
        RECT 38.700 83.340 38.800 83.840 ;
        RECT 35.300 85.940 35.400 86.440 ;
        RECT 35.700 85.940 35.800 86.440 ;
        RECT 37.000 85.940 37.100 86.440 ;
        RECT 37.400 85.940 37.500 86.440 ;
        RECT 38.700 85.940 38.800 86.440 ;
        RECT 39.100 85.940 39.200 86.440 ;
        RECT 40.400 85.940 40.500 86.440 ;
        RECT 39.100 83.340 39.200 83.840 ;
        RECT 35.300 87.240 35.400 87.740 ;
        RECT 35.700 87.240 35.800 87.740 ;
        RECT 37.000 87.240 37.100 87.740 ;
        RECT 37.400 87.240 37.500 87.740 ;
        RECT 38.700 87.240 38.800 87.740 ;
        RECT 39.100 87.240 39.200 87.740 ;
        RECT 40.400 87.240 40.500 87.740 ;
        RECT 40.400 83.340 40.500 83.840 ;
        RECT 35.300 83.340 35.400 83.840 ;
        RECT 35.300 88.540 35.400 89.040 ;
        RECT 35.700 88.540 35.800 89.040 ;
        RECT 37.000 88.540 37.100 89.040 ;
        RECT 37.400 88.540 37.500 89.040 ;
        RECT 38.700 88.540 38.800 89.040 ;
        RECT 39.100 88.540 39.200 89.040 ;
        RECT 40.400 88.540 40.500 89.040 ;
        RECT 35.700 83.340 35.800 83.840 ;
        RECT 35.300 84.640 35.400 85.140 ;
        RECT 35.700 84.640 35.800 85.140 ;
        RECT 35.300 89.840 35.400 90.340 ;
        RECT 35.700 89.840 35.800 90.340 ;
        RECT 37.000 89.840 37.100 90.340 ;
        RECT 37.400 89.840 37.500 90.340 ;
        RECT 38.700 89.840 38.800 90.340 ;
        RECT 39.100 89.840 39.200 90.340 ;
        RECT 40.400 89.840 40.500 90.340 ;
        RECT 37.000 84.640 37.100 85.140 ;
        RECT 37.400 84.640 37.500 85.140 ;
        RECT 35.300 91.140 35.400 91.640 ;
        RECT 35.700 91.140 35.800 91.640 ;
        RECT 37.000 91.140 37.100 91.640 ;
        RECT 37.400 91.140 37.500 91.640 ;
        RECT 38.700 91.140 38.800 91.640 ;
        RECT 39.100 91.140 39.200 91.640 ;
        RECT 40.400 91.140 40.500 91.640 ;
        RECT 38.700 84.640 38.800 85.140 ;
        RECT 35.300 92.820 35.800 93.320 ;
        RECT 37.000 92.820 37.500 93.320 ;
        RECT 38.700 92.820 39.200 93.320 ;
        RECT 39.100 84.640 39.200 85.140 ;
        RECT 40.400 84.640 40.500 85.140 ;
        RECT 28.500 87.240 28.600 87.740 ;
        RECT 28.900 87.240 29.000 87.740 ;
        RECT 30.200 87.240 30.300 87.740 ;
        RECT 30.600 87.240 30.700 87.740 ;
        RECT 31.900 87.240 32.000 87.740 ;
        RECT 28.500 89.840 28.600 90.340 ;
        RECT 28.900 89.840 29.000 90.340 ;
        RECT 30.200 89.840 30.300 90.340 ;
        RECT 30.600 89.840 30.700 90.340 ;
        RECT 31.900 89.840 32.000 90.340 ;
        RECT 32.300 89.840 32.400 90.340 ;
        RECT 33.600 89.840 33.700 90.340 ;
        RECT 32.300 87.240 32.400 87.740 ;
        RECT 33.600 87.240 33.700 87.740 ;
        RECT 28.900 85.940 29.000 86.440 ;
        RECT 30.200 85.940 30.300 86.440 ;
        RECT 30.600 85.940 30.700 86.440 ;
        RECT 31.900 85.940 32.000 86.440 ;
        RECT 32.300 85.940 32.400 86.440 ;
        RECT 33.600 85.940 33.700 86.440 ;
        RECT 30.600 84.640 30.700 85.140 ;
        RECT 28.500 91.140 28.600 91.640 ;
        RECT 28.900 91.140 29.000 91.640 ;
        RECT 30.200 91.140 30.300 91.640 ;
        RECT 30.600 91.140 30.700 91.640 ;
        RECT 31.900 91.140 32.000 91.640 ;
        RECT 32.300 91.140 32.400 91.640 ;
        RECT 33.600 91.140 33.700 91.640 ;
        RECT 31.900 84.640 32.000 85.140 ;
        RECT 32.300 84.640 32.400 85.140 ;
        RECT 28.500 88.540 28.600 89.040 ;
        RECT 28.900 88.540 29.000 89.040 ;
        RECT 30.200 88.540 30.300 89.040 ;
        RECT 30.600 88.540 30.700 89.040 ;
        RECT 31.900 88.540 32.000 89.040 ;
        RECT 32.300 88.540 32.400 89.040 ;
        RECT 28.500 92.820 29.000 93.320 ;
        RECT 30.200 92.820 30.700 93.320 ;
        RECT 31.900 92.820 32.400 93.320 ;
        RECT 33.600 88.540 33.700 89.040 ;
        RECT 33.600 84.640 33.700 85.140 ;
        RECT 28.500 84.640 28.600 85.140 ;
        RECT 28.900 84.640 29.000 85.140 ;
        RECT 30.200 84.640 30.300 85.140 ;
        RECT 28.500 83.340 28.600 83.840 ;
        RECT 28.900 83.340 29.000 83.840 ;
        RECT 30.200 83.340 30.300 83.840 ;
        RECT 30.600 83.340 30.700 83.840 ;
        RECT 31.900 83.340 32.000 83.840 ;
        RECT 32.300 83.340 32.400 83.840 ;
        RECT 33.600 83.340 33.700 83.840 ;
        RECT 28.500 85.940 28.600 86.440 ;
        RECT 33.600 79.440 33.700 79.940 ;
        RECT 30.200 71.640 30.300 72.140 ;
        RECT 28.500 82.040 28.600 82.540 ;
        RECT 28.900 82.040 29.000 82.540 ;
        RECT 30.200 82.040 30.300 82.540 ;
        RECT 30.600 82.040 30.700 82.540 ;
        RECT 31.900 82.040 32.000 82.540 ;
        RECT 32.300 82.040 32.400 82.540 ;
        RECT 33.600 82.040 33.700 82.540 ;
        RECT 30.600 71.640 30.700 72.140 ;
        RECT 31.900 71.640 32.000 72.140 ;
        RECT 32.300 71.640 32.400 72.140 ;
        RECT 28.500 75.540 28.600 76.040 ;
        RECT 31.900 74.240 32.000 74.740 ;
        RECT 30.200 72.940 30.300 73.440 ;
        RECT 30.600 72.940 30.700 73.440 ;
        RECT 31.900 72.940 32.000 73.440 ;
        RECT 32.300 72.940 32.400 73.440 ;
        RECT 33.600 72.940 33.700 73.440 ;
        RECT 32.300 74.240 32.400 74.740 ;
        RECT 28.500 78.140 28.600 78.640 ;
        RECT 28.900 78.140 29.000 78.640 ;
        RECT 30.200 78.140 30.300 78.640 ;
        RECT 30.600 78.140 30.700 78.640 ;
        RECT 33.600 75.540 33.700 76.040 ;
        RECT 28.500 71.640 28.600 72.140 ;
        RECT 28.900 71.640 29.000 72.140 ;
        RECT 28.500 72.940 28.600 73.440 ;
        RECT 28.900 72.940 29.000 73.440 ;
        RECT 28.500 74.240 28.600 74.740 ;
        RECT 28.900 74.240 29.000 74.740 ;
        RECT 30.200 74.240 30.300 74.740 ;
        RECT 30.600 74.240 30.700 74.740 ;
        RECT 28.500 76.840 28.600 77.340 ;
        RECT 28.900 76.840 29.000 77.340 ;
        RECT 30.200 76.840 30.300 77.340 ;
        RECT 30.600 76.840 30.700 77.340 ;
        RECT 31.900 76.840 32.000 77.340 ;
        RECT 32.300 76.840 32.400 77.340 ;
        RECT 33.600 76.840 33.700 77.340 ;
        RECT 31.900 78.140 32.000 78.640 ;
        RECT 33.600 71.640 33.700 72.140 ;
        RECT 32.300 78.140 32.400 78.640 ;
        RECT 33.600 78.140 33.700 78.640 ;
        RECT 33.600 74.240 33.700 74.740 ;
        RECT 28.900 75.540 29.000 76.040 ;
        RECT 30.200 75.540 30.300 76.040 ;
        RECT 30.600 75.540 30.700 76.040 ;
        RECT 31.900 75.540 32.000 76.040 ;
        RECT 32.300 75.540 32.400 76.040 ;
        RECT 28.500 79.440 28.600 79.940 ;
        RECT 28.900 79.440 29.000 79.940 ;
        RECT 30.200 79.440 30.300 79.940 ;
        RECT 30.600 79.440 30.700 79.940 ;
        RECT 31.900 79.440 32.000 79.940 ;
        RECT 32.300 79.440 32.400 79.940 ;
        RECT 39.100 76.840 39.200 77.340 ;
        RECT 40.400 74.240 40.500 74.740 ;
        RECT 35.300 82.040 35.400 82.540 ;
        RECT 35.700 82.040 35.800 82.540 ;
        RECT 37.000 82.040 37.100 82.540 ;
        RECT 37.400 82.040 37.500 82.540 ;
        RECT 38.700 82.040 38.800 82.540 ;
        RECT 39.100 82.040 39.200 82.540 ;
        RECT 35.300 78.140 35.400 78.640 ;
        RECT 37.000 78.140 37.100 78.640 ;
        RECT 37.400 78.140 37.500 78.640 ;
        RECT 38.700 78.140 38.800 78.640 ;
        RECT 39.100 78.140 39.200 78.640 ;
        RECT 38.700 79.440 38.800 79.940 ;
        RECT 39.100 79.440 39.200 79.940 ;
        RECT 40.400 79.440 40.500 79.940 ;
        RECT 40.400 78.140 40.500 78.640 ;
        RECT 35.300 72.940 35.400 73.440 ;
        RECT 35.300 75.540 35.400 76.040 ;
        RECT 35.700 75.540 35.800 76.040 ;
        RECT 37.000 75.540 37.100 76.040 ;
        RECT 37.400 75.540 37.500 76.040 ;
        RECT 38.700 75.540 38.800 76.040 ;
        RECT 40.400 82.040 40.500 82.540 ;
        RECT 40.400 71.640 40.500 72.140 ;
        RECT 39.100 75.540 39.200 76.040 ;
        RECT 40.400 75.540 40.500 76.040 ;
        RECT 35.700 72.940 35.800 73.440 ;
        RECT 37.000 72.940 37.100 73.440 ;
        RECT 35.300 71.640 35.400 72.140 ;
        RECT 35.700 71.640 35.800 72.140 ;
        RECT 37.000 71.640 37.100 72.140 ;
        RECT 37.400 72.940 37.500 73.440 ;
        RECT 38.700 72.940 38.800 73.440 ;
        RECT 39.100 72.940 39.200 73.440 ;
        RECT 40.400 72.940 40.500 73.440 ;
        RECT 35.700 78.140 35.800 78.640 ;
        RECT 40.400 76.840 40.500 77.340 ;
        RECT 35.300 76.840 35.400 77.340 ;
        RECT 35.700 76.840 35.800 77.340 ;
        RECT 37.000 76.840 37.100 77.340 ;
        RECT 35.300 79.440 35.400 79.940 ;
        RECT 35.700 79.440 35.800 79.940 ;
        RECT 37.000 79.440 37.100 79.940 ;
        RECT 37.400 79.440 37.500 79.940 ;
        RECT 37.400 76.840 37.500 77.340 ;
        RECT 35.300 74.240 35.400 74.740 ;
        RECT 37.400 71.640 37.500 72.140 ;
        RECT 38.700 71.640 38.800 72.140 ;
        RECT 39.100 71.640 39.200 72.140 ;
        RECT 35.700 74.240 35.800 74.740 ;
        RECT 37.000 74.240 37.100 74.740 ;
        RECT 37.400 74.240 37.500 74.740 ;
        RECT 38.700 74.240 38.800 74.740 ;
        RECT 39.100 74.240 39.200 74.740 ;
        RECT 38.700 76.840 38.800 77.340 ;
        RECT 34.000 52.140 34.100 52.640 ;
        RECT 34.000 53.440 34.100 53.940 ;
        RECT 34.000 54.740 34.100 55.240 ;
        RECT 34.000 56.040 34.100 56.540 ;
        RECT 34.000 58.640 34.100 59.140 ;
        RECT 34.000 48.240 34.100 48.740 ;
        RECT 34.000 59.940 34.100 60.440 ;
        RECT 34.000 49.540 34.100 50.040 ;
        RECT 34.000 61.240 34.100 61.740 ;
        RECT 34.000 62.540 34.100 63.040 ;
        RECT 34.000 63.840 34.100 64.340 ;
        RECT 34.000 65.140 34.100 65.640 ;
        RECT 34.000 66.440 34.100 66.940 ;
        RECT 34.000 67.740 34.100 68.240 ;
        RECT 34.000 70.340 34.100 70.840 ;
        RECT 34.000 50.840 34.100 51.340 ;
        RECT 35.300 61.240 35.400 61.740 ;
        RECT 35.700 61.240 35.800 61.740 ;
        RECT 37.000 61.240 37.100 61.740 ;
        RECT 37.400 61.240 37.500 61.740 ;
        RECT 38.700 61.240 38.800 61.740 ;
        RECT 39.100 61.240 39.200 61.740 ;
        RECT 40.400 61.240 40.500 61.740 ;
        RECT 37.000 59.940 37.100 60.440 ;
        RECT 35.300 62.540 35.400 63.040 ;
        RECT 35.700 62.540 35.800 63.040 ;
        RECT 37.000 62.540 37.100 63.040 ;
        RECT 37.400 62.540 37.500 63.040 ;
        RECT 38.700 62.540 38.800 63.040 ;
        RECT 39.100 62.540 39.200 63.040 ;
        RECT 40.400 62.540 40.500 63.040 ;
        RECT 37.400 59.940 37.500 60.440 ;
        RECT 35.300 63.840 35.400 64.340 ;
        RECT 35.700 63.840 35.800 64.340 ;
        RECT 37.000 63.840 37.100 64.340 ;
        RECT 37.400 63.840 37.500 64.340 ;
        RECT 38.700 63.840 38.800 64.340 ;
        RECT 39.100 63.840 39.200 64.340 ;
        RECT 40.400 63.840 40.500 64.340 ;
        RECT 38.700 59.940 38.800 60.440 ;
        RECT 35.300 65.140 35.400 65.640 ;
        RECT 35.700 65.140 35.800 65.640 ;
        RECT 37.000 65.140 37.100 65.640 ;
        RECT 37.400 65.140 37.500 65.640 ;
        RECT 38.700 65.140 38.800 65.640 ;
        RECT 39.100 65.140 39.200 65.640 ;
        RECT 40.400 65.140 40.500 65.640 ;
        RECT 39.100 59.940 39.200 60.440 ;
        RECT 35.300 66.440 35.400 66.940 ;
        RECT 35.700 66.440 35.800 66.940 ;
        RECT 37.000 66.440 37.100 66.940 ;
        RECT 37.400 66.440 37.500 66.940 ;
        RECT 38.700 66.440 38.800 66.940 ;
        RECT 39.100 66.440 39.200 66.940 ;
        RECT 40.400 66.440 40.500 66.940 ;
        RECT 40.400 59.940 40.500 60.440 ;
        RECT 35.300 67.740 35.400 68.240 ;
        RECT 35.700 67.740 35.800 68.240 ;
        RECT 37.000 67.740 37.100 68.240 ;
        RECT 37.400 67.740 37.500 68.240 ;
        RECT 38.700 67.740 38.800 68.240 ;
        RECT 39.100 67.740 39.200 68.240 ;
        RECT 40.400 67.740 40.500 68.240 ;
        RECT 35.300 59.940 35.400 60.440 ;
        RECT 35.300 70.340 35.400 70.840 ;
        RECT 35.700 70.340 35.800 70.840 ;
        RECT 37.000 70.340 37.100 70.840 ;
        RECT 37.400 70.340 37.500 70.840 ;
        RECT 38.700 70.340 38.800 70.840 ;
        RECT 39.100 70.340 39.200 70.840 ;
        RECT 40.400 70.340 40.500 70.840 ;
        RECT 35.700 59.940 35.800 60.440 ;
        RECT 32.300 65.140 32.400 65.640 ;
        RECT 33.600 65.140 33.700 65.640 ;
        RECT 30.200 62.540 30.300 63.040 ;
        RECT 30.600 62.540 30.700 63.040 ;
        RECT 31.900 62.540 32.000 63.040 ;
        RECT 32.300 62.540 32.400 63.040 ;
        RECT 33.600 62.540 33.700 63.040 ;
        RECT 28.900 61.240 29.000 61.740 ;
        RECT 30.200 61.240 30.300 61.740 ;
        RECT 30.600 61.240 30.700 61.740 ;
        RECT 28.500 66.440 28.600 66.940 ;
        RECT 28.900 66.440 29.000 66.940 ;
        RECT 30.200 66.440 30.300 66.940 ;
        RECT 30.600 66.440 30.700 66.940 ;
        RECT 31.900 66.440 32.000 66.940 ;
        RECT 32.300 66.440 32.400 66.940 ;
        RECT 33.600 66.440 33.700 66.940 ;
        RECT 31.900 61.240 32.000 61.740 ;
        RECT 32.300 61.240 32.400 61.740 ;
        RECT 33.600 61.240 33.700 61.740 ;
        RECT 30.200 59.940 30.300 60.440 ;
        RECT 30.600 59.940 30.700 60.440 ;
        RECT 28.500 63.840 28.600 64.340 ;
        RECT 28.900 63.840 29.000 64.340 ;
        RECT 30.200 63.840 30.300 64.340 ;
        RECT 28.500 67.740 28.600 68.240 ;
        RECT 28.900 67.740 29.000 68.240 ;
        RECT 30.200 67.740 30.300 68.240 ;
        RECT 30.600 67.740 30.700 68.240 ;
        RECT 31.900 67.740 32.000 68.240 ;
        RECT 32.300 67.740 32.400 68.240 ;
        RECT 33.600 67.740 33.700 68.240 ;
        RECT 30.600 63.840 30.700 64.340 ;
        RECT 31.900 63.840 32.000 64.340 ;
        RECT 32.300 63.840 32.400 64.340 ;
        RECT 33.600 63.840 33.700 64.340 ;
        RECT 31.900 59.940 32.000 60.440 ;
        RECT 32.300 59.940 32.400 60.440 ;
        RECT 33.600 59.940 33.700 60.440 ;
        RECT 28.500 59.940 28.600 60.440 ;
        RECT 28.500 70.340 28.600 70.840 ;
        RECT 28.900 70.340 29.000 70.840 ;
        RECT 30.200 70.340 30.300 70.840 ;
        RECT 30.600 70.340 30.700 70.840 ;
        RECT 31.900 70.340 32.000 70.840 ;
        RECT 32.300 70.340 32.400 70.840 ;
        RECT 33.600 70.340 33.700 70.840 ;
        RECT 28.900 59.940 29.000 60.440 ;
        RECT 28.500 61.240 28.600 61.740 ;
        RECT 28.500 62.540 28.600 63.040 ;
        RECT 28.900 62.540 29.000 63.040 ;
        RECT 28.500 65.140 28.600 65.640 ;
        RECT 28.900 65.140 29.000 65.640 ;
        RECT 30.200 65.140 30.300 65.640 ;
        RECT 30.600 65.140 30.700 65.640 ;
        RECT 31.900 65.140 32.000 65.640 ;
        RECT 28.500 58.640 28.600 59.140 ;
        RECT 28.900 58.640 29.000 59.140 ;
        RECT 30.200 58.640 30.300 59.140 ;
        RECT 30.600 58.640 30.700 59.140 ;
        RECT 31.900 58.640 32.000 59.140 ;
        RECT 32.300 58.640 32.400 59.140 ;
        RECT 33.600 58.640 33.700 59.140 ;
        RECT 31.900 52.140 32.000 52.640 ;
        RECT 33.600 49.540 33.700 50.040 ;
        RECT 32.300 52.140 32.400 52.640 ;
        RECT 33.600 52.140 33.700 52.640 ;
        RECT 28.500 52.140 28.600 52.640 ;
        RECT 30.200 49.540 30.300 50.040 ;
        RECT 30.600 48.240 30.700 48.740 ;
        RECT 28.500 53.440 28.600 53.940 ;
        RECT 28.900 53.440 29.000 53.940 ;
        RECT 30.200 53.440 30.300 53.940 ;
        RECT 30.600 53.440 30.700 53.940 ;
        RECT 31.900 53.440 32.000 53.940 ;
        RECT 32.300 53.440 32.400 53.940 ;
        RECT 33.600 53.440 33.700 53.940 ;
        RECT 28.900 52.140 29.000 52.640 ;
        RECT 30.600 49.540 30.700 50.040 ;
        RECT 31.900 48.240 32.000 48.740 ;
        RECT 28.500 54.740 28.600 55.240 ;
        RECT 28.900 54.740 29.000 55.240 ;
        RECT 30.200 54.740 30.300 55.240 ;
        RECT 30.600 54.740 30.700 55.240 ;
        RECT 31.900 54.740 32.000 55.240 ;
        RECT 32.300 54.740 32.400 55.240 ;
        RECT 33.600 54.740 33.700 55.240 ;
        RECT 30.200 52.140 30.300 52.640 ;
        RECT 31.900 49.540 32.000 50.040 ;
        RECT 32.300 48.240 32.400 48.740 ;
        RECT 28.500 56.040 28.600 56.540 ;
        RECT 28.900 56.040 29.000 56.540 ;
        RECT 30.200 56.040 30.300 56.540 ;
        RECT 30.600 56.040 30.700 56.540 ;
        RECT 31.900 56.040 32.000 56.540 ;
        RECT 32.300 56.040 32.400 56.540 ;
        RECT 33.600 56.040 33.700 56.540 ;
        RECT 30.600 52.140 30.700 52.640 ;
        RECT 32.300 49.540 32.400 50.040 ;
        RECT 28.500 49.540 28.600 50.040 ;
        RECT 28.900 48.240 29.000 48.740 ;
        RECT 28.500 50.840 28.600 51.340 ;
        RECT 28.900 50.840 29.000 51.340 ;
        RECT 30.200 50.840 30.300 51.340 ;
        RECT 30.600 50.840 30.700 51.340 ;
        RECT 31.900 50.840 32.000 51.340 ;
        RECT 32.300 50.840 32.400 51.340 ;
        RECT 33.600 50.840 33.700 51.340 ;
        RECT 33.600 48.240 33.700 48.740 ;
        RECT 28.900 49.540 29.000 50.040 ;
        RECT 30.200 48.240 30.300 48.740 ;
        RECT 28.500 48.240 28.600 48.740 ;
        RECT 40.400 56.040 40.500 56.540 ;
        RECT 38.700 49.540 38.800 50.040 ;
        RECT 39.100 48.240 39.200 48.740 ;
        RECT 35.300 48.240 35.400 48.740 ;
        RECT 37.000 52.140 37.100 52.640 ;
        RECT 35.300 53.440 35.400 53.940 ;
        RECT 35.700 53.440 35.800 53.940 ;
        RECT 37.000 53.440 37.100 53.940 ;
        RECT 35.300 54.740 35.400 55.240 ;
        RECT 35.700 54.740 35.800 55.240 ;
        RECT 37.000 54.740 37.100 55.240 ;
        RECT 37.400 54.740 37.500 55.240 ;
        RECT 38.700 54.740 38.800 55.240 ;
        RECT 37.000 49.540 37.100 50.040 ;
        RECT 37.400 48.240 37.500 48.740 ;
        RECT 39.100 54.740 39.200 55.240 ;
        RECT 35.300 58.640 35.400 59.140 ;
        RECT 35.700 58.640 35.800 59.140 ;
        RECT 39.100 49.540 39.200 50.040 ;
        RECT 40.400 48.240 40.500 48.740 ;
        RECT 37.000 58.640 37.100 59.140 ;
        RECT 37.400 58.640 37.500 59.140 ;
        RECT 38.700 58.640 38.800 59.140 ;
        RECT 35.300 49.540 35.400 50.040 ;
        RECT 35.700 48.240 35.800 48.740 ;
        RECT 39.100 58.640 39.200 59.140 ;
        RECT 40.400 58.640 40.500 59.140 ;
        RECT 40.400 54.740 40.500 55.240 ;
        RECT 37.400 53.440 37.500 53.940 ;
        RECT 38.700 53.440 38.800 53.940 ;
        RECT 39.100 53.440 39.200 53.940 ;
        RECT 40.400 53.440 40.500 53.940 ;
        RECT 37.400 49.540 37.500 50.040 ;
        RECT 38.700 48.240 38.800 48.740 ;
        RECT 37.400 52.140 37.500 52.640 ;
        RECT 40.400 49.540 40.500 50.040 ;
        RECT 38.700 52.140 38.800 52.640 ;
        RECT 39.100 52.140 39.200 52.640 ;
        RECT 40.400 52.140 40.500 52.640 ;
        RECT 35.300 52.140 35.400 52.640 ;
        RECT 35.700 52.140 35.800 52.640 ;
        RECT 35.300 56.040 35.400 56.540 ;
        RECT 35.700 56.040 35.800 56.540 ;
        RECT 35.700 49.540 35.800 50.040 ;
        RECT 37.000 48.240 37.100 48.740 ;
        RECT 37.000 56.040 37.100 56.540 ;
        RECT 35.300 50.840 35.400 51.340 ;
        RECT 35.700 50.840 35.800 51.340 ;
        RECT 37.000 50.840 37.100 51.340 ;
        RECT 37.400 50.840 37.500 51.340 ;
        RECT 38.700 50.840 38.800 51.340 ;
        RECT 39.100 50.840 39.200 51.340 ;
        RECT 40.400 50.840 40.500 51.340 ;
        RECT 37.400 56.040 37.500 56.540 ;
        RECT 38.700 56.040 38.800 56.540 ;
        RECT 39.100 56.040 39.200 56.540 ;
        RECT 47.600 48.240 47.700 48.740 ;
        RECT 47.600 61.240 47.700 61.740 ;
        RECT 47.600 54.740 47.700 55.240 ;
        RECT 47.600 62.540 47.700 63.040 ;
        RECT 47.600 52.140 47.700 52.640 ;
        RECT 47.600 63.840 47.700 64.340 ;
        RECT 47.600 56.040 47.700 56.540 ;
        RECT 47.600 50.840 47.700 51.340 ;
        RECT 47.600 65.140 47.700 65.640 ;
        RECT 47.600 66.440 47.700 66.940 ;
        RECT 47.600 58.640 47.700 59.140 ;
        RECT 47.600 53.440 47.700 53.940 ;
        RECT 47.600 67.740 47.700 68.240 ;
        RECT 47.600 70.340 47.700 70.840 ;
        RECT 47.600 59.940 47.700 60.440 ;
        RECT 47.600 49.540 47.700 50.040 ;
        RECT 52.300 62.540 52.400 63.040 ;
        RECT 52.700 62.540 52.800 63.040 ;
        RECT 54.000 62.540 54.100 63.040 ;
        RECT 54.400 62.540 54.500 63.040 ;
        RECT 50.600 61.240 50.700 61.740 ;
        RECT 51.000 61.240 51.100 61.740 ;
        RECT 48.900 63.840 49.000 64.340 ;
        RECT 49.300 63.840 49.400 64.340 ;
        RECT 50.600 63.840 50.700 64.340 ;
        RECT 51.000 63.840 51.100 64.340 ;
        RECT 52.300 63.840 52.400 64.340 ;
        RECT 52.700 63.840 52.800 64.340 ;
        RECT 54.000 63.840 54.100 64.340 ;
        RECT 54.400 63.840 54.500 64.340 ;
        RECT 52.300 61.240 52.400 61.740 ;
        RECT 52.700 61.240 52.800 61.740 ;
        RECT 54.000 61.240 54.100 61.740 ;
        RECT 48.900 65.140 49.000 65.640 ;
        RECT 49.300 65.140 49.400 65.640 ;
        RECT 50.600 65.140 50.700 65.640 ;
        RECT 51.000 65.140 51.100 65.640 ;
        RECT 52.300 65.140 52.400 65.640 ;
        RECT 52.700 65.140 52.800 65.640 ;
        RECT 54.000 65.140 54.100 65.640 ;
        RECT 54.400 65.140 54.500 65.640 ;
        RECT 54.400 61.240 54.500 61.740 ;
        RECT 48.900 66.440 49.000 66.940 ;
        RECT 49.300 66.440 49.400 66.940 ;
        RECT 50.600 66.440 50.700 66.940 ;
        RECT 51.000 66.440 51.100 66.940 ;
        RECT 52.300 66.440 52.400 66.940 ;
        RECT 52.700 66.440 52.800 66.940 ;
        RECT 54.000 66.440 54.100 66.940 ;
        RECT 54.400 66.440 54.500 66.940 ;
        RECT 48.900 61.240 49.000 61.740 ;
        RECT 49.300 61.240 49.400 61.740 ;
        RECT 48.900 62.540 49.000 63.040 ;
        RECT 48.900 67.740 49.000 68.240 ;
        RECT 49.300 67.740 49.400 68.240 ;
        RECT 50.600 67.740 50.700 68.240 ;
        RECT 51.000 67.740 51.100 68.240 ;
        RECT 52.300 67.740 52.400 68.240 ;
        RECT 52.700 67.740 52.800 68.240 ;
        RECT 54.000 67.740 54.100 68.240 ;
        RECT 54.400 67.740 54.500 68.240 ;
        RECT 49.300 62.540 49.400 63.040 ;
        RECT 48.900 70.340 49.000 70.840 ;
        RECT 49.300 70.340 49.400 70.840 ;
        RECT 50.600 70.340 50.700 70.840 ;
        RECT 51.000 70.340 51.100 70.840 ;
        RECT 52.300 70.340 52.400 70.840 ;
        RECT 52.700 70.340 52.800 70.840 ;
        RECT 54.000 70.340 54.100 70.840 ;
        RECT 54.400 70.340 54.500 70.840 ;
        RECT 50.600 62.540 50.700 63.040 ;
        RECT 48.900 59.940 49.000 60.440 ;
        RECT 49.300 59.940 49.400 60.440 ;
        RECT 50.600 59.940 50.700 60.440 ;
        RECT 51.000 59.940 51.100 60.440 ;
        RECT 52.300 59.940 52.400 60.440 ;
        RECT 52.700 59.940 52.800 60.440 ;
        RECT 54.000 59.940 54.100 60.440 ;
        RECT 54.400 59.940 54.500 60.440 ;
        RECT 51.000 62.540 51.100 63.040 ;
        RECT 47.200 62.540 47.300 63.040 ;
        RECT 44.200 61.240 44.300 61.740 ;
        RECT 45.500 61.240 45.600 61.740 ;
        RECT 45.900 61.240 46.000 61.740 ;
        RECT 47.200 61.240 47.300 61.740 ;
        RECT 42.100 61.240 42.200 61.740 ;
        RECT 42.500 61.240 42.600 61.740 ;
        RECT 42.100 67.740 42.200 68.240 ;
        RECT 42.500 67.740 42.600 68.240 ;
        RECT 43.800 67.740 43.900 68.240 ;
        RECT 44.200 67.740 44.300 68.240 ;
        RECT 45.500 67.740 45.600 68.240 ;
        RECT 45.900 67.740 46.000 68.240 ;
        RECT 47.200 67.740 47.300 68.240 ;
        RECT 43.800 61.240 43.900 61.740 ;
        RECT 42.100 65.140 42.200 65.640 ;
        RECT 42.500 65.140 42.600 65.640 ;
        RECT 43.800 65.140 43.900 65.640 ;
        RECT 44.200 65.140 44.300 65.640 ;
        RECT 45.500 65.140 45.600 65.640 ;
        RECT 45.900 65.140 46.000 65.640 ;
        RECT 47.200 65.140 47.300 65.640 ;
        RECT 42.100 62.540 42.200 63.040 ;
        RECT 42.100 59.940 42.200 60.440 ;
        RECT 42.500 59.940 42.600 60.440 ;
        RECT 43.800 59.940 43.900 60.440 ;
        RECT 44.200 59.940 44.300 60.440 ;
        RECT 45.500 59.940 45.600 60.440 ;
        RECT 45.900 59.940 46.000 60.440 ;
        RECT 47.200 59.940 47.300 60.440 ;
        RECT 42.100 70.340 42.200 70.840 ;
        RECT 42.500 70.340 42.600 70.840 ;
        RECT 43.800 70.340 43.900 70.840 ;
        RECT 44.200 70.340 44.300 70.840 ;
        RECT 45.500 70.340 45.600 70.840 ;
        RECT 45.900 70.340 46.000 70.840 ;
        RECT 47.200 70.340 47.300 70.840 ;
        RECT 42.500 62.540 42.600 63.040 ;
        RECT 43.800 62.540 43.900 63.040 ;
        RECT 42.100 63.840 42.200 64.340 ;
        RECT 42.500 63.840 42.600 64.340 ;
        RECT 43.800 63.840 43.900 64.340 ;
        RECT 44.200 63.840 44.300 64.340 ;
        RECT 45.500 63.840 45.600 64.340 ;
        RECT 45.900 63.840 46.000 64.340 ;
        RECT 42.100 66.440 42.200 66.940 ;
        RECT 42.500 66.440 42.600 66.940 ;
        RECT 43.800 66.440 43.900 66.940 ;
        RECT 44.200 66.440 44.300 66.940 ;
        RECT 45.500 66.440 45.600 66.940 ;
        RECT 45.900 66.440 46.000 66.940 ;
        RECT 47.200 66.440 47.300 66.940 ;
        RECT 47.200 63.840 47.300 64.340 ;
        RECT 44.200 62.540 44.300 63.040 ;
        RECT 45.500 62.540 45.600 63.040 ;
        RECT 45.900 62.540 46.000 63.040 ;
        RECT 43.800 50.840 43.900 51.340 ;
        RECT 44.200 50.840 44.300 51.340 ;
        RECT 42.100 56.040 42.200 56.540 ;
        RECT 45.900 48.240 46.000 48.740 ;
        RECT 44.200 48.240 44.300 48.740 ;
        RECT 42.500 56.040 42.600 56.540 ;
        RECT 43.800 56.040 43.900 56.540 ;
        RECT 44.200 56.040 44.300 56.540 ;
        RECT 45.500 56.040 45.600 56.540 ;
        RECT 42.100 49.540 42.200 50.040 ;
        RECT 42.100 50.840 42.200 51.340 ;
        RECT 42.100 52.140 42.200 52.640 ;
        RECT 42.500 52.140 42.600 52.640 ;
        RECT 42.100 54.740 42.200 55.240 ;
        RECT 43.800 48.240 43.900 48.740 ;
        RECT 42.500 54.740 42.600 55.240 ;
        RECT 42.500 48.240 42.600 48.740 ;
        RECT 42.500 49.540 42.600 50.040 ;
        RECT 44.200 49.540 44.300 50.040 ;
        RECT 45.500 49.540 45.600 50.040 ;
        RECT 45.900 49.540 46.000 50.040 ;
        RECT 47.200 49.540 47.300 50.040 ;
        RECT 43.800 49.540 43.900 50.040 ;
        RECT 42.100 53.440 42.200 53.940 ;
        RECT 42.500 53.440 42.600 53.940 ;
        RECT 43.800 53.440 43.900 53.940 ;
        RECT 42.100 58.640 42.200 59.140 ;
        RECT 42.500 58.640 42.600 59.140 ;
        RECT 43.800 58.640 43.900 59.140 ;
        RECT 44.200 58.640 44.300 59.140 ;
        RECT 47.200 48.240 47.300 48.740 ;
        RECT 45.500 58.640 45.600 59.140 ;
        RECT 45.900 58.640 46.000 59.140 ;
        RECT 43.800 54.740 43.900 55.240 ;
        RECT 42.100 48.240 42.200 48.740 ;
        RECT 45.500 54.740 45.600 55.240 ;
        RECT 45.500 48.240 45.600 48.740 ;
        RECT 45.900 54.740 46.000 55.240 ;
        RECT 47.200 54.740 47.300 55.240 ;
        RECT 44.200 54.740 44.300 55.240 ;
        RECT 43.800 52.140 43.900 52.640 ;
        RECT 44.200 52.140 44.300 52.640 ;
        RECT 45.500 52.140 45.600 52.640 ;
        RECT 45.900 56.040 46.000 56.540 ;
        RECT 47.200 56.040 47.300 56.540 ;
        RECT 45.900 52.140 46.000 52.640 ;
        RECT 45.500 50.840 45.600 51.340 ;
        RECT 45.900 50.840 46.000 51.340 ;
        RECT 47.200 50.840 47.300 51.340 ;
        RECT 47.200 52.140 47.300 52.640 ;
        RECT 47.200 58.640 47.300 59.140 ;
        RECT 42.500 50.840 42.600 51.340 ;
        RECT 44.200 53.440 44.300 53.940 ;
        RECT 45.500 53.440 45.600 53.940 ;
        RECT 45.900 53.440 46.000 53.940 ;
        RECT 47.200 53.440 47.300 53.940 ;
        RECT 51.000 48.240 51.100 48.740 ;
        RECT 50.600 50.840 50.700 51.340 ;
        RECT 51.000 50.840 51.100 51.340 ;
        RECT 52.300 50.840 52.400 51.340 ;
        RECT 52.700 50.840 52.800 51.340 ;
        RECT 54.000 50.840 54.100 51.340 ;
        RECT 54.400 50.840 54.500 51.340 ;
        RECT 54.400 52.140 54.500 52.640 ;
        RECT 48.900 54.740 49.000 55.240 ;
        RECT 49.300 54.740 49.400 55.240 ;
        RECT 50.600 48.240 50.700 48.740 ;
        RECT 48.900 48.240 49.000 48.740 ;
        RECT 52.700 48.240 52.800 48.740 ;
        RECT 48.900 56.040 49.000 56.540 ;
        RECT 49.300 56.040 49.400 56.540 ;
        RECT 50.600 56.040 50.700 56.540 ;
        RECT 51.000 56.040 51.100 56.540 ;
        RECT 50.600 53.440 50.700 53.940 ;
        RECT 51.000 53.440 51.100 53.940 ;
        RECT 52.300 53.440 52.400 53.940 ;
        RECT 52.700 53.440 52.800 53.940 ;
        RECT 54.000 53.440 54.100 53.940 ;
        RECT 54.400 53.440 54.500 53.940 ;
        RECT 52.300 56.040 52.400 56.540 ;
        RECT 52.700 56.040 52.800 56.540 ;
        RECT 54.000 56.040 54.100 56.540 ;
        RECT 54.400 56.040 54.500 56.540 ;
        RECT 50.600 54.740 50.700 55.240 ;
        RECT 51.000 54.740 51.100 55.240 ;
        RECT 52.300 54.740 52.400 55.240 ;
        RECT 52.700 54.740 52.800 55.240 ;
        RECT 48.900 50.840 49.000 51.340 ;
        RECT 49.300 50.840 49.400 51.340 ;
        RECT 54.000 54.740 54.100 55.240 ;
        RECT 54.400 54.740 54.500 55.240 ;
        RECT 51.000 49.540 51.100 50.040 ;
        RECT 52.300 49.540 52.400 50.040 ;
        RECT 52.700 49.540 52.800 50.040 ;
        RECT 54.000 49.540 54.100 50.040 ;
        RECT 49.300 49.540 49.400 50.040 ;
        RECT 52.300 48.240 52.400 48.740 ;
        RECT 54.400 49.540 54.500 50.040 ;
        RECT 50.600 49.540 50.700 50.040 ;
        RECT 48.900 52.140 49.000 52.640 ;
        RECT 49.300 52.140 49.400 52.640 ;
        RECT 54.000 48.240 54.100 48.740 ;
        RECT 48.900 58.640 49.000 59.140 ;
        RECT 49.300 58.640 49.400 59.140 ;
        RECT 50.600 58.640 50.700 59.140 ;
        RECT 51.000 58.640 51.100 59.140 ;
        RECT 52.300 58.640 52.400 59.140 ;
        RECT 52.700 58.640 52.800 59.140 ;
        RECT 54.000 58.640 54.100 59.140 ;
        RECT 54.400 58.640 54.500 59.140 ;
        RECT 50.600 52.140 50.700 52.640 ;
        RECT 49.300 48.240 49.400 48.740 ;
        RECT 51.000 52.140 51.100 52.640 ;
        RECT 52.300 52.140 52.400 52.640 ;
        RECT 52.700 52.140 52.800 52.640 ;
        RECT 48.900 53.440 49.000 53.940 ;
        RECT 49.300 53.440 49.400 53.940 ;
        RECT 54.000 52.140 54.100 52.640 ;
        RECT 54.400 48.240 54.500 48.740 ;
        RECT 48.900 49.540 49.000 50.040 ;
        RECT 13.600 53.440 13.700 53.940 ;
        RECT 13.600 72.940 13.700 73.440 ;
        RECT 13.600 61.240 13.700 61.740 ;
        RECT 13.600 74.240 13.700 74.740 ;
        RECT 13.600 50.840 13.700 51.340 ;
        RECT 13.600 75.540 13.700 76.040 ;
        RECT 13.600 62.540 13.700 63.040 ;
        RECT 13.600 76.840 13.700 77.340 ;
        RECT 13.600 54.740 13.700 55.240 ;
        RECT 13.600 78.140 13.700 78.640 ;
        RECT 13.600 49.540 13.700 50.040 ;
        RECT 13.600 63.840 13.700 64.340 ;
        RECT 13.600 79.440 13.700 79.940 ;
        RECT 13.600 82.040 13.700 82.540 ;
        RECT 13.600 65.140 13.700 65.640 ;
        RECT 13.600 83.340 13.700 83.840 ;
        RECT 13.600 56.040 13.700 56.540 ;
        RECT 13.600 84.640 13.700 85.140 ;
        RECT 13.600 52.140 13.700 52.640 ;
        RECT 13.600 66.440 13.700 66.940 ;
        RECT 13.600 85.940 13.700 86.440 ;
        RECT 13.600 87.240 13.700 87.740 ;
        RECT 13.600 67.740 13.700 68.240 ;
        RECT 13.600 88.540 13.700 89.040 ;
        RECT 13.600 58.640 13.700 59.140 ;
        RECT 13.600 48.240 13.700 48.740 ;
        RECT 13.600 89.840 13.700 90.340 ;
        RECT 13.600 70.340 13.700 70.840 ;
        RECT 13.600 91.140 13.700 91.640 ;
        RECT 13.200 92.820 13.700 93.320 ;
        RECT 13.600 59.940 13.700 60.440 ;
        RECT 13.600 71.640 13.700 72.140 ;
        RECT 20.400 74.240 20.500 74.740 ;
        RECT 20.400 71.640 20.500 72.140 ;
        RECT 20.400 75.540 20.500 76.040 ;
        RECT 20.400 76.840 20.500 77.340 ;
        RECT 20.400 78.140 20.500 78.640 ;
        RECT 20.400 79.440 20.500 79.940 ;
        RECT 20.400 82.040 20.500 82.540 ;
        RECT 20.400 83.340 20.500 83.840 ;
        RECT 20.400 84.640 20.500 85.140 ;
        RECT 20.400 85.940 20.500 86.440 ;
        RECT 20.400 87.240 20.500 87.740 ;
        RECT 20.400 72.940 20.500 73.440 ;
        RECT 20.400 88.540 20.500 89.040 ;
        RECT 20.400 89.840 20.500 90.340 ;
        RECT 20.400 91.140 20.500 91.640 ;
        RECT 20.000 92.820 20.500 93.320 ;
        RECT 21.700 84.640 21.800 85.140 ;
        RECT 22.100 84.640 22.200 85.140 ;
        RECT 23.400 84.640 23.500 85.140 ;
        RECT 23.800 84.640 23.900 85.140 ;
        RECT 25.100 84.640 25.200 85.140 ;
        RECT 25.500 84.640 25.600 85.140 ;
        RECT 26.800 84.640 26.900 85.140 ;
        RECT 22.100 83.340 22.200 83.840 ;
        RECT 21.700 85.940 21.800 86.440 ;
        RECT 22.100 85.940 22.200 86.440 ;
        RECT 23.400 85.940 23.500 86.440 ;
        RECT 23.800 85.940 23.900 86.440 ;
        RECT 25.100 85.940 25.200 86.440 ;
        RECT 25.500 85.940 25.600 86.440 ;
        RECT 26.800 85.940 26.900 86.440 ;
        RECT 23.400 83.340 23.500 83.840 ;
        RECT 21.700 87.240 21.800 87.740 ;
        RECT 22.100 87.240 22.200 87.740 ;
        RECT 23.400 87.240 23.500 87.740 ;
        RECT 23.800 87.240 23.900 87.740 ;
        RECT 25.100 87.240 25.200 87.740 ;
        RECT 25.500 87.240 25.600 87.740 ;
        RECT 26.800 87.240 26.900 87.740 ;
        RECT 23.800 83.340 23.900 83.840 ;
        RECT 25.100 83.340 25.200 83.840 ;
        RECT 21.700 88.540 21.800 89.040 ;
        RECT 22.100 88.540 22.200 89.040 ;
        RECT 23.400 88.540 23.500 89.040 ;
        RECT 23.800 88.540 23.900 89.040 ;
        RECT 25.100 88.540 25.200 89.040 ;
        RECT 25.500 88.540 25.600 89.040 ;
        RECT 26.800 88.540 26.900 89.040 ;
        RECT 25.500 83.340 25.600 83.840 ;
        RECT 21.700 89.840 21.800 90.340 ;
        RECT 22.100 89.840 22.200 90.340 ;
        RECT 23.400 89.840 23.500 90.340 ;
        RECT 23.800 89.840 23.900 90.340 ;
        RECT 25.100 89.840 25.200 90.340 ;
        RECT 25.500 89.840 25.600 90.340 ;
        RECT 26.800 89.840 26.900 90.340 ;
        RECT 26.800 83.340 26.900 83.840 ;
        RECT 21.700 91.140 21.800 91.640 ;
        RECT 22.100 91.140 22.200 91.640 ;
        RECT 23.400 91.140 23.500 91.640 ;
        RECT 23.800 91.140 23.900 91.640 ;
        RECT 25.100 91.140 25.200 91.640 ;
        RECT 25.500 91.140 25.600 91.640 ;
        RECT 26.800 91.140 26.900 91.640 ;
        RECT 21.700 83.340 21.800 83.840 ;
        RECT 21.700 92.820 22.200 93.320 ;
        RECT 23.400 92.820 23.900 93.320 ;
        RECT 25.100 92.820 25.600 93.320 ;
        RECT 14.900 88.540 15.000 89.040 ;
        RECT 15.300 88.540 15.400 89.040 ;
        RECT 16.600 88.540 16.700 89.040 ;
        RECT 17.000 88.540 17.100 89.040 ;
        RECT 18.300 88.540 18.400 89.040 ;
        RECT 18.700 88.540 18.800 89.040 ;
        RECT 20.000 88.540 20.100 89.040 ;
        RECT 17.000 85.940 17.100 86.440 ;
        RECT 18.300 85.940 18.400 86.440 ;
        RECT 18.700 85.940 18.800 86.440 ;
        RECT 20.000 85.940 20.100 86.440 ;
        RECT 15.300 84.640 15.400 85.140 ;
        RECT 16.600 84.640 16.700 85.140 ;
        RECT 17.000 84.640 17.100 85.140 ;
        RECT 18.300 84.640 18.400 85.140 ;
        RECT 14.900 89.840 15.000 90.340 ;
        RECT 15.300 89.840 15.400 90.340 ;
        RECT 16.600 89.840 16.700 90.340 ;
        RECT 17.000 89.840 17.100 90.340 ;
        RECT 18.300 89.840 18.400 90.340 ;
        RECT 18.700 89.840 18.800 90.340 ;
        RECT 20.000 89.840 20.100 90.340 ;
        RECT 18.700 84.640 18.800 85.140 ;
        RECT 20.000 84.640 20.100 85.140 ;
        RECT 15.300 83.340 15.400 83.840 ;
        RECT 16.600 83.340 16.700 83.840 ;
        RECT 14.900 87.240 15.000 87.740 ;
        RECT 15.300 87.240 15.400 87.740 ;
        RECT 16.600 87.240 16.700 87.740 ;
        RECT 17.000 87.240 17.100 87.740 ;
        RECT 14.900 91.140 15.000 91.640 ;
        RECT 15.300 91.140 15.400 91.640 ;
        RECT 16.600 91.140 16.700 91.640 ;
        RECT 17.000 91.140 17.100 91.640 ;
        RECT 18.300 91.140 18.400 91.640 ;
        RECT 18.700 91.140 18.800 91.640 ;
        RECT 20.000 91.140 20.100 91.640 ;
        RECT 18.300 87.240 18.400 87.740 ;
        RECT 18.700 87.240 18.800 87.740 ;
        RECT 20.000 87.240 20.100 87.740 ;
        RECT 17.000 83.340 17.100 83.840 ;
        RECT 18.300 83.340 18.400 83.840 ;
        RECT 18.700 83.340 18.800 83.840 ;
        RECT 20.000 83.340 20.100 83.840 ;
        RECT 14.900 83.340 15.000 83.840 ;
        RECT 14.900 92.820 15.400 93.320 ;
        RECT 16.600 92.820 17.100 93.320 ;
        RECT 18.300 92.820 18.800 93.320 ;
        RECT 14.900 84.640 15.000 85.140 ;
        RECT 14.900 85.940 15.000 86.440 ;
        RECT 15.300 85.940 15.400 86.440 ;
        RECT 16.600 85.940 16.700 86.440 ;
        RECT 15.300 72.940 15.400 73.440 ;
        RECT 16.600 72.940 16.700 73.440 ;
        RECT 18.300 76.840 18.400 77.340 ;
        RECT 18.700 76.840 18.800 77.340 ;
        RECT 20.000 76.840 20.100 77.340 ;
        RECT 17.000 74.240 17.100 74.740 ;
        RECT 14.900 78.140 15.000 78.640 ;
        RECT 15.300 78.140 15.400 78.640 ;
        RECT 16.600 78.140 16.700 78.640 ;
        RECT 17.000 78.140 17.100 78.640 ;
        RECT 18.300 78.140 18.400 78.640 ;
        RECT 18.700 78.140 18.800 78.640 ;
        RECT 20.000 78.140 20.100 78.640 ;
        RECT 18.300 74.240 18.400 74.740 ;
        RECT 14.900 79.440 15.000 79.940 ;
        RECT 15.300 79.440 15.400 79.940 ;
        RECT 16.600 79.440 16.700 79.940 ;
        RECT 17.000 72.940 17.100 73.440 ;
        RECT 18.300 72.940 18.400 73.440 ;
        RECT 18.700 72.940 18.800 73.440 ;
        RECT 17.000 79.440 17.100 79.940 ;
        RECT 18.300 79.440 18.400 79.940 ;
        RECT 18.700 79.440 18.800 79.940 ;
        RECT 20.000 79.440 20.100 79.940 ;
        RECT 18.700 74.240 18.800 74.740 ;
        RECT 16.600 71.640 16.700 72.140 ;
        RECT 14.900 82.040 15.000 82.540 ;
        RECT 15.300 82.040 15.400 82.540 ;
        RECT 16.600 82.040 16.700 82.540 ;
        RECT 17.000 82.040 17.100 82.540 ;
        RECT 18.300 82.040 18.400 82.540 ;
        RECT 18.700 82.040 18.800 82.540 ;
        RECT 20.000 82.040 20.100 82.540 ;
        RECT 20.000 74.240 20.100 74.740 ;
        RECT 17.000 71.640 17.100 72.140 ;
        RECT 20.000 72.940 20.100 73.440 ;
        RECT 14.900 72.940 15.000 73.440 ;
        RECT 14.900 74.240 15.000 74.740 ;
        RECT 20.000 71.640 20.100 72.140 ;
        RECT 15.300 74.240 15.400 74.740 ;
        RECT 14.900 75.540 15.000 76.040 ;
        RECT 15.300 75.540 15.400 76.040 ;
        RECT 16.600 75.540 16.700 76.040 ;
        RECT 17.000 75.540 17.100 76.040 ;
        RECT 18.300 75.540 18.400 76.040 ;
        RECT 18.700 75.540 18.800 76.040 ;
        RECT 20.000 75.540 20.100 76.040 ;
        RECT 16.600 74.240 16.700 74.740 ;
        RECT 14.900 76.840 15.000 77.340 ;
        RECT 15.300 76.840 15.400 77.340 ;
        RECT 16.600 76.840 16.700 77.340 ;
        RECT 17.000 76.840 17.100 77.340 ;
        RECT 18.300 71.640 18.400 72.140 ;
        RECT 18.700 71.640 18.800 72.140 ;
        RECT 14.900 71.640 15.000 72.140 ;
        RECT 15.300 71.640 15.400 72.140 ;
        RECT 21.700 79.440 21.800 79.940 ;
        RECT 22.100 79.440 22.200 79.940 ;
        RECT 23.400 79.440 23.500 79.940 ;
        RECT 23.800 79.440 23.900 79.940 ;
        RECT 25.100 79.440 25.200 79.940 ;
        RECT 25.500 79.440 25.600 79.940 ;
        RECT 26.800 79.440 26.900 79.940 ;
        RECT 21.700 76.840 21.800 77.340 ;
        RECT 22.100 76.840 22.200 77.340 ;
        RECT 22.100 72.940 22.200 73.440 ;
        RECT 23.400 72.940 23.500 73.440 ;
        RECT 23.800 72.940 23.900 73.440 ;
        RECT 23.400 76.840 23.500 77.340 ;
        RECT 23.800 76.840 23.900 77.340 ;
        RECT 25.100 76.840 25.200 77.340 ;
        RECT 25.500 76.840 25.600 77.340 ;
        RECT 26.800 76.840 26.900 77.340 ;
        RECT 23.400 71.640 23.500 72.140 ;
        RECT 23.800 71.640 23.900 72.140 ;
        RECT 21.700 82.040 21.800 82.540 ;
        RECT 22.100 82.040 22.200 82.540 ;
        RECT 23.400 82.040 23.500 82.540 ;
        RECT 23.800 82.040 23.900 82.540 ;
        RECT 25.100 82.040 25.200 82.540 ;
        RECT 25.500 82.040 25.600 82.540 ;
        RECT 26.800 82.040 26.900 82.540 ;
        RECT 22.100 75.540 22.200 76.040 ;
        RECT 25.100 72.940 25.200 73.440 ;
        RECT 25.500 72.940 25.600 73.440 ;
        RECT 23.400 75.540 23.500 76.040 ;
        RECT 23.800 75.540 23.900 76.040 ;
        RECT 25.100 75.540 25.200 76.040 ;
        RECT 25.500 75.540 25.600 76.040 ;
        RECT 26.800 75.540 26.900 76.040 ;
        RECT 21.700 71.640 21.800 72.140 ;
        RECT 22.100 71.640 22.200 72.140 ;
        RECT 21.700 78.140 21.800 78.640 ;
        RECT 22.100 78.140 22.200 78.640 ;
        RECT 23.400 78.140 23.500 78.640 ;
        RECT 23.800 78.140 23.900 78.640 ;
        RECT 25.100 78.140 25.200 78.640 ;
        RECT 25.500 78.140 25.600 78.640 ;
        RECT 26.800 78.140 26.900 78.640 ;
        RECT 25.100 71.640 25.200 72.140 ;
        RECT 26.800 72.940 26.900 73.440 ;
        RECT 25.500 71.640 25.600 72.140 ;
        RECT 26.800 71.640 26.900 72.140 ;
        RECT 23.800 74.240 23.900 74.740 ;
        RECT 25.100 74.240 25.200 74.740 ;
        RECT 21.700 72.940 21.800 73.440 ;
        RECT 25.500 74.240 25.600 74.740 ;
        RECT 26.800 74.240 26.900 74.740 ;
        RECT 21.700 74.240 21.800 74.740 ;
        RECT 22.100 74.240 22.200 74.740 ;
        RECT 23.400 74.240 23.500 74.740 ;
        RECT 21.700 75.540 21.800 76.040 ;
        RECT 6.800 78.140 6.900 78.640 ;
        RECT 6.800 84.640 6.900 85.140 ;
        RECT 6.800 75.540 6.900 76.040 ;
        RECT 6.800 85.940 6.900 86.440 ;
        RECT 6.800 74.240 6.900 74.740 ;
        RECT 6.800 79.440 6.900 79.940 ;
        RECT 6.800 87.240 6.900 87.740 ;
        RECT 6.800 88.540 6.900 89.040 ;
        RECT 6.800 82.040 6.900 82.540 ;
        RECT 6.800 89.840 6.900 90.340 ;
        RECT 6.800 76.840 6.900 77.340 ;
        RECT 6.800 72.940 6.900 73.440 ;
        RECT 6.800 91.140 6.900 91.640 ;
        RECT 6.800 83.340 6.900 83.840 ;
        RECT 6.400 92.820 6.900 93.320 ;
        RECT 6.800 71.640 6.900 72.140 ;
        RECT 11.900 85.940 12.000 86.440 ;
        RECT 13.200 85.940 13.300 86.440 ;
        RECT 9.800 84.640 9.900 85.140 ;
        RECT 10.200 84.640 10.300 85.140 ;
        RECT 11.500 84.640 11.600 85.140 ;
        RECT 8.100 87.240 8.200 87.740 ;
        RECT 8.500 87.240 8.600 87.740 ;
        RECT 9.800 87.240 9.900 87.740 ;
        RECT 10.200 87.240 10.300 87.740 ;
        RECT 11.500 87.240 11.600 87.740 ;
        RECT 11.900 87.240 12.000 87.740 ;
        RECT 13.200 87.240 13.300 87.740 ;
        RECT 11.900 84.640 12.000 85.140 ;
        RECT 8.100 88.540 8.200 89.040 ;
        RECT 8.500 88.540 8.600 89.040 ;
        RECT 9.800 88.540 9.900 89.040 ;
        RECT 10.200 88.540 10.300 89.040 ;
        RECT 11.500 88.540 11.600 89.040 ;
        RECT 11.900 88.540 12.000 89.040 ;
        RECT 13.200 88.540 13.300 89.040 ;
        RECT 13.200 84.640 13.300 85.140 ;
        RECT 8.100 84.640 8.200 85.140 ;
        RECT 8.100 89.840 8.200 90.340 ;
        RECT 8.500 89.840 8.600 90.340 ;
        RECT 9.800 89.840 9.900 90.340 ;
        RECT 10.200 89.840 10.300 90.340 ;
        RECT 11.500 89.840 11.600 90.340 ;
        RECT 11.900 89.840 12.000 90.340 ;
        RECT 13.200 89.840 13.300 90.340 ;
        RECT 8.500 84.640 8.600 85.140 ;
        RECT 8.100 85.940 8.200 86.440 ;
        RECT 8.500 85.940 8.600 86.440 ;
        RECT 8.100 91.140 8.200 91.640 ;
        RECT 8.500 91.140 8.600 91.640 ;
        RECT 9.800 91.140 9.900 91.640 ;
        RECT 10.200 91.140 10.300 91.640 ;
        RECT 11.500 91.140 11.600 91.640 ;
        RECT 11.900 91.140 12.000 91.640 ;
        RECT 13.200 91.140 13.300 91.640 ;
        RECT 9.800 85.940 9.900 86.440 ;
        RECT 8.100 83.340 8.200 83.840 ;
        RECT 8.500 83.340 8.600 83.840 ;
        RECT 9.800 83.340 9.900 83.840 ;
        RECT 10.200 83.340 10.300 83.840 ;
        RECT 11.500 83.340 11.600 83.840 ;
        RECT 11.900 83.340 12.000 83.840 ;
        RECT 10.200 85.940 10.300 86.440 ;
        RECT 8.100 92.820 8.600 93.320 ;
        RECT 9.800 92.820 10.300 93.320 ;
        RECT 11.500 92.820 12.000 93.320 ;
        RECT 13.200 83.340 13.300 83.840 ;
        RECT 11.500 85.940 11.600 86.440 ;
        RECT 3.400 89.840 3.500 90.340 ;
        RECT 4.700 89.840 4.800 90.340 ;
        RECT 5.100 89.840 5.200 90.340 ;
        RECT 6.400 89.840 6.500 90.340 ;
        RECT 3.400 87.240 3.500 87.740 ;
        RECT 4.700 87.240 4.800 87.740 ;
        RECT 5.100 87.240 5.200 87.740 ;
        RECT 6.400 87.240 6.500 87.740 ;
        RECT 3.400 85.940 3.500 86.440 ;
        RECT 4.700 85.940 4.800 86.440 ;
        RECT 5.100 85.940 5.200 86.440 ;
        RECT 6.400 85.940 6.500 86.440 ;
        RECT 3.000 84.640 3.100 85.140 ;
        RECT 3.400 84.640 3.500 85.140 ;
        RECT 1.300 91.140 1.400 91.640 ;
        RECT 1.700 91.140 1.800 91.640 ;
        RECT 3.000 91.140 3.100 91.640 ;
        RECT 3.400 91.140 3.500 91.640 ;
        RECT 4.700 91.140 4.800 91.640 ;
        RECT 5.100 91.140 5.200 91.640 ;
        RECT 6.400 91.140 6.500 91.640 ;
        RECT 4.700 84.640 4.800 85.140 ;
        RECT 5.100 84.640 5.200 85.140 ;
        RECT 1.300 88.540 1.400 89.040 ;
        RECT 1.700 88.540 1.800 89.040 ;
        RECT 3.000 88.540 3.100 89.040 ;
        RECT 3.400 88.540 3.500 89.040 ;
        RECT 4.700 88.540 4.800 89.040 ;
        RECT 5.100 88.540 5.200 89.040 ;
        RECT 1.300 83.340 1.400 83.840 ;
        RECT 1.700 83.340 1.800 83.840 ;
        RECT 3.000 83.340 3.100 83.840 ;
        RECT 3.400 83.340 3.500 83.840 ;
        RECT 4.700 83.340 4.800 83.840 ;
        RECT 5.100 83.340 5.200 83.840 ;
        RECT 6.400 83.340 6.500 83.840 ;
        RECT 6.400 88.540 6.500 89.040 ;
        RECT 6.400 84.640 6.500 85.140 ;
        RECT 1.300 84.640 1.400 85.140 ;
        RECT 1.700 84.640 1.800 85.140 ;
        RECT 1.300 85.940 1.400 86.440 ;
        RECT 1.700 85.940 1.800 86.440 ;
        RECT 3.000 85.940 3.100 86.440 ;
        RECT 1.300 92.820 1.800 93.320 ;
        RECT 3.000 92.820 3.500 93.320 ;
        RECT 4.700 92.820 5.200 93.320 ;
        RECT 1.300 87.240 1.400 87.740 ;
        RECT 1.700 87.240 1.800 87.740 ;
        RECT 3.000 87.240 3.100 87.740 ;
        RECT 1.300 89.840 1.400 90.340 ;
        RECT 1.700 89.840 1.800 90.340 ;
        RECT 3.000 89.840 3.100 90.340 ;
        RECT 3.000 78.140 3.100 78.640 ;
        RECT 4.700 75.540 4.800 76.040 ;
        RECT 5.100 75.540 5.200 76.040 ;
        RECT 6.400 75.540 6.500 76.040 ;
        RECT 3.000 74.240 3.100 74.740 ;
        RECT 3.400 74.240 3.500 74.740 ;
        RECT 4.700 74.240 4.800 74.740 ;
        RECT 5.100 74.240 5.200 74.740 ;
        RECT 1.700 76.840 1.800 77.340 ;
        RECT 3.000 76.840 3.100 77.340 ;
        RECT 3.400 76.840 3.500 77.340 ;
        RECT 4.700 76.840 4.800 77.340 ;
        RECT 5.100 76.840 5.200 77.340 ;
        RECT 1.300 82.040 1.400 82.540 ;
        RECT 1.700 82.040 1.800 82.540 ;
        RECT 3.000 82.040 3.100 82.540 ;
        RECT 3.400 82.040 3.500 82.540 ;
        RECT 4.700 82.040 4.800 82.540 ;
        RECT 5.100 82.040 5.200 82.540 ;
        RECT 6.400 82.040 6.500 82.540 ;
        RECT 6.400 74.240 6.500 74.740 ;
        RECT 3.400 78.140 3.500 78.640 ;
        RECT 1.300 79.440 1.400 79.940 ;
        RECT 1.700 79.440 1.800 79.940 ;
        RECT 3.000 79.440 3.100 79.940 ;
        RECT 3.000 72.940 3.100 73.440 ;
        RECT 3.400 72.940 3.500 73.440 ;
        RECT 4.700 72.940 4.800 73.440 ;
        RECT 5.100 72.940 5.200 73.440 ;
        RECT 1.300 76.840 1.400 77.340 ;
        RECT 3.400 79.440 3.500 79.940 ;
        RECT 4.700 79.440 4.800 79.940 ;
        RECT 5.100 79.440 5.200 79.940 ;
        RECT 6.400 79.440 6.500 79.940 ;
        RECT 4.700 78.140 4.800 78.640 ;
        RECT 5.100 78.140 5.200 78.640 ;
        RECT 6.400 76.840 6.500 77.340 ;
        RECT 6.400 78.140 6.500 78.640 ;
        RECT 1.300 72.940 1.400 73.440 ;
        RECT 1.700 72.940 1.800 73.440 ;
        RECT 1.300 74.240 1.400 74.740 ;
        RECT 1.700 74.240 1.800 74.740 ;
        RECT 1.300 75.540 1.400 76.040 ;
        RECT 1.700 75.540 1.800 76.040 ;
        RECT 3.000 75.540 3.100 76.040 ;
        RECT 1.300 71.640 1.400 72.140 ;
        RECT 1.700 71.640 1.800 72.140 ;
        RECT 3.000 71.640 3.100 72.140 ;
        RECT 3.400 71.640 3.500 72.140 ;
        RECT 4.700 71.640 4.800 72.140 ;
        RECT 5.100 71.640 5.200 72.140 ;
        RECT 6.400 71.640 6.500 72.140 ;
        RECT 6.400 72.940 6.500 73.440 ;
        RECT 3.400 75.540 3.500 76.040 ;
        RECT 1.300 78.140 1.400 78.640 ;
        RECT 1.700 78.140 1.800 78.640 ;
        RECT 8.100 82.040 8.200 82.540 ;
        RECT 8.500 82.040 8.600 82.540 ;
        RECT 9.800 82.040 9.900 82.540 ;
        RECT 10.200 82.040 10.300 82.540 ;
        RECT 11.500 82.040 11.600 82.540 ;
        RECT 9.800 78.140 9.900 78.640 ;
        RECT 11.500 72.940 11.600 73.440 ;
        RECT 11.900 72.940 12.000 73.440 ;
        RECT 10.200 78.140 10.300 78.640 ;
        RECT 8.100 74.240 8.200 74.740 ;
        RECT 8.100 75.540 8.200 76.040 ;
        RECT 8.500 75.540 8.600 76.040 ;
        RECT 9.800 75.540 9.900 76.040 ;
        RECT 10.200 75.540 10.300 76.040 ;
        RECT 11.500 75.540 11.600 76.040 ;
        RECT 11.900 75.540 12.000 76.040 ;
        RECT 13.200 75.540 13.300 76.040 ;
        RECT 11.500 78.140 11.600 78.640 ;
        RECT 8.500 79.440 8.600 79.940 ;
        RECT 9.800 79.440 9.900 79.940 ;
        RECT 10.200 79.440 10.300 79.940 ;
        RECT 11.500 79.440 11.600 79.940 ;
        RECT 11.900 82.040 12.000 82.540 ;
        RECT 13.200 82.040 13.300 82.540 ;
        RECT 11.900 79.440 12.000 79.940 ;
        RECT 13.200 79.440 13.300 79.940 ;
        RECT 8.100 76.840 8.200 77.340 ;
        RECT 8.500 76.840 8.600 77.340 ;
        RECT 9.800 76.840 9.900 77.340 ;
        RECT 10.200 76.840 10.300 77.340 ;
        RECT 13.200 72.940 13.300 73.440 ;
        RECT 11.500 76.840 11.600 77.340 ;
        RECT 11.900 76.840 12.000 77.340 ;
        RECT 13.200 76.840 13.300 77.340 ;
        RECT 8.500 74.240 8.600 74.740 ;
        RECT 9.800 74.240 9.900 74.740 ;
        RECT 8.100 72.940 8.200 73.440 ;
        RECT 8.500 72.940 8.600 73.440 ;
        RECT 9.800 72.940 9.900 73.440 ;
        RECT 10.200 72.940 10.300 73.440 ;
        RECT 10.200 74.240 10.300 74.740 ;
        RECT 11.500 74.240 11.600 74.740 ;
        RECT 11.900 74.240 12.000 74.740 ;
        RECT 13.200 74.240 13.300 74.740 ;
        RECT 8.100 79.440 8.200 79.940 ;
        RECT 11.900 78.140 12.000 78.640 ;
        RECT 8.100 71.640 8.200 72.140 ;
        RECT 8.500 71.640 8.600 72.140 ;
        RECT 9.800 71.640 9.900 72.140 ;
        RECT 10.200 71.640 10.300 72.140 ;
        RECT 11.500 71.640 11.600 72.140 ;
        RECT 11.900 71.640 12.000 72.140 ;
        RECT 13.200 71.640 13.300 72.140 ;
        RECT 13.200 78.140 13.300 78.640 ;
        RECT 8.100 78.140 8.200 78.640 ;
        RECT 8.500 78.140 8.600 78.640 ;
        RECT 6.800 58.640 6.900 59.140 ;
        RECT 6.800 62.540 6.900 63.040 ;
        RECT 6.800 56.040 6.900 56.540 ;
        RECT 6.800 65.140 6.900 65.640 ;
        RECT 6.800 67.740 6.900 68.240 ;
        RECT 6.800 63.840 6.900 64.340 ;
        RECT 6.800 52.140 6.900 52.640 ;
        RECT 6.800 50.840 6.900 51.340 ;
        RECT 6.800 70.340 6.900 70.840 ;
        RECT 6.800 61.240 6.900 61.740 ;
        RECT 6.800 66.440 6.900 66.940 ;
        RECT 6.800 53.440 6.900 53.940 ;
        RECT 6.800 59.940 6.900 60.440 ;
        RECT 6.800 49.540 6.900 50.040 ;
        RECT 6.800 54.740 6.900 55.240 ;
        RECT 6.800 48.240 6.900 48.740 ;
        RECT 10.200 67.740 10.300 68.240 ;
        RECT 11.500 67.740 11.600 68.240 ;
        RECT 11.900 67.740 12.000 68.240 ;
        RECT 13.200 67.740 13.300 68.240 ;
        RECT 8.500 62.540 8.600 63.040 ;
        RECT 9.800 62.540 9.900 63.040 ;
        RECT 10.200 62.540 10.300 63.040 ;
        RECT 11.500 62.540 11.600 63.040 ;
        RECT 11.900 62.540 12.000 63.040 ;
        RECT 13.200 62.540 13.300 63.040 ;
        RECT 8.100 65.140 8.200 65.640 ;
        RECT 8.100 63.840 8.200 64.340 ;
        RECT 8.500 63.840 8.600 64.340 ;
        RECT 9.800 63.840 9.900 64.340 ;
        RECT 10.200 63.840 10.300 64.340 ;
        RECT 11.500 63.840 11.600 64.340 ;
        RECT 11.900 63.840 12.000 64.340 ;
        RECT 13.200 63.840 13.300 64.340 ;
        RECT 8.500 65.140 8.600 65.640 ;
        RECT 9.800 65.140 9.900 65.640 ;
        RECT 10.200 65.140 10.300 65.640 ;
        RECT 8.100 70.340 8.200 70.840 ;
        RECT 8.500 70.340 8.600 70.840 ;
        RECT 9.800 70.340 9.900 70.840 ;
        RECT 10.200 70.340 10.300 70.840 ;
        RECT 11.500 70.340 11.600 70.840 ;
        RECT 11.900 70.340 12.000 70.840 ;
        RECT 13.200 70.340 13.300 70.840 ;
        RECT 11.500 65.140 11.600 65.640 ;
        RECT 8.100 61.240 8.200 61.740 ;
        RECT 8.500 61.240 8.600 61.740 ;
        RECT 9.800 61.240 9.900 61.740 ;
        RECT 11.900 65.140 12.000 65.640 ;
        RECT 8.100 66.440 8.200 66.940 ;
        RECT 8.500 66.440 8.600 66.940 ;
        RECT 9.800 66.440 9.900 66.940 ;
        RECT 10.200 66.440 10.300 66.940 ;
        RECT 11.500 66.440 11.600 66.940 ;
        RECT 11.900 66.440 12.000 66.940 ;
        RECT 13.200 66.440 13.300 66.940 ;
        RECT 13.200 65.140 13.300 65.640 ;
        RECT 8.100 62.540 8.200 63.040 ;
        RECT 8.100 59.940 8.200 60.440 ;
        RECT 8.500 59.940 8.600 60.440 ;
        RECT 9.800 59.940 9.900 60.440 ;
        RECT 10.200 59.940 10.300 60.440 ;
        RECT 11.500 59.940 11.600 60.440 ;
        RECT 11.900 59.940 12.000 60.440 ;
        RECT 13.200 59.940 13.300 60.440 ;
        RECT 10.200 61.240 10.300 61.740 ;
        RECT 11.500 61.240 11.600 61.740 ;
        RECT 11.900 61.240 12.000 61.740 ;
        RECT 13.200 61.240 13.300 61.740 ;
        RECT 8.100 67.740 8.200 68.240 ;
        RECT 8.500 67.740 8.600 68.240 ;
        RECT 9.800 67.740 9.900 68.240 ;
        RECT 3.400 70.340 3.500 70.840 ;
        RECT 4.700 70.340 4.800 70.840 ;
        RECT 5.100 70.340 5.200 70.840 ;
        RECT 6.400 70.340 6.500 70.840 ;
        RECT 6.400 62.540 6.500 63.040 ;
        RECT 3.000 62.540 3.100 63.040 ;
        RECT 3.400 62.540 3.500 63.040 ;
        RECT 4.700 62.540 4.800 63.040 ;
        RECT 1.300 65.140 1.400 65.640 ;
        RECT 1.700 65.140 1.800 65.640 ;
        RECT 3.000 65.140 3.100 65.640 ;
        RECT 1.300 67.740 1.400 68.240 ;
        RECT 1.700 67.740 1.800 68.240 ;
        RECT 1.300 63.840 1.400 64.340 ;
        RECT 1.700 63.840 1.800 64.340 ;
        RECT 3.000 63.840 3.100 64.340 ;
        RECT 1.300 66.440 1.400 66.940 ;
        RECT 1.700 66.440 1.800 66.940 ;
        RECT 3.000 66.440 3.100 66.940 ;
        RECT 3.400 66.440 3.500 66.940 ;
        RECT 4.700 66.440 4.800 66.940 ;
        RECT 5.100 66.440 5.200 66.940 ;
        RECT 6.400 66.440 6.500 66.940 ;
        RECT 3.400 63.840 3.500 64.340 ;
        RECT 4.700 63.840 4.800 64.340 ;
        RECT 5.100 63.840 5.200 64.340 ;
        RECT 6.400 63.840 6.500 64.340 ;
        RECT 3.000 67.740 3.100 68.240 ;
        RECT 3.400 67.740 3.500 68.240 ;
        RECT 4.700 67.740 4.800 68.240 ;
        RECT 5.100 67.740 5.200 68.240 ;
        RECT 6.400 67.740 6.500 68.240 ;
        RECT 1.300 59.940 1.400 60.440 ;
        RECT 1.700 59.940 1.800 60.440 ;
        RECT 3.000 59.940 3.100 60.440 ;
        RECT 3.400 59.940 3.500 60.440 ;
        RECT 4.700 59.940 4.800 60.440 ;
        RECT 5.100 59.940 5.200 60.440 ;
        RECT 6.400 59.940 6.500 60.440 ;
        RECT 3.400 65.140 3.500 65.640 ;
        RECT 4.700 65.140 4.800 65.640 ;
        RECT 5.100 65.140 5.200 65.640 ;
        RECT 6.400 65.140 6.500 65.640 ;
        RECT 5.100 62.540 5.200 63.040 ;
        RECT 1.300 61.240 1.400 61.740 ;
        RECT 1.700 61.240 1.800 61.740 ;
        RECT 3.000 61.240 3.100 61.740 ;
        RECT 3.400 61.240 3.500 61.740 ;
        RECT 4.700 61.240 4.800 61.740 ;
        RECT 5.100 61.240 5.200 61.740 ;
        RECT 6.400 61.240 6.500 61.740 ;
        RECT 1.300 70.340 1.400 70.840 ;
        RECT 1.700 70.340 1.800 70.840 ;
        RECT 1.300 62.540 1.400 63.040 ;
        RECT 1.700 62.540 1.800 63.040 ;
        RECT 3.000 70.340 3.100 70.840 ;
        RECT 3.400 52.140 3.500 52.640 ;
        RECT 4.700 52.140 4.800 52.640 ;
        RECT 5.100 52.140 5.200 52.640 ;
        RECT 1.300 48.240 1.400 48.740 ;
        RECT 1.700 48.240 1.800 48.740 ;
        RECT 1.300 49.540 1.400 50.040 ;
        RECT 1.700 49.540 1.800 50.040 ;
        RECT 1.300 50.840 1.400 51.340 ;
        RECT 1.700 50.840 1.800 51.340 ;
        RECT 3.000 50.840 3.100 51.340 ;
        RECT 3.400 50.840 3.500 51.340 ;
        RECT 1.300 53.440 1.400 53.940 ;
        RECT 1.700 53.440 1.800 53.940 ;
        RECT 3.000 53.440 3.100 53.940 ;
        RECT 3.400 53.440 3.500 53.940 ;
        RECT 4.700 53.440 4.800 53.940 ;
        RECT 5.100 53.440 5.200 53.940 ;
        RECT 6.400 53.440 6.500 53.940 ;
        RECT 5.100 58.640 5.200 59.140 ;
        RECT 6.400 58.640 6.500 59.140 ;
        RECT 1.300 58.640 1.400 59.140 ;
        RECT 3.000 48.240 3.100 48.740 ;
        RECT 3.400 48.240 3.500 48.740 ;
        RECT 4.700 48.240 4.800 48.740 ;
        RECT 5.100 48.240 5.200 48.740 ;
        RECT 1.300 52.140 1.400 52.640 ;
        RECT 3.400 56.040 3.500 56.540 ;
        RECT 3.000 49.540 3.100 50.040 ;
        RECT 3.400 49.540 3.500 50.040 ;
        RECT 4.700 49.540 4.800 50.040 ;
        RECT 6.400 52.140 6.500 52.640 ;
        RECT 4.700 56.040 4.800 56.540 ;
        RECT 4.700 50.840 4.800 51.340 ;
        RECT 5.100 50.840 5.200 51.340 ;
        RECT 1.300 56.040 1.400 56.540 ;
        RECT 1.700 56.040 1.800 56.540 ;
        RECT 3.000 56.040 3.100 56.540 ;
        RECT 6.400 50.840 6.500 51.340 ;
        RECT 5.100 56.040 5.200 56.540 ;
        RECT 6.400 56.040 6.500 56.540 ;
        RECT 1.700 58.640 1.800 59.140 ;
        RECT 5.100 49.540 5.200 50.040 ;
        RECT 6.400 49.540 6.500 50.040 ;
        RECT 3.000 58.640 3.100 59.140 ;
        RECT 1.300 54.740 1.400 55.240 ;
        RECT 1.700 54.740 1.800 55.240 ;
        RECT 3.000 54.740 3.100 55.240 ;
        RECT 3.400 54.740 3.500 55.240 ;
        RECT 4.700 54.740 4.800 55.240 ;
        RECT 5.100 54.740 5.200 55.240 ;
        RECT 6.400 54.740 6.500 55.240 ;
        RECT 3.400 58.640 3.500 59.140 ;
        RECT 4.700 58.640 4.800 59.140 ;
        RECT 1.700 52.140 1.800 52.640 ;
        RECT 6.400 48.240 6.500 48.740 ;
        RECT 3.000 52.140 3.100 52.640 ;
        RECT 11.900 58.640 12.000 59.140 ;
        RECT 8.500 56.040 8.600 56.540 ;
        RECT 8.100 52.140 8.200 52.640 ;
        RECT 8.500 52.140 8.600 52.640 ;
        RECT 9.800 52.140 9.900 52.640 ;
        RECT 10.200 52.140 10.300 52.640 ;
        RECT 11.500 52.140 11.600 52.640 ;
        RECT 9.800 54.740 9.900 55.240 ;
        RECT 13.200 53.440 13.300 53.940 ;
        RECT 8.100 53.440 8.200 53.940 ;
        RECT 8.500 53.440 8.600 53.940 ;
        RECT 9.800 53.440 9.900 53.940 ;
        RECT 11.900 52.140 12.000 52.640 ;
        RECT 13.200 52.140 13.300 52.640 ;
        RECT 10.200 53.440 10.300 53.940 ;
        RECT 9.800 56.040 9.900 56.540 ;
        RECT 10.200 56.040 10.300 56.540 ;
        RECT 11.900 48.240 12.000 48.740 ;
        RECT 8.100 58.640 8.200 59.140 ;
        RECT 8.100 50.840 8.200 51.340 ;
        RECT 8.500 50.840 8.600 51.340 ;
        RECT 9.800 50.840 9.900 51.340 ;
        RECT 10.200 50.840 10.300 51.340 ;
        RECT 11.500 50.840 11.600 51.340 ;
        RECT 11.900 50.840 12.000 51.340 ;
        RECT 10.200 54.740 10.300 55.240 ;
        RECT 11.500 54.740 11.600 55.240 ;
        RECT 11.900 54.740 12.000 55.240 ;
        RECT 13.200 54.740 13.300 55.240 ;
        RECT 8.100 56.040 8.200 56.540 ;
        RECT 8.100 49.540 8.200 50.040 ;
        RECT 8.500 58.640 8.600 59.140 ;
        RECT 9.800 58.640 9.900 59.140 ;
        RECT 10.200 58.640 10.300 59.140 ;
        RECT 11.500 58.640 11.600 59.140 ;
        RECT 8.500 49.540 8.600 50.040 ;
        RECT 9.800 49.540 9.900 50.040 ;
        RECT 10.200 49.540 10.300 50.040 ;
        RECT 11.500 49.540 11.600 50.040 ;
        RECT 11.500 53.440 11.600 53.940 ;
        RECT 11.900 49.540 12.000 50.040 ;
        RECT 13.200 49.540 13.300 50.040 ;
        RECT 13.200 50.840 13.300 51.340 ;
        RECT 13.200 58.640 13.300 59.140 ;
        RECT 11.500 56.040 11.600 56.540 ;
        RECT 8.100 54.740 8.200 55.240 ;
        RECT 8.500 54.740 8.600 55.240 ;
        RECT 13.200 48.240 13.300 48.740 ;
        RECT 11.900 56.040 12.000 56.540 ;
        RECT 13.200 56.040 13.300 56.540 ;
        RECT 11.900 53.440 12.000 53.940 ;
        RECT 8.100 48.240 8.200 48.740 ;
        RECT 8.500 48.240 8.600 48.740 ;
        RECT 9.800 48.240 9.900 48.740 ;
        RECT 10.200 48.240 10.300 48.740 ;
        RECT 11.500 48.240 11.600 48.740 ;
        RECT 20.400 67.740 20.500 68.240 ;
        RECT 20.400 49.540 20.500 50.040 ;
        RECT 20.400 50.840 20.500 51.340 ;
        RECT 20.400 58.640 20.500 59.140 ;
        RECT 20.400 48.240 20.500 48.740 ;
        RECT 20.400 59.940 20.500 60.440 ;
        RECT 20.400 66.440 20.500 66.940 ;
        RECT 20.400 53.440 20.500 53.940 ;
        RECT 20.400 70.340 20.500 70.840 ;
        RECT 20.400 52.140 20.500 52.640 ;
        RECT 20.400 65.140 20.500 65.640 ;
        RECT 20.400 62.540 20.500 63.040 ;
        RECT 20.400 61.240 20.500 61.740 ;
        RECT 20.400 54.740 20.500 55.240 ;
        RECT 20.400 63.840 20.500 64.340 ;
        RECT 20.400 56.040 20.500 56.540 ;
        RECT 21.700 67.740 21.800 68.240 ;
        RECT 25.100 61.240 25.200 61.740 ;
        RECT 21.700 66.440 21.800 66.940 ;
        RECT 22.100 66.440 22.200 66.940 ;
        RECT 25.500 61.240 25.600 61.740 ;
        RECT 21.700 59.940 21.800 60.440 ;
        RECT 22.100 59.940 22.200 60.440 ;
        RECT 23.400 59.940 23.500 60.440 ;
        RECT 23.800 59.940 23.900 60.440 ;
        RECT 25.100 59.940 25.200 60.440 ;
        RECT 26.800 61.240 26.900 61.740 ;
        RECT 21.700 70.340 21.800 70.840 ;
        RECT 22.100 70.340 22.200 70.840 ;
        RECT 23.400 70.340 23.500 70.840 ;
        RECT 23.800 70.340 23.900 70.840 ;
        RECT 25.100 70.340 25.200 70.840 ;
        RECT 25.500 70.340 25.600 70.840 ;
        RECT 25.500 59.940 25.600 60.440 ;
        RECT 23.400 66.440 23.500 66.940 ;
        RECT 23.800 66.440 23.900 66.940 ;
        RECT 25.100 66.440 25.200 66.940 ;
        RECT 25.500 66.440 25.600 66.940 ;
        RECT 26.800 66.440 26.900 66.940 ;
        RECT 22.100 67.740 22.200 68.240 ;
        RECT 26.800 70.340 26.900 70.840 ;
        RECT 25.100 67.740 25.200 68.240 ;
        RECT 25.500 67.740 25.600 68.240 ;
        RECT 21.700 62.540 21.800 63.040 ;
        RECT 22.100 62.540 22.200 63.040 ;
        RECT 23.400 62.540 23.500 63.040 ;
        RECT 23.800 62.540 23.900 63.040 ;
        RECT 25.100 62.540 25.200 63.040 ;
        RECT 25.500 62.540 25.600 63.040 ;
        RECT 26.800 62.540 26.900 63.040 ;
        RECT 26.800 67.740 26.900 68.240 ;
        RECT 21.700 61.240 21.800 61.740 ;
        RECT 22.100 61.240 22.200 61.740 ;
        RECT 23.400 61.240 23.500 61.740 ;
        RECT 23.800 61.240 23.900 61.740 ;
        RECT 23.400 67.740 23.500 68.240 ;
        RECT 21.700 65.140 21.800 65.640 ;
        RECT 22.100 65.140 22.200 65.640 ;
        RECT 23.400 65.140 23.500 65.640 ;
        RECT 23.800 65.140 23.900 65.640 ;
        RECT 25.100 65.140 25.200 65.640 ;
        RECT 25.500 65.140 25.600 65.640 ;
        RECT 26.800 65.140 26.900 65.640 ;
        RECT 23.800 67.740 23.900 68.240 ;
        RECT 21.700 63.840 21.800 64.340 ;
        RECT 22.100 63.840 22.200 64.340 ;
        RECT 26.800 59.940 26.900 60.440 ;
        RECT 23.400 63.840 23.500 64.340 ;
        RECT 23.800 63.840 23.900 64.340 ;
        RECT 25.100 63.840 25.200 64.340 ;
        RECT 25.500 63.840 25.600 64.340 ;
        RECT 26.800 63.840 26.900 64.340 ;
        RECT 17.000 63.840 17.100 64.340 ;
        RECT 18.300 63.840 18.400 64.340 ;
        RECT 18.700 63.840 18.800 64.340 ;
        RECT 14.900 65.140 15.000 65.640 ;
        RECT 15.300 65.140 15.400 65.640 ;
        RECT 16.600 65.140 16.700 65.640 ;
        RECT 20.000 59.940 20.100 60.440 ;
        RECT 15.300 61.240 15.400 61.740 ;
        RECT 14.900 66.440 15.000 66.940 ;
        RECT 15.300 66.440 15.400 66.940 ;
        RECT 16.600 66.440 16.700 66.940 ;
        RECT 17.000 66.440 17.100 66.940 ;
        RECT 17.000 65.140 17.100 65.640 ;
        RECT 18.300 65.140 18.400 65.640 ;
        RECT 18.300 66.440 18.400 66.940 ;
        RECT 18.700 65.140 18.800 65.640 ;
        RECT 20.000 65.140 20.100 65.640 ;
        RECT 18.700 66.440 18.800 66.940 ;
        RECT 17.000 61.240 17.100 61.740 ;
        RECT 18.300 61.240 18.400 61.740 ;
        RECT 18.700 61.240 18.800 61.740 ;
        RECT 18.300 62.540 18.400 63.040 ;
        RECT 18.700 62.540 18.800 63.040 ;
        RECT 20.000 62.540 20.100 63.040 ;
        RECT 20.000 66.440 20.100 66.940 ;
        RECT 16.600 67.740 16.700 68.240 ;
        RECT 17.000 67.740 17.100 68.240 ;
        RECT 18.300 67.740 18.400 68.240 ;
        RECT 18.700 67.740 18.800 68.240 ;
        RECT 20.000 67.740 20.100 68.240 ;
        RECT 14.900 67.740 15.000 68.240 ;
        RECT 14.900 62.540 15.000 63.040 ;
        RECT 20.000 61.240 20.100 61.740 ;
        RECT 15.300 62.540 15.400 63.040 ;
        RECT 16.600 62.540 16.700 63.040 ;
        RECT 14.900 70.340 15.000 70.840 ;
        RECT 15.300 70.340 15.400 70.840 ;
        RECT 16.600 70.340 16.700 70.840 ;
        RECT 17.000 70.340 17.100 70.840 ;
        RECT 18.300 70.340 18.400 70.840 ;
        RECT 18.700 70.340 18.800 70.840 ;
        RECT 20.000 70.340 20.100 70.840 ;
        RECT 17.000 62.540 17.100 63.040 ;
        RECT 15.300 67.740 15.400 68.240 ;
        RECT 14.900 59.940 15.000 60.440 ;
        RECT 15.300 59.940 15.400 60.440 ;
        RECT 20.000 63.840 20.100 64.340 ;
        RECT 16.600 59.940 16.700 60.440 ;
        RECT 17.000 59.940 17.100 60.440 ;
        RECT 18.300 59.940 18.400 60.440 ;
        RECT 18.700 59.940 18.800 60.440 ;
        RECT 14.900 61.240 15.000 61.740 ;
        RECT 16.600 61.240 16.700 61.740 ;
        RECT 14.900 63.840 15.000 64.340 ;
        RECT 15.300 63.840 15.400 64.340 ;
        RECT 16.600 63.840 16.700 64.340 ;
        RECT 16.600 50.840 16.700 51.340 ;
        RECT 15.300 52.140 15.400 52.640 ;
        RECT 16.600 52.140 16.700 52.640 ;
        RECT 17.000 52.140 17.100 52.640 ;
        RECT 17.000 50.840 17.100 51.340 ;
        RECT 18.300 50.840 18.400 51.340 ;
        RECT 18.700 50.840 18.800 51.340 ;
        RECT 20.000 50.840 20.100 51.340 ;
        RECT 20.000 49.540 20.100 50.040 ;
        RECT 18.300 49.540 18.400 50.040 ;
        RECT 18.700 49.540 18.800 50.040 ;
        RECT 14.900 50.840 15.000 51.340 ;
        RECT 14.900 58.640 15.000 59.140 ;
        RECT 15.300 58.640 15.400 59.140 ;
        RECT 16.600 58.640 16.700 59.140 ;
        RECT 17.000 58.640 17.100 59.140 ;
        RECT 18.300 58.640 18.400 59.140 ;
        RECT 14.900 53.440 15.000 53.940 ;
        RECT 18.700 58.640 18.800 59.140 ;
        RECT 20.000 58.640 20.100 59.140 ;
        RECT 15.300 50.840 15.400 51.340 ;
        RECT 14.900 52.140 15.000 52.640 ;
        RECT 14.900 48.240 15.000 48.740 ;
        RECT 15.300 48.240 15.400 48.740 ;
        RECT 14.900 54.740 15.000 55.240 ;
        RECT 15.300 54.740 15.400 55.240 ;
        RECT 16.600 54.740 16.700 55.240 ;
        RECT 17.000 54.740 17.100 55.240 ;
        RECT 18.300 54.740 18.400 55.240 ;
        RECT 18.700 54.740 18.800 55.240 ;
        RECT 20.000 54.740 20.100 55.240 ;
        RECT 16.600 48.240 16.700 48.740 ;
        RECT 17.000 48.240 17.100 48.740 ;
        RECT 18.300 48.240 18.400 48.740 ;
        RECT 18.700 48.240 18.800 48.740 ;
        RECT 15.300 53.440 15.400 53.940 ;
        RECT 16.600 53.440 16.700 53.940 ;
        RECT 14.900 49.540 15.000 50.040 ;
        RECT 15.300 49.540 15.400 50.040 ;
        RECT 16.600 49.540 16.700 50.040 ;
        RECT 17.000 49.540 17.100 50.040 ;
        RECT 17.000 53.440 17.100 53.940 ;
        RECT 18.300 53.440 18.400 53.940 ;
        RECT 14.900 56.040 15.000 56.540 ;
        RECT 15.300 56.040 15.400 56.540 ;
        RECT 16.600 56.040 16.700 56.540 ;
        RECT 17.000 56.040 17.100 56.540 ;
        RECT 18.300 56.040 18.400 56.540 ;
        RECT 18.700 56.040 18.800 56.540 ;
        RECT 20.000 56.040 20.100 56.540 ;
        RECT 18.300 52.140 18.400 52.640 ;
        RECT 18.700 52.140 18.800 52.640 ;
        RECT 20.000 52.140 20.100 52.640 ;
        RECT 18.700 53.440 18.800 53.940 ;
        RECT 20.000 53.440 20.100 53.940 ;
        RECT 20.000 48.240 20.100 48.740 ;
        RECT 23.400 50.840 23.500 51.340 ;
        RECT 23.800 50.840 23.900 51.340 ;
        RECT 25.100 50.840 25.200 51.340 ;
        RECT 22.100 49.540 22.200 50.040 ;
        RECT 23.400 49.540 23.500 50.040 ;
        RECT 23.400 53.440 23.500 53.940 ;
        RECT 23.800 49.540 23.900 50.040 ;
        RECT 21.700 48.240 21.800 48.740 ;
        RECT 22.100 48.240 22.200 48.740 ;
        RECT 23.800 48.240 23.900 48.740 ;
        RECT 25.100 48.240 25.200 48.740 ;
        RECT 25.500 48.240 25.600 48.740 ;
        RECT 23.400 48.240 23.500 48.740 ;
        RECT 25.500 50.840 25.600 51.340 ;
        RECT 26.800 50.840 26.900 51.340 ;
        RECT 23.800 53.440 23.900 53.940 ;
        RECT 25.500 53.440 25.600 53.940 ;
        RECT 26.800 53.440 26.900 53.940 ;
        RECT 25.100 49.540 25.200 50.040 ;
        RECT 25.500 49.540 25.600 50.040 ;
        RECT 26.800 49.540 26.900 50.040 ;
        RECT 21.700 53.440 21.800 53.940 ;
        RECT 21.700 54.740 21.800 55.240 ;
        RECT 22.100 54.740 22.200 55.240 ;
        RECT 23.400 54.740 23.500 55.240 ;
        RECT 22.100 53.440 22.200 53.940 ;
        RECT 23.800 54.740 23.900 55.240 ;
        RECT 25.100 54.740 25.200 55.240 ;
        RECT 25.500 54.740 25.600 55.240 ;
        RECT 21.700 52.140 21.800 52.640 ;
        RECT 22.100 52.140 22.200 52.640 ;
        RECT 23.400 52.140 23.500 52.640 ;
        RECT 23.800 52.140 23.900 52.640 ;
        RECT 25.100 52.140 25.200 52.640 ;
        RECT 25.500 52.140 25.600 52.640 ;
        RECT 26.800 52.140 26.900 52.640 ;
        RECT 26.800 54.740 26.900 55.240 ;
        RECT 21.700 58.640 21.800 59.140 ;
        RECT 22.100 58.640 22.200 59.140 ;
        RECT 26.800 48.240 26.900 48.740 ;
        RECT 23.400 58.640 23.500 59.140 ;
        RECT 23.800 58.640 23.900 59.140 ;
        RECT 25.100 58.640 25.200 59.140 ;
        RECT 25.500 58.640 25.600 59.140 ;
        RECT 21.700 56.040 21.800 56.540 ;
        RECT 22.100 56.040 22.200 56.540 ;
        RECT 23.400 56.040 23.500 56.540 ;
        RECT 23.800 56.040 23.900 56.540 ;
        RECT 25.100 56.040 25.200 56.540 ;
        RECT 25.500 56.040 25.600 56.540 ;
        RECT 26.800 56.040 26.900 56.540 ;
        RECT 26.800 58.640 26.900 59.140 ;
        RECT 25.100 53.440 25.200 53.940 ;
        RECT 21.700 49.540 21.800 50.040 ;
        RECT 21.700 50.840 21.800 51.340 ;
        RECT 22.100 50.840 22.200 51.340 ;
        RECT 13.600 46.940 13.700 47.440 ;
        RECT 13.600 1.440 13.700 1.940 ;
        RECT 13.600 2.740 13.700 3.240 ;
        RECT 13.600 4.040 13.700 4.540 ;
        RECT 13.600 5.340 13.700 5.840 ;
        RECT 13.600 6.640 13.700 7.140 ;
        RECT 13.600 7.940 13.700 8.440 ;
        RECT 13.600 9.240 13.700 9.740 ;
        RECT 13.600 11.840 13.700 12.340 ;
        RECT 13.600 13.140 13.700 13.640 ;
        RECT 13.600 14.440 13.700 14.940 ;
        RECT 13.600 15.740 13.700 16.240 ;
        RECT 13.600 17.040 13.700 17.540 ;
        RECT 13.600 18.340 13.700 18.840 ;
        RECT 13.600 19.640 13.700 20.140 ;
        RECT 13.600 20.940 13.700 21.440 ;
        RECT 13.600 0.140 13.700 0.640 ;
        RECT 1.300 23.540 1.400 24.040 ;
        RECT 1.700 23.540 1.800 24.040 ;
        RECT 3.000 23.540 3.100 24.040 ;
        RECT 3.400 23.540 3.500 24.040 ;
        RECT 4.700 23.540 4.800 24.040 ;
        RECT 5.100 23.540 5.200 24.040 ;
        RECT 6.400 23.540 6.500 24.040 ;
        RECT 6.800 23.540 6.900 24.040 ;
        RECT 8.100 23.540 8.200 24.040 ;
        RECT 8.500 23.540 8.600 24.040 ;
        RECT 9.800 23.540 9.900 24.040 ;
        RECT 10.200 23.540 10.300 24.040 ;
        RECT 11.500 23.540 11.600 24.040 ;
        RECT 11.900 23.540 12.000 24.040 ;
        RECT 13.200 23.540 13.300 24.040 ;
        RECT 13.600 23.540 13.700 24.040 ;
        RECT 14.900 23.540 15.000 24.040 ;
        RECT 15.300 23.540 15.400 24.040 ;
        RECT 16.600 23.540 16.700 24.040 ;
        RECT 17.000 23.540 17.100 24.040 ;
        RECT 18.300 23.540 18.400 24.040 ;
        RECT 18.700 23.540 18.800 24.040 ;
        RECT 20.000 23.540 20.100 24.040 ;
        RECT 20.400 23.540 20.500 24.040 ;
        RECT 21.700 23.540 21.800 24.040 ;
        RECT 22.100 23.540 22.200 24.040 ;
        RECT 23.400 23.540 23.500 24.040 ;
        RECT 23.800 23.540 23.900 24.040 ;
        RECT 25.100 23.540 25.200 24.040 ;
        RECT 25.500 23.540 25.600 24.040 ;
        RECT 26.800 23.540 26.900 24.040 ;
        RECT 13.600 24.840 13.700 25.340 ;
        RECT 13.600 26.140 13.700 26.640 ;
        RECT 13.600 27.440 13.700 27.940 ;
        RECT 13.600 28.740 13.700 29.240 ;
        RECT 13.600 30.040 13.700 30.540 ;
        RECT 13.600 31.340 13.700 31.840 ;
        RECT 13.600 32.640 13.700 33.140 ;
        RECT 13.600 35.240 13.700 35.740 ;
        RECT 13.600 36.540 13.700 37.040 ;
        RECT 13.600 37.840 13.700 38.340 ;
        RECT 13.600 39.140 13.700 39.640 ;
        RECT 13.600 40.440 13.700 40.940 ;
        RECT 13.600 41.740 13.700 42.240 ;
        RECT 13.600 43.040 13.700 43.540 ;
        RECT 13.600 44.340 13.700 44.840 ;
        RECT 20.400 24.840 20.500 25.340 ;
        RECT 20.400 26.140 20.500 26.640 ;
        RECT 20.400 27.440 20.500 27.940 ;
        RECT 20.400 28.740 20.500 29.240 ;
        RECT 20.400 30.040 20.500 30.540 ;
        RECT 20.400 46.940 20.500 47.440 ;
        RECT 20.400 31.340 20.500 31.840 ;
        RECT 20.400 32.640 20.500 33.140 ;
        RECT 14.900 35.240 15.000 35.740 ;
        RECT 15.300 35.240 15.400 35.740 ;
        RECT 16.600 35.240 16.700 35.740 ;
        RECT 17.000 35.240 17.100 35.740 ;
        RECT 18.300 35.240 18.400 35.740 ;
        RECT 18.700 35.240 18.800 35.740 ;
        RECT 20.000 35.240 20.100 35.740 ;
        RECT 20.400 35.240 20.500 35.740 ;
        RECT 21.700 35.240 21.800 35.740 ;
        RECT 22.100 35.240 22.200 35.740 ;
        RECT 23.400 35.240 23.500 35.740 ;
        RECT 23.800 35.240 23.900 35.740 ;
        RECT 25.100 35.240 25.200 35.740 ;
        RECT 25.500 35.240 25.600 35.740 ;
        RECT 26.800 35.240 26.900 35.740 ;
        RECT 20.400 36.540 20.500 37.040 ;
        RECT 20.400 37.840 20.500 38.340 ;
        RECT 20.400 39.140 20.500 39.640 ;
        RECT 20.400 40.440 20.500 40.940 ;
        RECT 20.400 41.740 20.500 42.240 ;
        RECT 20.400 43.040 20.500 43.540 ;
        RECT 20.400 44.340 20.500 44.840 ;
        RECT 23.800 36.540 23.900 37.040 ;
        RECT 25.100 36.540 25.200 37.040 ;
        RECT 25.500 36.540 25.600 37.040 ;
        RECT 26.800 36.540 26.900 37.040 ;
        RECT 23.800 46.940 23.900 47.440 ;
        RECT 21.700 46.940 21.800 47.440 ;
        RECT 21.700 37.840 21.800 38.340 ;
        RECT 22.100 37.840 22.200 38.340 ;
        RECT 23.400 37.840 23.500 38.340 ;
        RECT 23.800 37.840 23.900 38.340 ;
        RECT 25.100 37.840 25.200 38.340 ;
        RECT 25.500 37.840 25.600 38.340 ;
        RECT 26.800 37.840 26.900 38.340 ;
        RECT 25.100 46.940 25.200 47.440 ;
        RECT 23.400 46.940 23.500 47.440 ;
        RECT 21.700 39.140 21.800 39.640 ;
        RECT 22.100 39.140 22.200 39.640 ;
        RECT 23.400 39.140 23.500 39.640 ;
        RECT 23.800 39.140 23.900 39.640 ;
        RECT 25.100 39.140 25.200 39.640 ;
        RECT 25.500 39.140 25.600 39.640 ;
        RECT 26.800 39.140 26.900 39.640 ;
        RECT 25.500 46.940 25.600 47.440 ;
        RECT 22.100 46.940 22.200 47.440 ;
        RECT 21.700 40.440 21.800 40.940 ;
        RECT 22.100 40.440 22.200 40.940 ;
        RECT 23.400 40.440 23.500 40.940 ;
        RECT 23.800 40.440 23.900 40.940 ;
        RECT 25.100 40.440 25.200 40.940 ;
        RECT 25.500 40.440 25.600 40.940 ;
        RECT 26.800 40.440 26.900 40.940 ;
        RECT 26.800 46.940 26.900 47.440 ;
        RECT 21.700 36.540 21.800 37.040 ;
        RECT 21.700 41.740 21.800 42.240 ;
        RECT 22.100 41.740 22.200 42.240 ;
        RECT 23.400 41.740 23.500 42.240 ;
        RECT 23.800 41.740 23.900 42.240 ;
        RECT 25.100 41.740 25.200 42.240 ;
        RECT 25.500 41.740 25.600 42.240 ;
        RECT 26.800 41.740 26.900 42.240 ;
        RECT 22.100 36.540 22.200 37.040 ;
        RECT 21.700 43.040 21.800 43.540 ;
        RECT 22.100 43.040 22.200 43.540 ;
        RECT 23.400 43.040 23.500 43.540 ;
        RECT 23.800 43.040 23.900 43.540 ;
        RECT 25.100 43.040 25.200 43.540 ;
        RECT 25.500 43.040 25.600 43.540 ;
        RECT 26.800 43.040 26.900 43.540 ;
        RECT 23.400 36.540 23.500 37.040 ;
        RECT 21.700 44.340 21.800 44.840 ;
        RECT 22.100 44.340 22.200 44.840 ;
        RECT 23.400 44.340 23.500 44.840 ;
        RECT 23.800 44.340 23.900 44.840 ;
        RECT 25.100 44.340 25.200 44.840 ;
        RECT 25.500 44.340 25.600 44.840 ;
        RECT 26.800 44.340 26.900 44.840 ;
        RECT 20.000 37.840 20.100 38.340 ;
        RECT 18.300 36.540 18.400 37.040 ;
        RECT 18.700 36.540 18.800 37.040 ;
        RECT 20.000 36.540 20.100 37.040 ;
        RECT 18.700 46.940 18.800 47.440 ;
        RECT 16.600 46.940 16.700 47.440 ;
        RECT 20.000 46.940 20.100 47.440 ;
        RECT 18.300 46.940 18.400 47.440 ;
        RECT 17.000 46.940 17.100 47.440 ;
        RECT 14.900 41.740 15.000 42.240 ;
        RECT 15.300 41.740 15.400 42.240 ;
        RECT 16.600 41.740 16.700 42.240 ;
        RECT 17.000 41.740 17.100 42.240 ;
        RECT 18.300 41.740 18.400 42.240 ;
        RECT 18.700 41.740 18.800 42.240 ;
        RECT 20.000 41.740 20.100 42.240 ;
        RECT 14.900 36.540 15.000 37.040 ;
        RECT 14.900 39.140 15.000 39.640 ;
        RECT 15.300 39.140 15.400 39.640 ;
        RECT 16.600 39.140 16.700 39.640 ;
        RECT 17.000 39.140 17.100 39.640 ;
        RECT 18.300 39.140 18.400 39.640 ;
        RECT 18.700 39.140 18.800 39.640 ;
        RECT 20.000 39.140 20.100 39.640 ;
        RECT 14.900 46.940 15.000 47.440 ;
        RECT 14.900 43.040 15.000 43.540 ;
        RECT 15.300 43.040 15.400 43.540 ;
        RECT 16.600 43.040 16.700 43.540 ;
        RECT 17.000 43.040 17.100 43.540 ;
        RECT 18.300 43.040 18.400 43.540 ;
        RECT 18.700 43.040 18.800 43.540 ;
        RECT 20.000 43.040 20.100 43.540 ;
        RECT 15.300 36.540 15.400 37.040 ;
        RECT 16.600 36.540 16.700 37.040 ;
        RECT 17.000 36.540 17.100 37.040 ;
        RECT 14.900 37.840 15.000 38.340 ;
        RECT 15.300 37.840 15.400 38.340 ;
        RECT 16.600 37.840 16.700 38.340 ;
        RECT 17.000 37.840 17.100 38.340 ;
        RECT 18.300 37.840 18.400 38.340 ;
        RECT 15.300 46.940 15.400 47.440 ;
        RECT 14.900 44.340 15.000 44.840 ;
        RECT 15.300 44.340 15.400 44.840 ;
        RECT 16.600 44.340 16.700 44.840 ;
        RECT 17.000 44.340 17.100 44.840 ;
        RECT 18.300 44.340 18.400 44.840 ;
        RECT 18.700 44.340 18.800 44.840 ;
        RECT 20.000 44.340 20.100 44.840 ;
        RECT 18.700 37.840 18.800 38.340 ;
        RECT 14.900 40.440 15.000 40.940 ;
        RECT 15.300 40.440 15.400 40.940 ;
        RECT 16.600 40.440 16.700 40.940 ;
        RECT 17.000 40.440 17.100 40.940 ;
        RECT 18.300 40.440 18.400 40.940 ;
        RECT 18.700 40.440 18.800 40.940 ;
        RECT 20.000 40.440 20.100 40.940 ;
        RECT 15.300 24.840 15.400 25.340 ;
        RECT 14.900 26.140 15.000 26.640 ;
        RECT 14.900 31.340 15.000 31.840 ;
        RECT 15.300 31.340 15.400 31.840 ;
        RECT 16.600 31.340 16.700 31.840 ;
        RECT 17.000 31.340 17.100 31.840 ;
        RECT 18.300 31.340 18.400 31.840 ;
        RECT 18.700 31.340 18.800 31.840 ;
        RECT 20.000 31.340 20.100 31.840 ;
        RECT 15.300 26.140 15.400 26.640 ;
        RECT 16.600 26.140 16.700 26.640 ;
        RECT 14.900 32.640 15.000 33.140 ;
        RECT 15.300 32.640 15.400 33.140 ;
        RECT 16.600 32.640 16.700 33.140 ;
        RECT 17.000 32.640 17.100 33.140 ;
        RECT 18.300 32.640 18.400 33.140 ;
        RECT 18.700 32.640 18.800 33.140 ;
        RECT 20.000 32.640 20.100 33.140 ;
        RECT 17.000 26.140 17.100 26.640 ;
        RECT 18.300 26.140 18.400 26.640 ;
        RECT 18.700 26.140 18.800 26.640 ;
        RECT 20.000 26.140 20.100 26.640 ;
        RECT 16.600 24.840 16.700 25.340 ;
        RECT 17.000 24.840 17.100 25.340 ;
        RECT 14.900 27.440 15.000 27.940 ;
        RECT 15.300 27.440 15.400 27.940 ;
        RECT 16.600 27.440 16.700 27.940 ;
        RECT 17.000 27.440 17.100 27.940 ;
        RECT 18.300 27.440 18.400 27.940 ;
        RECT 18.700 27.440 18.800 27.940 ;
        RECT 20.000 27.440 20.100 27.940 ;
        RECT 18.300 24.840 18.400 25.340 ;
        RECT 18.700 24.840 18.800 25.340 ;
        RECT 14.900 28.740 15.000 29.240 ;
        RECT 15.300 28.740 15.400 29.240 ;
        RECT 16.600 28.740 16.700 29.240 ;
        RECT 17.000 28.740 17.100 29.240 ;
        RECT 18.300 28.740 18.400 29.240 ;
        RECT 18.700 28.740 18.800 29.240 ;
        RECT 20.000 28.740 20.100 29.240 ;
        RECT 20.000 24.840 20.100 25.340 ;
        RECT 14.900 24.840 15.000 25.340 ;
        RECT 14.900 30.040 15.000 30.540 ;
        RECT 15.300 30.040 15.400 30.540 ;
        RECT 16.600 30.040 16.700 30.540 ;
        RECT 17.000 30.040 17.100 30.540 ;
        RECT 18.300 30.040 18.400 30.540 ;
        RECT 18.700 30.040 18.800 30.540 ;
        RECT 20.000 30.040 20.100 30.540 ;
        RECT 25.100 31.340 25.200 31.840 ;
        RECT 25.500 31.340 25.600 31.840 ;
        RECT 26.800 31.340 26.900 31.840 ;
        RECT 23.800 24.840 23.900 25.340 ;
        RECT 25.100 24.840 25.200 25.340 ;
        RECT 25.500 24.840 25.600 25.340 ;
        RECT 21.700 28.740 21.800 29.240 ;
        RECT 22.100 28.740 22.200 29.240 ;
        RECT 23.400 28.740 23.500 29.240 ;
        RECT 23.800 28.740 23.900 29.240 ;
        RECT 25.100 28.740 25.200 29.240 ;
        RECT 25.500 28.740 25.600 29.240 ;
        RECT 21.700 32.640 21.800 33.140 ;
        RECT 22.100 32.640 22.200 33.140 ;
        RECT 23.400 32.640 23.500 33.140 ;
        RECT 23.800 32.640 23.900 33.140 ;
        RECT 25.100 32.640 25.200 33.140 ;
        RECT 25.500 32.640 25.600 33.140 ;
        RECT 26.800 32.640 26.900 33.140 ;
        RECT 26.800 28.740 26.900 29.240 ;
        RECT 26.800 24.840 26.900 25.340 ;
        RECT 21.700 24.840 21.800 25.340 ;
        RECT 22.100 24.840 22.200 25.340 ;
        RECT 21.700 26.140 21.800 26.640 ;
        RECT 22.100 26.140 22.200 26.640 ;
        RECT 21.700 27.440 21.800 27.940 ;
        RECT 22.100 27.440 22.200 27.940 ;
        RECT 23.400 27.440 23.500 27.940 ;
        RECT 23.800 27.440 23.900 27.940 ;
        RECT 21.700 30.040 21.800 30.540 ;
        RECT 22.100 30.040 22.200 30.540 ;
        RECT 23.400 30.040 23.500 30.540 ;
        RECT 23.800 30.040 23.900 30.540 ;
        RECT 25.100 30.040 25.200 30.540 ;
        RECT 25.500 30.040 25.600 30.540 ;
        RECT 26.800 30.040 26.900 30.540 ;
        RECT 25.100 27.440 25.200 27.940 ;
        RECT 25.500 27.440 25.600 27.940 ;
        RECT 26.800 27.440 26.900 27.940 ;
        RECT 23.400 26.140 23.500 26.640 ;
        RECT 23.800 26.140 23.900 26.640 ;
        RECT 25.100 26.140 25.200 26.640 ;
        RECT 25.500 26.140 25.600 26.640 ;
        RECT 26.800 26.140 26.900 26.640 ;
        RECT 23.400 24.840 23.500 25.340 ;
        RECT 21.700 31.340 21.800 31.840 ;
        RECT 22.100 31.340 22.200 31.840 ;
        RECT 23.400 31.340 23.500 31.840 ;
        RECT 23.800 31.340 23.900 31.840 ;
        RECT 11.500 35.240 11.600 35.740 ;
        RECT 11.900 35.240 12.000 35.740 ;
        RECT 13.200 35.240 13.300 35.740 ;
        RECT 6.800 26.140 6.900 26.640 ;
        RECT 6.800 36.540 6.900 37.040 ;
        RECT 6.800 24.840 6.900 25.340 ;
        RECT 6.800 30.040 6.900 30.540 ;
        RECT 6.800 37.840 6.900 38.340 ;
        RECT 6.800 39.140 6.900 39.640 ;
        RECT 6.800 31.340 6.900 31.840 ;
        RECT 6.800 40.440 6.900 40.940 ;
        RECT 6.800 27.440 6.900 27.940 ;
        RECT 6.800 46.940 6.900 47.440 ;
        RECT 6.800 41.740 6.900 42.240 ;
        RECT 6.800 32.640 6.900 33.140 ;
        RECT 6.800 43.040 6.900 43.540 ;
        RECT 6.800 44.340 6.900 44.840 ;
        RECT 6.800 28.740 6.900 29.240 ;
        RECT 1.300 35.240 1.400 35.740 ;
        RECT 1.700 35.240 1.800 35.740 ;
        RECT 3.000 35.240 3.100 35.740 ;
        RECT 3.400 35.240 3.500 35.740 ;
        RECT 4.700 35.240 4.800 35.740 ;
        RECT 5.100 35.240 5.200 35.740 ;
        RECT 6.400 35.240 6.500 35.740 ;
        RECT 6.800 35.240 6.900 35.740 ;
        RECT 8.100 35.240 8.200 35.740 ;
        RECT 8.500 35.240 8.600 35.740 ;
        RECT 9.800 35.240 9.900 35.740 ;
        RECT 10.200 35.240 10.300 35.740 ;
        RECT 11.500 39.140 11.600 39.640 ;
        RECT 11.900 39.140 12.000 39.640 ;
        RECT 13.200 39.140 13.300 39.640 ;
        RECT 11.500 36.540 11.600 37.040 ;
        RECT 11.900 36.540 12.000 37.040 ;
        RECT 8.100 40.440 8.200 40.940 ;
        RECT 8.500 40.440 8.600 40.940 ;
        RECT 9.800 40.440 9.900 40.940 ;
        RECT 10.200 40.440 10.300 40.940 ;
        RECT 11.500 40.440 11.600 40.940 ;
        RECT 11.900 40.440 12.000 40.940 ;
        RECT 13.200 40.440 13.300 40.940 ;
        RECT 13.200 36.540 13.300 37.040 ;
        RECT 8.100 36.540 8.200 37.040 ;
        RECT 8.100 46.940 8.200 47.440 ;
        RECT 8.500 46.940 8.600 47.440 ;
        RECT 8.500 36.540 8.600 37.040 ;
        RECT 8.100 41.740 8.200 42.240 ;
        RECT 8.500 41.740 8.600 42.240 ;
        RECT 9.800 41.740 9.900 42.240 ;
        RECT 10.200 41.740 10.300 42.240 ;
        RECT 11.500 41.740 11.600 42.240 ;
        RECT 11.900 41.740 12.000 42.240 ;
        RECT 13.200 41.740 13.300 42.240 ;
        RECT 9.800 46.940 9.900 47.440 ;
        RECT 10.200 46.940 10.300 47.440 ;
        RECT 9.800 36.540 9.900 37.040 ;
        RECT 8.100 37.840 8.200 38.340 ;
        RECT 8.100 43.040 8.200 43.540 ;
        RECT 8.500 43.040 8.600 43.540 ;
        RECT 9.800 43.040 9.900 43.540 ;
        RECT 10.200 43.040 10.300 43.540 ;
        RECT 11.500 43.040 11.600 43.540 ;
        RECT 11.900 43.040 12.000 43.540 ;
        RECT 13.200 43.040 13.300 43.540 ;
        RECT 8.500 37.840 8.600 38.340 ;
        RECT 8.100 44.340 8.200 44.840 ;
        RECT 8.500 44.340 8.600 44.840 ;
        RECT 9.800 44.340 9.900 44.840 ;
        RECT 10.200 44.340 10.300 44.840 ;
        RECT 11.500 44.340 11.600 44.840 ;
        RECT 11.900 44.340 12.000 44.840 ;
        RECT 13.200 44.340 13.300 44.840 ;
        RECT 9.800 37.840 9.900 38.340 ;
        RECT 10.200 37.840 10.300 38.340 ;
        RECT 11.500 37.840 11.600 38.340 ;
        RECT 11.900 37.840 12.000 38.340 ;
        RECT 13.200 37.840 13.300 38.340 ;
        RECT 11.500 46.940 11.600 47.440 ;
        RECT 11.900 46.940 12.000 47.440 ;
        RECT 13.200 46.940 13.300 47.440 ;
        RECT 10.200 36.540 10.300 37.040 ;
        RECT 8.100 39.140 8.200 39.640 ;
        RECT 8.500 39.140 8.600 39.640 ;
        RECT 9.800 39.140 9.900 39.640 ;
        RECT 10.200 39.140 10.300 39.640 ;
        RECT 6.400 39.140 6.500 39.640 ;
        RECT 4.700 37.840 4.800 38.340 ;
        RECT 5.100 37.840 5.200 38.340 ;
        RECT 6.400 37.840 6.500 38.340 ;
        RECT 3.400 36.540 3.500 37.040 ;
        RECT 4.700 36.540 4.800 37.040 ;
        RECT 5.100 36.540 5.200 37.040 ;
        RECT 6.400 36.540 6.500 37.040 ;
        RECT 1.300 36.540 1.400 37.040 ;
        RECT 1.300 43.040 1.400 43.540 ;
        RECT 1.700 43.040 1.800 43.540 ;
        RECT 3.000 43.040 3.100 43.540 ;
        RECT 3.400 43.040 3.500 43.540 ;
        RECT 4.700 43.040 4.800 43.540 ;
        RECT 5.100 43.040 5.200 43.540 ;
        RECT 6.400 43.040 6.500 43.540 ;
        RECT 1.700 36.540 1.800 37.040 ;
        RECT 1.300 40.440 1.400 40.940 ;
        RECT 1.700 40.440 1.800 40.940 ;
        RECT 3.000 40.440 3.100 40.940 ;
        RECT 3.400 40.440 3.500 40.940 ;
        RECT 4.700 40.440 4.800 40.940 ;
        RECT 5.100 40.440 5.200 40.940 ;
        RECT 6.400 40.440 6.500 40.940 ;
        RECT 1.300 44.340 1.400 44.840 ;
        RECT 1.700 44.340 1.800 44.840 ;
        RECT 3.000 44.340 3.100 44.840 ;
        RECT 3.400 44.340 3.500 44.840 ;
        RECT 4.700 44.340 4.800 44.840 ;
        RECT 5.100 44.340 5.200 44.840 ;
        RECT 6.400 44.340 6.500 44.840 ;
        RECT 3.000 36.540 3.100 37.040 ;
        RECT 1.300 37.840 1.400 38.340 ;
        RECT 1.700 37.840 1.800 38.340 ;
        RECT 3.000 37.840 3.100 38.340 ;
        RECT 3.400 37.840 3.500 38.340 ;
        RECT 4.700 46.940 4.800 47.440 ;
        RECT 5.100 46.940 5.200 47.440 ;
        RECT 6.400 46.940 6.500 47.440 ;
        RECT 1.300 39.140 1.400 39.640 ;
        RECT 1.700 39.140 1.800 39.640 ;
        RECT 3.000 39.140 3.100 39.640 ;
        RECT 3.400 39.140 3.500 39.640 ;
        RECT 1.300 41.740 1.400 42.240 ;
        RECT 1.700 41.740 1.800 42.240 ;
        RECT 3.000 41.740 3.100 42.240 ;
        RECT 3.400 41.740 3.500 42.240 ;
        RECT 4.700 41.740 4.800 42.240 ;
        RECT 5.100 41.740 5.200 42.240 ;
        RECT 6.400 41.740 6.500 42.240 ;
        RECT 4.700 39.140 4.800 39.640 ;
        RECT 5.100 39.140 5.200 39.640 ;
        RECT 1.300 46.940 1.400 47.440 ;
        RECT 1.700 46.940 1.800 47.440 ;
        RECT 3.000 46.940 3.100 47.440 ;
        RECT 3.400 46.940 3.500 47.440 ;
        RECT 6.400 30.040 6.500 30.540 ;
        RECT 5.100 24.840 5.200 25.340 ;
        RECT 3.400 24.840 3.500 25.340 ;
        RECT 4.700 24.840 4.800 25.340 ;
        RECT 1.300 26.140 1.400 26.640 ;
        RECT 1.700 26.140 1.800 26.640 ;
        RECT 3.000 26.140 3.100 26.640 ;
        RECT 3.400 26.140 3.500 26.640 ;
        RECT 4.700 26.140 4.800 26.640 ;
        RECT 5.100 26.140 5.200 26.640 ;
        RECT 1.300 28.740 1.400 29.240 ;
        RECT 1.700 28.740 1.800 29.240 ;
        RECT 3.000 28.740 3.100 29.240 ;
        RECT 3.400 28.740 3.500 29.240 ;
        RECT 6.400 24.840 6.500 25.340 ;
        RECT 1.300 27.440 1.400 27.940 ;
        RECT 6.400 26.140 6.500 26.640 ;
        RECT 1.300 30.040 1.400 30.540 ;
        RECT 1.700 30.040 1.800 30.540 ;
        RECT 3.000 30.040 3.100 30.540 ;
        RECT 1.700 27.440 1.800 27.940 ;
        RECT 3.000 27.440 3.100 27.940 ;
        RECT 1.300 24.840 1.400 25.340 ;
        RECT 1.700 24.840 1.800 25.340 ;
        RECT 3.000 24.840 3.100 25.340 ;
        RECT 1.300 32.640 1.400 33.140 ;
        RECT 1.700 32.640 1.800 33.140 ;
        RECT 3.000 32.640 3.100 33.140 ;
        RECT 3.400 32.640 3.500 33.140 ;
        RECT 4.700 28.740 4.800 29.240 ;
        RECT 5.100 28.740 5.200 29.240 ;
        RECT 6.400 28.740 6.500 29.240 ;
        RECT 4.700 32.640 4.800 33.140 ;
        RECT 5.100 32.640 5.200 33.140 ;
        RECT 6.400 32.640 6.500 33.140 ;
        RECT 3.400 27.440 3.500 27.940 ;
        RECT 4.700 27.440 4.800 27.940 ;
        RECT 5.100 27.440 5.200 27.940 ;
        RECT 6.400 27.440 6.500 27.940 ;
        RECT 1.300 31.340 1.400 31.840 ;
        RECT 1.700 31.340 1.800 31.840 ;
        RECT 3.000 31.340 3.100 31.840 ;
        RECT 3.400 31.340 3.500 31.840 ;
        RECT 4.700 31.340 4.800 31.840 ;
        RECT 5.100 31.340 5.200 31.840 ;
        RECT 6.400 31.340 6.500 31.840 ;
        RECT 3.400 30.040 3.500 30.540 ;
        RECT 4.700 30.040 4.800 30.540 ;
        RECT 5.100 30.040 5.200 30.540 ;
        RECT 11.900 32.640 12.000 33.140 ;
        RECT 13.200 32.640 13.300 33.140 ;
        RECT 9.800 26.140 9.900 26.640 ;
        RECT 10.200 26.140 10.300 26.640 ;
        RECT 11.500 26.140 11.600 26.640 ;
        RECT 8.100 30.040 8.200 30.540 ;
        RECT 11.900 26.140 12.000 26.640 ;
        RECT 13.200 26.140 13.300 26.640 ;
        RECT 9.800 28.740 9.900 29.240 ;
        RECT 10.200 28.740 10.300 29.240 ;
        RECT 8.100 31.340 8.200 31.840 ;
        RECT 8.500 31.340 8.600 31.840 ;
        RECT 11.500 28.740 11.600 29.240 ;
        RECT 11.900 28.740 12.000 29.240 ;
        RECT 8.100 24.840 8.200 25.340 ;
        RECT 8.500 24.840 8.600 25.340 ;
        RECT 9.800 24.840 9.900 25.340 ;
        RECT 10.200 24.840 10.300 25.340 ;
        RECT 13.200 28.740 13.300 29.240 ;
        RECT 8.100 28.740 8.200 29.240 ;
        RECT 8.500 28.740 8.600 29.240 ;
        RECT 8.100 26.140 8.200 26.640 ;
        RECT 8.500 26.140 8.600 26.640 ;
        RECT 8.500 30.040 8.600 30.540 ;
        RECT 9.800 30.040 9.900 30.540 ;
        RECT 10.200 30.040 10.300 30.540 ;
        RECT 11.500 30.040 11.600 30.540 ;
        RECT 9.800 31.340 9.900 31.840 ;
        RECT 10.200 31.340 10.300 31.840 ;
        RECT 8.100 32.640 8.200 33.140 ;
        RECT 8.500 32.640 8.600 33.140 ;
        RECT 9.800 32.640 9.900 33.140 ;
        RECT 11.500 31.340 11.600 31.840 ;
        RECT 11.900 31.340 12.000 31.840 ;
        RECT 13.200 31.340 13.300 31.840 ;
        RECT 11.900 30.040 12.000 30.540 ;
        RECT 8.100 27.440 8.200 27.940 ;
        RECT 8.500 27.440 8.600 27.940 ;
        RECT 9.800 27.440 9.900 27.940 ;
        RECT 10.200 27.440 10.300 27.940 ;
        RECT 11.500 27.440 11.600 27.940 ;
        RECT 11.900 27.440 12.000 27.940 ;
        RECT 13.200 27.440 13.300 27.940 ;
        RECT 13.200 30.040 13.300 30.540 ;
        RECT 11.500 24.840 11.600 25.340 ;
        RECT 11.900 24.840 12.000 25.340 ;
        RECT 13.200 24.840 13.300 25.340 ;
        RECT 10.200 32.640 10.300 33.140 ;
        RECT 11.500 32.640 11.600 33.140 ;
        RECT 6.800 4.040 6.900 4.540 ;
        RECT 6.800 5.340 6.900 5.840 ;
        RECT 6.800 6.640 6.900 7.140 ;
        RECT 6.800 7.940 6.900 8.440 ;
        RECT 6.800 9.240 6.900 9.740 ;
        RECT 6.800 0.140 6.900 0.640 ;
        RECT 1.300 11.840 1.400 12.340 ;
        RECT 1.700 11.840 1.800 12.340 ;
        RECT 3.000 11.840 3.100 12.340 ;
        RECT 3.400 11.840 3.500 12.340 ;
        RECT 4.700 11.840 4.800 12.340 ;
        RECT 5.100 11.840 5.200 12.340 ;
        RECT 6.400 11.840 6.500 12.340 ;
        RECT 6.800 11.840 6.900 12.340 ;
        RECT 8.100 11.840 8.200 12.340 ;
        RECT 8.500 11.840 8.600 12.340 ;
        RECT 9.800 11.840 9.900 12.340 ;
        RECT 10.200 11.840 10.300 12.340 ;
        RECT 11.500 11.840 11.600 12.340 ;
        RECT 11.900 11.840 12.000 12.340 ;
        RECT 13.200 11.840 13.300 12.340 ;
        RECT 6.800 1.440 6.900 1.940 ;
        RECT 6.800 13.140 6.900 13.640 ;
        RECT 6.800 14.440 6.900 14.940 ;
        RECT 6.800 15.740 6.900 16.240 ;
        RECT 6.800 17.040 6.900 17.540 ;
        RECT 6.800 18.340 6.900 18.840 ;
        RECT 6.800 19.640 6.900 20.140 ;
        RECT 6.800 20.940 6.900 21.440 ;
        RECT 6.800 2.740 6.900 3.240 ;
        RECT 8.100 13.140 8.200 13.640 ;
        RECT 8.100 14.440 8.200 14.940 ;
        RECT 8.500 14.440 8.600 14.940 ;
        RECT 9.800 14.440 9.900 14.940 ;
        RECT 10.200 14.440 10.300 14.940 ;
        RECT 11.500 14.440 11.600 14.940 ;
        RECT 11.900 14.440 12.000 14.940 ;
        RECT 13.200 14.440 13.300 14.940 ;
        RECT 8.500 13.140 8.600 13.640 ;
        RECT 8.100 15.740 8.200 16.240 ;
        RECT 8.500 15.740 8.600 16.240 ;
        RECT 9.800 15.740 9.900 16.240 ;
        RECT 10.200 15.740 10.300 16.240 ;
        RECT 11.500 15.740 11.600 16.240 ;
        RECT 11.900 15.740 12.000 16.240 ;
        RECT 13.200 15.740 13.300 16.240 ;
        RECT 9.800 13.140 9.900 13.640 ;
        RECT 8.100 17.040 8.200 17.540 ;
        RECT 8.500 17.040 8.600 17.540 ;
        RECT 9.800 17.040 9.900 17.540 ;
        RECT 10.200 17.040 10.300 17.540 ;
        RECT 11.500 17.040 11.600 17.540 ;
        RECT 11.900 17.040 12.000 17.540 ;
        RECT 13.200 17.040 13.300 17.540 ;
        RECT 10.200 13.140 10.300 13.640 ;
        RECT 8.100 18.340 8.200 18.840 ;
        RECT 8.500 18.340 8.600 18.840 ;
        RECT 9.800 18.340 9.900 18.840 ;
        RECT 10.200 18.340 10.300 18.840 ;
        RECT 11.500 18.340 11.600 18.840 ;
        RECT 11.900 18.340 12.000 18.840 ;
        RECT 13.200 18.340 13.300 18.840 ;
        RECT 11.500 13.140 11.600 13.640 ;
        RECT 8.100 19.640 8.200 20.140 ;
        RECT 8.500 19.640 8.600 20.140 ;
        RECT 9.800 19.640 9.900 20.140 ;
        RECT 10.200 19.640 10.300 20.140 ;
        RECT 11.500 19.640 11.600 20.140 ;
        RECT 11.900 19.640 12.000 20.140 ;
        RECT 13.200 19.640 13.300 20.140 ;
        RECT 11.900 13.140 12.000 13.640 ;
        RECT 8.100 20.940 8.200 21.440 ;
        RECT 8.500 20.940 8.600 21.440 ;
        RECT 9.800 20.940 9.900 21.440 ;
        RECT 10.200 20.940 10.300 21.440 ;
        RECT 11.500 20.940 11.600 21.440 ;
        RECT 11.900 20.940 12.000 21.440 ;
        RECT 13.200 20.940 13.300 21.440 ;
        RECT 13.200 13.140 13.300 13.640 ;
        RECT 1.300 14.440 1.400 14.940 ;
        RECT 1.300 15.740 1.400 16.240 ;
        RECT 1.700 15.740 1.800 16.240 ;
        RECT 1.300 18.340 1.400 18.840 ;
        RECT 1.700 18.340 1.800 18.840 ;
        RECT 3.000 18.340 3.100 18.840 ;
        RECT 3.400 18.340 3.500 18.840 ;
        RECT 4.700 18.340 4.800 18.840 ;
        RECT 5.100 18.340 5.200 18.840 ;
        RECT 6.400 18.340 6.500 18.840 ;
        RECT 3.000 15.740 3.100 16.240 ;
        RECT 3.400 15.740 3.500 16.240 ;
        RECT 4.700 15.740 4.800 16.240 ;
        RECT 5.100 15.740 5.200 16.240 ;
        RECT 6.400 15.740 6.500 16.240 ;
        RECT 1.700 14.440 1.800 14.940 ;
        RECT 3.000 14.440 3.100 14.940 ;
        RECT 3.400 14.440 3.500 14.940 ;
        RECT 1.300 19.640 1.400 20.140 ;
        RECT 1.700 19.640 1.800 20.140 ;
        RECT 3.000 19.640 3.100 20.140 ;
        RECT 3.400 19.640 3.500 20.140 ;
        RECT 4.700 19.640 4.800 20.140 ;
        RECT 5.100 19.640 5.200 20.140 ;
        RECT 6.400 19.640 6.500 20.140 ;
        RECT 4.700 14.440 4.800 14.940 ;
        RECT 5.100 14.440 5.200 14.940 ;
        RECT 6.400 14.440 6.500 14.940 ;
        RECT 1.700 13.140 1.800 13.640 ;
        RECT 3.000 13.140 3.100 13.640 ;
        RECT 1.300 17.040 1.400 17.540 ;
        RECT 1.700 17.040 1.800 17.540 ;
        RECT 3.000 17.040 3.100 17.540 ;
        RECT 1.300 20.940 1.400 21.440 ;
        RECT 1.700 20.940 1.800 21.440 ;
        RECT 3.000 20.940 3.100 21.440 ;
        RECT 3.400 20.940 3.500 21.440 ;
        RECT 4.700 20.940 4.800 21.440 ;
        RECT 5.100 20.940 5.200 21.440 ;
        RECT 6.400 20.940 6.500 21.440 ;
        RECT 3.400 17.040 3.500 17.540 ;
        RECT 4.700 17.040 4.800 17.540 ;
        RECT 5.100 17.040 5.200 17.540 ;
        RECT 6.400 17.040 6.500 17.540 ;
        RECT 3.400 13.140 3.500 13.640 ;
        RECT 4.700 13.140 4.800 13.640 ;
        RECT 5.100 13.140 5.200 13.640 ;
        RECT 6.400 13.140 6.500 13.640 ;
        RECT 1.300 13.140 1.400 13.640 ;
        RECT 3.000 5.340 3.100 5.840 ;
        RECT 3.400 5.340 3.500 5.840 ;
        RECT 4.700 5.340 4.800 5.840 ;
        RECT 5.100 5.340 5.200 5.840 ;
        RECT 6.400 5.340 6.500 5.840 ;
        RECT 5.100 4.040 5.200 4.540 ;
        RECT 3.400 1.440 3.500 1.940 ;
        RECT 4.700 0.140 4.800 0.640 ;
        RECT 1.300 6.640 1.400 7.140 ;
        RECT 1.700 6.640 1.800 7.140 ;
        RECT 3.000 6.640 3.100 7.140 ;
        RECT 3.400 6.640 3.500 7.140 ;
        RECT 4.700 6.640 4.800 7.140 ;
        RECT 5.100 6.640 5.200 7.140 ;
        RECT 6.400 6.640 6.500 7.140 ;
        RECT 6.400 4.040 6.500 4.540 ;
        RECT 4.700 1.440 4.800 1.940 ;
        RECT 5.100 0.140 5.200 0.640 ;
        RECT 1.300 7.940 1.400 8.440 ;
        RECT 1.700 7.940 1.800 8.440 ;
        RECT 3.000 7.940 3.100 8.440 ;
        RECT 3.400 7.940 3.500 8.440 ;
        RECT 4.700 7.940 4.800 8.440 ;
        RECT 5.100 7.940 5.200 8.440 ;
        RECT 6.400 7.940 6.500 8.440 ;
        RECT 4.700 4.040 4.800 4.540 ;
        RECT 5.100 1.440 5.200 1.940 ;
        RECT 6.400 0.140 6.500 0.640 ;
        RECT 1.300 9.240 1.400 9.740 ;
        RECT 1.700 9.240 1.800 9.740 ;
        RECT 3.000 9.240 3.100 9.740 ;
        RECT 3.400 9.240 3.500 9.740 ;
        RECT 4.700 9.240 4.800 9.740 ;
        RECT 5.100 9.240 5.200 9.740 ;
        RECT 6.400 9.240 6.500 9.740 ;
        RECT 3.000 1.440 3.100 1.940 ;
        RECT 6.400 1.440 6.500 1.940 ;
        RECT 3.400 0.140 3.500 0.640 ;
        RECT 1.300 5.340 1.400 5.840 ;
        RECT 1.300 1.440 1.400 1.940 ;
        RECT 1.700 0.140 1.800 0.640 ;
        RECT 1.300 2.740 1.400 3.240 ;
        RECT 1.700 2.740 1.800 3.240 ;
        RECT 3.000 2.740 3.100 3.240 ;
        RECT 3.400 2.740 3.500 3.240 ;
        RECT 4.700 2.740 4.800 3.240 ;
        RECT 5.100 2.740 5.200 3.240 ;
        RECT 6.400 2.740 6.500 3.240 ;
        RECT 1.700 5.340 1.800 5.840 ;
        RECT 1.700 1.440 1.800 1.940 ;
        RECT 3.000 0.140 3.100 0.640 ;
        RECT 1.300 0.140 1.400 0.640 ;
        RECT 1.300 4.040 1.400 4.540 ;
        RECT 1.700 4.040 1.800 4.540 ;
        RECT 3.000 4.040 3.100 4.540 ;
        RECT 3.400 4.040 3.500 4.540 ;
        RECT 9.800 4.040 9.900 4.540 ;
        RECT 8.100 5.340 8.200 5.840 ;
        RECT 8.500 5.340 8.600 5.840 ;
        RECT 9.800 5.340 9.900 5.840 ;
        RECT 8.100 6.640 8.200 7.140 ;
        RECT 8.500 6.640 8.600 7.140 ;
        RECT 9.800 6.640 9.900 7.140 ;
        RECT 10.200 6.640 10.300 7.140 ;
        RECT 11.500 6.640 11.600 7.140 ;
        RECT 9.800 1.440 9.900 1.940 ;
        RECT 10.200 0.140 10.300 0.640 ;
        RECT 11.900 6.640 12.000 7.140 ;
        RECT 8.100 9.240 8.200 9.740 ;
        RECT 8.500 9.240 8.600 9.740 ;
        RECT 11.900 1.440 12.000 1.940 ;
        RECT 13.200 0.140 13.300 0.640 ;
        RECT 9.800 9.240 9.900 9.740 ;
        RECT 10.200 9.240 10.300 9.740 ;
        RECT 11.500 9.240 11.600 9.740 ;
        RECT 8.100 1.440 8.200 1.940 ;
        RECT 8.500 0.140 8.600 0.640 ;
        RECT 11.900 9.240 12.000 9.740 ;
        RECT 13.200 9.240 13.300 9.740 ;
        RECT 13.200 6.640 13.300 7.140 ;
        RECT 10.200 5.340 10.300 5.840 ;
        RECT 11.500 5.340 11.600 5.840 ;
        RECT 11.900 5.340 12.000 5.840 ;
        RECT 13.200 5.340 13.300 5.840 ;
        RECT 10.200 1.440 10.300 1.940 ;
        RECT 11.500 0.140 11.600 0.640 ;
        RECT 10.200 4.040 10.300 4.540 ;
        RECT 13.200 1.440 13.300 1.940 ;
        RECT 11.500 4.040 11.600 4.540 ;
        RECT 11.900 4.040 12.000 4.540 ;
        RECT 13.200 4.040 13.300 4.540 ;
        RECT 8.100 4.040 8.200 4.540 ;
        RECT 8.500 4.040 8.600 4.540 ;
        RECT 8.100 7.940 8.200 8.440 ;
        RECT 8.500 7.940 8.600 8.440 ;
        RECT 8.500 1.440 8.600 1.940 ;
        RECT 9.800 0.140 9.900 0.640 ;
        RECT 9.800 7.940 9.900 8.440 ;
        RECT 8.100 2.740 8.200 3.240 ;
        RECT 8.500 2.740 8.600 3.240 ;
        RECT 9.800 2.740 9.900 3.240 ;
        RECT 10.200 2.740 10.300 3.240 ;
        RECT 11.500 2.740 11.600 3.240 ;
        RECT 11.900 2.740 12.000 3.240 ;
        RECT 13.200 2.740 13.300 3.240 ;
        RECT 10.200 7.940 10.300 8.440 ;
        RECT 11.500 7.940 11.600 8.440 ;
        RECT 11.900 7.940 12.000 8.440 ;
        RECT 13.200 7.940 13.300 8.440 ;
        RECT 11.500 1.440 11.600 1.940 ;
        RECT 11.900 0.140 12.000 0.640 ;
        RECT 8.100 0.140 8.200 0.640 ;
        RECT 20.400 4.040 20.500 4.540 ;
        RECT 20.400 14.440 20.500 14.940 ;
        RECT 20.400 2.740 20.500 3.240 ;
        RECT 20.400 7.940 20.500 8.440 ;
        RECT 20.400 15.740 20.500 16.240 ;
        RECT 20.400 17.040 20.500 17.540 ;
        RECT 20.400 9.240 20.500 9.740 ;
        RECT 20.400 18.340 20.500 18.840 ;
        RECT 20.400 5.340 20.500 5.840 ;
        RECT 20.400 1.440 20.500 1.940 ;
        RECT 20.400 19.640 20.500 20.140 ;
        RECT 14.900 11.840 15.000 12.340 ;
        RECT 15.300 11.840 15.400 12.340 ;
        RECT 16.600 11.840 16.700 12.340 ;
        RECT 17.000 11.840 17.100 12.340 ;
        RECT 18.300 11.840 18.400 12.340 ;
        RECT 18.700 11.840 18.800 12.340 ;
        RECT 20.000 11.840 20.100 12.340 ;
        RECT 20.400 11.840 20.500 12.340 ;
        RECT 21.700 11.840 21.800 12.340 ;
        RECT 22.100 11.840 22.200 12.340 ;
        RECT 23.400 11.840 23.500 12.340 ;
        RECT 23.800 11.840 23.900 12.340 ;
        RECT 25.100 11.840 25.200 12.340 ;
        RECT 25.500 11.840 25.600 12.340 ;
        RECT 20.400 20.940 20.500 21.440 ;
        RECT 26.800 11.840 26.900 12.340 ;
        RECT 20.400 6.640 20.500 7.140 ;
        RECT 20.400 0.140 20.500 0.640 ;
        RECT 20.400 13.140 20.500 13.640 ;
        RECT 22.100 18.340 22.200 18.840 ;
        RECT 23.400 18.340 23.500 18.840 ;
        RECT 23.800 18.340 23.900 18.840 ;
        RECT 25.100 18.340 25.200 18.840 ;
        RECT 25.500 18.340 25.600 18.840 ;
        RECT 26.800 18.340 26.900 18.840 ;
        RECT 26.800 14.440 26.900 14.940 ;
        RECT 21.700 14.440 21.800 14.940 ;
        RECT 22.100 14.440 22.200 14.940 ;
        RECT 21.700 19.640 21.800 20.140 ;
        RECT 22.100 19.640 22.200 20.140 ;
        RECT 23.400 19.640 23.500 20.140 ;
        RECT 23.800 19.640 23.900 20.140 ;
        RECT 25.100 19.640 25.200 20.140 ;
        RECT 25.500 19.640 25.600 20.140 ;
        RECT 26.800 19.640 26.900 20.140 ;
        RECT 23.400 14.440 23.500 14.940 ;
        RECT 21.700 15.740 21.800 16.240 ;
        RECT 22.100 15.740 22.200 16.240 ;
        RECT 23.400 15.740 23.500 16.240 ;
        RECT 23.800 15.740 23.900 16.240 ;
        RECT 25.100 15.740 25.200 16.240 ;
        RECT 25.500 15.740 25.600 16.240 ;
        RECT 26.800 15.740 26.900 16.240 ;
        RECT 23.800 14.440 23.900 14.940 ;
        RECT 21.700 17.040 21.800 17.540 ;
        RECT 22.100 17.040 22.200 17.540 ;
        RECT 23.400 17.040 23.500 17.540 ;
        RECT 23.800 17.040 23.900 17.540 ;
        RECT 25.100 17.040 25.200 17.540 ;
        RECT 25.500 17.040 25.600 17.540 ;
        RECT 21.700 20.940 21.800 21.440 ;
        RECT 22.100 20.940 22.200 21.440 ;
        RECT 23.400 20.940 23.500 21.440 ;
        RECT 23.800 20.940 23.900 21.440 ;
        RECT 25.100 20.940 25.200 21.440 ;
        RECT 25.500 20.940 25.600 21.440 ;
        RECT 26.800 20.940 26.900 21.440 ;
        RECT 26.800 17.040 26.900 17.540 ;
        RECT 25.100 14.440 25.200 14.940 ;
        RECT 25.500 14.440 25.600 14.940 ;
        RECT 21.700 18.340 21.800 18.840 ;
        RECT 21.700 13.140 21.800 13.640 ;
        RECT 22.100 13.140 22.200 13.640 ;
        RECT 23.400 13.140 23.500 13.640 ;
        RECT 23.800 13.140 23.900 13.640 ;
        RECT 25.100 13.140 25.200 13.640 ;
        RECT 25.500 13.140 25.600 13.640 ;
        RECT 26.800 13.140 26.900 13.640 ;
        RECT 18.700 15.740 18.800 16.240 ;
        RECT 20.000 15.740 20.100 16.240 ;
        RECT 17.000 14.440 17.100 14.940 ;
        RECT 18.300 14.440 18.400 14.940 ;
        RECT 18.700 14.440 18.800 14.940 ;
        RECT 14.900 18.340 15.000 18.840 ;
        RECT 15.300 18.340 15.400 18.840 ;
        RECT 16.600 18.340 16.700 18.840 ;
        RECT 17.000 18.340 17.100 18.840 ;
        RECT 18.300 18.340 18.400 18.840 ;
        RECT 18.700 18.340 18.800 18.840 ;
        RECT 20.000 18.340 20.100 18.840 ;
        RECT 20.000 14.440 20.100 14.940 ;
        RECT 14.900 14.440 15.000 14.940 ;
        RECT 15.300 14.440 15.400 14.940 ;
        RECT 16.600 14.440 16.700 14.940 ;
        RECT 14.900 20.940 15.000 21.440 ;
        RECT 15.300 20.940 15.400 21.440 ;
        RECT 16.600 20.940 16.700 21.440 ;
        RECT 17.000 20.940 17.100 21.440 ;
        RECT 18.300 20.940 18.400 21.440 ;
        RECT 18.700 20.940 18.800 21.440 ;
        RECT 20.000 20.940 20.100 21.440 ;
        RECT 14.900 15.740 15.000 16.240 ;
        RECT 14.900 17.040 15.000 17.540 ;
        RECT 15.300 17.040 15.400 17.540 ;
        RECT 16.600 17.040 16.700 17.540 ;
        RECT 17.000 17.040 17.100 17.540 ;
        RECT 18.300 17.040 18.400 17.540 ;
        RECT 14.900 19.640 15.000 20.140 ;
        RECT 15.300 19.640 15.400 20.140 ;
        RECT 16.600 19.640 16.700 20.140 ;
        RECT 17.000 19.640 17.100 20.140 ;
        RECT 14.900 13.140 15.000 13.640 ;
        RECT 15.300 13.140 15.400 13.640 ;
        RECT 16.600 13.140 16.700 13.640 ;
        RECT 17.000 13.140 17.100 13.640 ;
        RECT 18.300 13.140 18.400 13.640 ;
        RECT 18.700 13.140 18.800 13.640 ;
        RECT 18.300 19.640 18.400 20.140 ;
        RECT 20.000 13.140 20.100 13.640 ;
        RECT 18.700 19.640 18.800 20.140 ;
        RECT 20.000 19.640 20.100 20.140 ;
        RECT 18.700 17.040 18.800 17.540 ;
        RECT 20.000 17.040 20.100 17.540 ;
        RECT 15.300 15.740 15.400 16.240 ;
        RECT 16.600 15.740 16.700 16.240 ;
        RECT 17.000 15.740 17.100 16.240 ;
        RECT 18.300 15.740 18.400 16.240 ;
        RECT 18.300 7.940 18.400 8.440 ;
        RECT 18.700 7.940 18.800 8.440 ;
        RECT 20.000 7.940 20.100 8.440 ;
        RECT 16.600 0.140 16.700 0.640 ;
        RECT 17.000 0.140 17.100 0.640 ;
        RECT 20.000 5.340 20.100 5.840 ;
        RECT 16.600 2.740 16.700 3.240 ;
        RECT 20.000 1.440 20.100 1.940 ;
        RECT 17.000 2.740 17.100 3.240 ;
        RECT 18.300 2.740 18.400 3.240 ;
        RECT 16.600 1.440 16.700 1.940 ;
        RECT 20.000 0.140 20.100 0.640 ;
        RECT 15.300 5.340 15.400 5.840 ;
        RECT 16.600 5.340 16.700 5.840 ;
        RECT 17.000 5.340 17.100 5.840 ;
        RECT 18.300 5.340 18.400 5.840 ;
        RECT 18.700 5.340 18.800 5.840 ;
        RECT 14.900 9.240 15.000 9.740 ;
        RECT 15.300 9.240 15.400 9.740 ;
        RECT 18.700 0.140 18.800 0.640 ;
        RECT 14.900 1.440 15.000 1.940 ;
        RECT 15.300 1.440 15.400 1.940 ;
        RECT 14.900 2.740 15.000 3.240 ;
        RECT 15.300 2.740 15.400 3.240 ;
        RECT 14.900 4.040 15.000 4.540 ;
        RECT 15.300 4.040 15.400 4.540 ;
        RECT 16.600 4.040 16.700 4.540 ;
        RECT 17.000 4.040 17.100 4.540 ;
        RECT 14.900 6.640 15.000 7.140 ;
        RECT 15.300 6.640 15.400 7.140 ;
        RECT 16.600 6.640 16.700 7.140 ;
        RECT 17.000 6.640 17.100 7.140 ;
        RECT 18.300 6.640 18.400 7.140 ;
        RECT 18.700 6.640 18.800 7.140 ;
        RECT 20.000 6.640 20.100 7.140 ;
        RECT 16.600 9.240 16.700 9.740 ;
        RECT 17.000 9.240 17.100 9.740 ;
        RECT 18.300 9.240 18.400 9.740 ;
        RECT 18.700 9.240 18.800 9.740 ;
        RECT 20.000 9.240 20.100 9.740 ;
        RECT 17.000 1.440 17.100 1.940 ;
        RECT 18.300 1.440 18.400 1.940 ;
        RECT 18.700 1.440 18.800 1.940 ;
        RECT 14.900 5.340 15.000 5.840 ;
        RECT 18.700 2.740 18.800 3.240 ;
        RECT 20.000 2.740 20.100 3.240 ;
        RECT 15.300 0.140 15.400 0.640 ;
        RECT 14.900 7.940 15.000 8.440 ;
        RECT 15.300 7.940 15.400 8.440 ;
        RECT 16.600 7.940 16.700 8.440 ;
        RECT 17.000 7.940 17.100 8.440 ;
        RECT 14.900 0.140 15.000 0.640 ;
        RECT 18.300 0.140 18.400 0.640 ;
        RECT 18.300 4.040 18.400 4.540 ;
        RECT 18.700 4.040 18.800 4.540 ;
        RECT 20.000 4.040 20.100 4.540 ;
        RECT 26.800 5.340 26.900 5.840 ;
        RECT 23.400 0.140 23.500 0.640 ;
        RECT 25.100 0.140 25.200 0.640 ;
        RECT 23.400 4.040 23.500 4.540 ;
        RECT 21.700 1.440 21.800 1.940 ;
        RECT 22.100 1.440 22.200 1.940 ;
        RECT 23.400 1.440 23.500 1.940 ;
        RECT 26.800 4.040 26.900 4.540 ;
        RECT 22.100 0.140 22.200 0.640 ;
        RECT 23.800 4.040 23.900 4.540 ;
        RECT 21.700 0.140 21.800 0.640 ;
        RECT 26.800 1.440 26.900 1.940 ;
        RECT 21.700 9.240 21.800 9.740 ;
        RECT 22.100 9.240 22.200 9.740 ;
        RECT 23.800 0.140 23.900 0.640 ;
        RECT 23.400 9.240 23.500 9.740 ;
        RECT 23.800 9.240 23.900 9.740 ;
        RECT 25.100 4.040 25.200 4.540 ;
        RECT 23.400 7.940 23.500 8.440 ;
        RECT 26.800 0.140 26.900 0.640 ;
        RECT 23.800 7.940 23.900 8.440 ;
        RECT 25.100 7.940 25.200 8.440 ;
        RECT 25.500 7.940 25.600 8.440 ;
        RECT 26.800 7.940 26.900 8.440 ;
        RECT 21.700 2.740 21.800 3.240 ;
        RECT 23.800 1.440 23.900 1.940 ;
        RECT 25.100 1.440 25.200 1.940 ;
        RECT 25.500 1.440 25.600 1.940 ;
        RECT 22.100 2.740 22.200 3.240 ;
        RECT 23.400 2.740 23.500 3.240 ;
        RECT 23.800 2.740 23.900 3.240 ;
        RECT 25.100 2.740 25.200 3.240 ;
        RECT 25.500 2.740 25.600 3.240 ;
        RECT 26.800 2.740 26.900 3.240 ;
        RECT 25.500 4.040 25.600 4.540 ;
        RECT 21.700 4.040 21.800 4.540 ;
        RECT 25.500 0.140 25.600 0.640 ;
        RECT 22.100 4.040 22.200 4.540 ;
        RECT 25.100 9.240 25.200 9.740 ;
        RECT 25.500 9.240 25.600 9.740 ;
        RECT 26.800 9.240 26.900 9.740 ;
        RECT 21.700 7.940 21.800 8.440 ;
        RECT 22.100 7.940 22.200 8.440 ;
        RECT 21.700 5.340 21.800 5.840 ;
        RECT 22.100 5.340 22.200 5.840 ;
        RECT 23.400 5.340 23.500 5.840 ;
        RECT 21.700 6.640 21.800 7.140 ;
        RECT 22.100 6.640 22.200 7.140 ;
        RECT 23.400 6.640 23.500 7.140 ;
        RECT 23.800 6.640 23.900 7.140 ;
        RECT 25.100 6.640 25.200 7.140 ;
        RECT 25.500 6.640 25.600 7.140 ;
        RECT 26.800 6.640 26.900 7.140 ;
        RECT 23.800 5.340 23.900 5.840 ;
        RECT 25.100 5.340 25.200 5.840 ;
        RECT 25.500 5.340 25.600 5.840 ;
        RECT 40.800 44.340 40.900 44.840 ;
        RECT 40.800 0.140 40.900 0.640 ;
        RECT 40.800 46.940 40.900 47.440 ;
        RECT 28.500 23.540 28.600 24.040 ;
        RECT 28.900 23.540 29.000 24.040 ;
        RECT 30.200 23.540 30.300 24.040 ;
        RECT 30.600 23.540 30.700 24.040 ;
        RECT 31.900 23.540 32.000 24.040 ;
        RECT 32.300 23.540 32.400 24.040 ;
        RECT 33.600 23.540 33.700 24.040 ;
        RECT 34.000 23.540 34.100 24.040 ;
        RECT 35.300 23.540 35.400 24.040 ;
        RECT 35.700 23.540 35.800 24.040 ;
        RECT 37.000 23.540 37.100 24.040 ;
        RECT 37.400 23.540 37.500 24.040 ;
        RECT 38.700 23.540 38.800 24.040 ;
        RECT 39.100 23.540 39.200 24.040 ;
        RECT 40.400 23.540 40.500 24.040 ;
        RECT 40.800 23.540 40.900 24.040 ;
        RECT 42.100 23.540 42.200 24.040 ;
        RECT 42.500 23.540 42.600 24.040 ;
        RECT 43.800 23.540 43.900 24.040 ;
        RECT 44.200 23.540 44.300 24.040 ;
        RECT 45.500 23.540 45.600 24.040 ;
        RECT 45.900 23.540 46.000 24.040 ;
        RECT 47.200 23.540 47.300 24.040 ;
        RECT 47.600 23.540 47.700 24.040 ;
        RECT 48.900 23.540 49.000 24.040 ;
        RECT 49.300 23.540 49.400 24.040 ;
        RECT 50.600 23.540 50.700 24.040 ;
        RECT 51.000 23.540 51.100 24.040 ;
        RECT 52.300 23.540 52.400 24.040 ;
        RECT 52.700 23.540 52.800 24.040 ;
        RECT 54.000 23.540 54.100 24.040 ;
        RECT 54.400 23.540 54.500 24.040 ;
        RECT 40.800 11.840 40.900 12.340 ;
        RECT 40.800 24.840 40.900 25.340 ;
        RECT 40.800 5.340 40.900 5.840 ;
        RECT 40.800 26.140 40.900 26.640 ;
        RECT 40.800 13.140 40.900 13.640 ;
        RECT 40.800 27.440 40.900 27.940 ;
        RECT 40.800 2.740 40.900 3.240 ;
        RECT 40.800 28.740 40.900 29.240 ;
        RECT 40.800 14.440 40.900 14.940 ;
        RECT 40.800 30.040 40.900 30.540 ;
        RECT 40.800 6.640 40.900 7.140 ;
        RECT 40.800 31.340 40.900 31.840 ;
        RECT 40.800 15.740 40.900 16.240 ;
        RECT 40.800 32.640 40.900 33.140 ;
        RECT 40.800 1.440 40.900 1.940 ;
        RECT 40.800 35.240 40.900 35.740 ;
        RECT 40.800 17.040 40.900 17.540 ;
        RECT 40.800 36.540 40.900 37.040 ;
        RECT 40.800 7.940 40.900 8.440 ;
        RECT 40.800 37.840 40.900 38.340 ;
        RECT 40.800 18.340 40.900 18.840 ;
        RECT 40.800 39.140 40.900 39.640 ;
        RECT 40.800 4.040 40.900 4.540 ;
        RECT 40.800 40.440 40.900 40.940 ;
        RECT 40.800 19.640 40.900 20.140 ;
        RECT 40.800 41.740 40.900 42.240 ;
        RECT 40.800 9.240 40.900 9.740 ;
        RECT 40.800 43.040 40.900 43.540 ;
        RECT 40.800 20.940 40.900 21.440 ;
        RECT 47.600 24.840 47.700 25.340 ;
        RECT 47.600 26.140 47.700 26.640 ;
        RECT 47.600 44.340 47.700 44.840 ;
        RECT 47.600 27.440 47.700 27.940 ;
        RECT 47.600 28.740 47.700 29.240 ;
        RECT 47.600 30.040 47.700 30.540 ;
        RECT 47.600 31.340 47.700 31.840 ;
        RECT 47.600 32.640 47.700 33.140 ;
        RECT 42.100 35.240 42.200 35.740 ;
        RECT 42.500 35.240 42.600 35.740 ;
        RECT 43.800 35.240 43.900 35.740 ;
        RECT 44.200 35.240 44.300 35.740 ;
        RECT 45.500 35.240 45.600 35.740 ;
        RECT 45.900 35.240 46.000 35.740 ;
        RECT 47.200 35.240 47.300 35.740 ;
        RECT 47.600 35.240 47.700 35.740 ;
        RECT 48.900 35.240 49.000 35.740 ;
        RECT 49.300 35.240 49.400 35.740 ;
        RECT 50.600 35.240 50.700 35.740 ;
        RECT 51.000 35.240 51.100 35.740 ;
        RECT 52.300 35.240 52.400 35.740 ;
        RECT 52.700 35.240 52.800 35.740 ;
        RECT 54.000 35.240 54.100 35.740 ;
        RECT 54.400 35.240 54.500 35.740 ;
        RECT 47.600 36.540 47.700 37.040 ;
        RECT 47.600 37.840 47.700 38.340 ;
        RECT 47.600 39.140 47.700 39.640 ;
        RECT 47.600 46.940 47.700 47.440 ;
        RECT 47.600 40.440 47.700 40.940 ;
        RECT 47.600 41.740 47.700 42.240 ;
        RECT 47.600 43.040 47.700 43.540 ;
        RECT 54.000 46.940 54.100 47.440 ;
        RECT 50.600 44.340 50.700 44.840 ;
        RECT 51.000 44.340 51.100 44.840 ;
        RECT 54.400 46.940 54.500 47.440 ;
        RECT 52.300 44.340 52.400 44.840 ;
        RECT 48.900 36.540 49.000 37.040 ;
        RECT 49.300 36.540 49.400 37.040 ;
        RECT 50.600 36.540 50.700 37.040 ;
        RECT 51.000 36.540 51.100 37.040 ;
        RECT 52.300 36.540 52.400 37.040 ;
        RECT 52.700 36.540 52.800 37.040 ;
        RECT 54.000 36.540 54.100 37.040 ;
        RECT 54.400 36.540 54.500 37.040 ;
        RECT 52.700 44.340 52.800 44.840 ;
        RECT 48.900 37.840 49.000 38.340 ;
        RECT 49.300 37.840 49.400 38.340 ;
        RECT 50.600 37.840 50.700 38.340 ;
        RECT 51.000 37.840 51.100 38.340 ;
        RECT 52.300 37.840 52.400 38.340 ;
        RECT 52.700 37.840 52.800 38.340 ;
        RECT 54.000 37.840 54.100 38.340 ;
        RECT 54.400 37.840 54.500 38.340 ;
        RECT 52.700 46.940 52.800 47.440 ;
        RECT 48.900 39.140 49.000 39.640 ;
        RECT 49.300 39.140 49.400 39.640 ;
        RECT 50.600 39.140 50.700 39.640 ;
        RECT 51.000 39.140 51.100 39.640 ;
        RECT 52.300 39.140 52.400 39.640 ;
        RECT 52.700 39.140 52.800 39.640 ;
        RECT 54.000 39.140 54.100 39.640 ;
        RECT 54.400 39.140 54.500 39.640 ;
        RECT 54.000 44.340 54.100 44.840 ;
        RECT 54.400 44.340 54.500 44.840 ;
        RECT 48.900 40.440 49.000 40.940 ;
        RECT 49.300 40.440 49.400 40.940 ;
        RECT 50.600 40.440 50.700 40.940 ;
        RECT 51.000 40.440 51.100 40.940 ;
        RECT 52.300 40.440 52.400 40.940 ;
        RECT 52.700 40.440 52.800 40.940 ;
        RECT 54.000 40.440 54.100 40.940 ;
        RECT 54.400 40.440 54.500 40.940 ;
        RECT 48.900 46.940 49.000 47.440 ;
        RECT 49.300 46.940 49.400 47.440 ;
        RECT 48.900 44.340 49.000 44.840 ;
        RECT 48.900 41.740 49.000 42.240 ;
        RECT 49.300 41.740 49.400 42.240 ;
        RECT 50.600 41.740 50.700 42.240 ;
        RECT 51.000 41.740 51.100 42.240 ;
        RECT 52.300 41.740 52.400 42.240 ;
        RECT 52.700 41.740 52.800 42.240 ;
        RECT 54.000 41.740 54.100 42.240 ;
        RECT 54.400 41.740 54.500 42.240 ;
        RECT 50.600 46.940 50.700 47.440 ;
        RECT 51.000 46.940 51.100 47.440 ;
        RECT 49.300 44.340 49.400 44.840 ;
        RECT 48.900 43.040 49.000 43.540 ;
        RECT 49.300 43.040 49.400 43.540 ;
        RECT 50.600 43.040 50.700 43.540 ;
        RECT 51.000 43.040 51.100 43.540 ;
        RECT 52.300 43.040 52.400 43.540 ;
        RECT 52.700 43.040 52.800 43.540 ;
        RECT 54.000 43.040 54.100 43.540 ;
        RECT 54.400 43.040 54.500 43.540 ;
        RECT 52.300 46.940 52.400 47.440 ;
        RECT 44.200 46.940 44.300 47.440 ;
        RECT 47.200 46.940 47.300 47.440 ;
        RECT 42.100 37.840 42.200 38.340 ;
        RECT 42.100 40.440 42.200 40.940 ;
        RECT 42.500 40.440 42.600 40.940 ;
        RECT 43.800 40.440 43.900 40.940 ;
        RECT 44.200 40.440 44.300 40.940 ;
        RECT 45.500 40.440 45.600 40.940 ;
        RECT 45.900 40.440 46.000 40.940 ;
        RECT 47.200 40.440 47.300 40.940 ;
        RECT 42.500 37.840 42.600 38.340 ;
        RECT 43.800 37.840 43.900 38.340 ;
        RECT 44.200 37.840 44.300 38.340 ;
        RECT 45.500 37.840 45.600 38.340 ;
        RECT 45.900 37.840 46.000 38.340 ;
        RECT 47.200 37.840 47.300 38.340 ;
        RECT 42.100 36.540 42.200 37.040 ;
        RECT 42.500 36.540 42.600 37.040 ;
        RECT 43.800 36.540 43.900 37.040 ;
        RECT 44.200 36.540 44.300 37.040 ;
        RECT 45.500 36.540 45.600 37.040 ;
        RECT 42.100 41.740 42.200 42.240 ;
        RECT 42.500 41.740 42.600 42.240 ;
        RECT 43.800 41.740 43.900 42.240 ;
        RECT 44.200 41.740 44.300 42.240 ;
        RECT 45.500 41.740 45.600 42.240 ;
        RECT 45.900 41.740 46.000 42.240 ;
        RECT 47.200 41.740 47.300 42.240 ;
        RECT 45.900 36.540 46.000 37.040 ;
        RECT 47.200 36.540 47.300 37.040 ;
        RECT 45.500 44.340 45.600 44.840 ;
        RECT 45.900 44.340 46.000 44.840 ;
        RECT 45.500 46.940 45.600 47.440 ;
        RECT 45.900 46.940 46.000 47.440 ;
        RECT 42.100 39.140 42.200 39.640 ;
        RECT 42.500 39.140 42.600 39.640 ;
        RECT 43.800 39.140 43.900 39.640 ;
        RECT 44.200 39.140 44.300 39.640 ;
        RECT 45.500 39.140 45.600 39.640 ;
        RECT 42.100 43.040 42.200 43.540 ;
        RECT 42.500 43.040 42.600 43.540 ;
        RECT 43.800 43.040 43.900 43.540 ;
        RECT 44.200 43.040 44.300 43.540 ;
        RECT 45.500 43.040 45.600 43.540 ;
        RECT 45.900 43.040 46.000 43.540 ;
        RECT 47.200 43.040 47.300 43.540 ;
        RECT 45.900 39.140 46.000 39.640 ;
        RECT 47.200 39.140 47.300 39.640 ;
        RECT 44.200 44.340 44.300 44.840 ;
        RECT 42.100 44.340 42.200 44.840 ;
        RECT 42.500 44.340 42.600 44.840 ;
        RECT 47.200 44.340 47.300 44.840 ;
        RECT 43.800 44.340 43.900 44.840 ;
        RECT 42.100 46.940 42.200 47.440 ;
        RECT 42.500 46.940 42.600 47.440 ;
        RECT 43.800 46.940 43.900 47.440 ;
        RECT 44.200 26.140 44.300 26.640 ;
        RECT 45.500 26.140 45.600 26.640 ;
        RECT 42.100 31.340 42.200 31.840 ;
        RECT 42.500 31.340 42.600 31.840 ;
        RECT 43.800 31.340 43.900 31.840 ;
        RECT 44.200 31.340 44.300 31.840 ;
        RECT 45.500 31.340 45.600 31.840 ;
        RECT 45.900 31.340 46.000 31.840 ;
        RECT 47.200 31.340 47.300 31.840 ;
        RECT 45.900 26.140 46.000 26.640 ;
        RECT 47.200 26.140 47.300 26.640 ;
        RECT 44.200 24.840 44.300 25.340 ;
        RECT 42.100 32.640 42.200 33.140 ;
        RECT 42.500 32.640 42.600 33.140 ;
        RECT 43.800 32.640 43.900 33.140 ;
        RECT 44.200 32.640 44.300 33.140 ;
        RECT 45.500 32.640 45.600 33.140 ;
        RECT 45.900 32.640 46.000 33.140 ;
        RECT 47.200 32.640 47.300 33.140 ;
        RECT 45.500 24.840 45.600 25.340 ;
        RECT 45.900 24.840 46.000 25.340 ;
        RECT 42.100 27.440 42.200 27.940 ;
        RECT 42.500 27.440 42.600 27.940 ;
        RECT 43.800 27.440 43.900 27.940 ;
        RECT 44.200 27.440 44.300 27.940 ;
        RECT 45.500 27.440 45.600 27.940 ;
        RECT 45.900 27.440 46.000 27.940 ;
        RECT 47.200 27.440 47.300 27.940 ;
        RECT 47.200 24.840 47.300 25.340 ;
        RECT 42.100 24.840 42.200 25.340 ;
        RECT 42.500 24.840 42.600 25.340 ;
        RECT 42.100 28.740 42.200 29.240 ;
        RECT 42.500 28.740 42.600 29.240 ;
        RECT 43.800 28.740 43.900 29.240 ;
        RECT 44.200 28.740 44.300 29.240 ;
        RECT 45.500 28.740 45.600 29.240 ;
        RECT 45.900 28.740 46.000 29.240 ;
        RECT 47.200 28.740 47.300 29.240 ;
        RECT 43.800 24.840 43.900 25.340 ;
        RECT 42.100 26.140 42.200 26.640 ;
        RECT 42.500 26.140 42.600 26.640 ;
        RECT 42.100 30.040 42.200 30.540 ;
        RECT 42.500 30.040 42.600 30.540 ;
        RECT 43.800 30.040 43.900 30.540 ;
        RECT 44.200 30.040 44.300 30.540 ;
        RECT 45.500 30.040 45.600 30.540 ;
        RECT 45.900 30.040 46.000 30.540 ;
        RECT 47.200 30.040 47.300 30.540 ;
        RECT 43.800 26.140 43.900 26.640 ;
        RECT 51.000 30.040 51.100 30.540 ;
        RECT 52.300 30.040 52.400 30.540 ;
        RECT 52.700 30.040 52.800 30.540 ;
        RECT 54.000 30.040 54.100 30.540 ;
        RECT 54.400 30.040 54.500 30.540 ;
        RECT 52.300 27.440 52.400 27.940 ;
        RECT 52.700 27.440 52.800 27.940 ;
        RECT 54.000 27.440 54.100 27.940 ;
        RECT 54.400 27.440 54.500 27.940 ;
        RECT 50.600 26.140 50.700 26.640 ;
        RECT 51.000 26.140 51.100 26.640 ;
        RECT 52.300 26.140 52.400 26.640 ;
        RECT 52.700 26.140 52.800 26.640 ;
        RECT 54.000 26.140 54.100 26.640 ;
        RECT 54.400 26.140 54.500 26.640 ;
        RECT 48.900 31.340 49.000 31.840 ;
        RECT 49.300 31.340 49.400 31.840 ;
        RECT 50.600 31.340 50.700 31.840 ;
        RECT 51.000 31.340 51.100 31.840 ;
        RECT 52.300 31.340 52.400 31.840 ;
        RECT 52.700 31.340 52.800 31.840 ;
        RECT 54.000 31.340 54.100 31.840 ;
        RECT 54.400 31.340 54.500 31.840 ;
        RECT 50.600 24.840 50.700 25.340 ;
        RECT 51.000 24.840 51.100 25.340 ;
        RECT 52.300 24.840 52.400 25.340 ;
        RECT 52.700 24.840 52.800 25.340 ;
        RECT 48.900 28.740 49.000 29.240 ;
        RECT 49.300 28.740 49.400 29.240 ;
        RECT 50.600 28.740 50.700 29.240 ;
        RECT 51.000 28.740 51.100 29.240 ;
        RECT 52.300 28.740 52.400 29.240 ;
        RECT 52.700 28.740 52.800 29.240 ;
        RECT 48.900 32.640 49.000 33.140 ;
        RECT 49.300 32.640 49.400 33.140 ;
        RECT 50.600 32.640 50.700 33.140 ;
        RECT 51.000 32.640 51.100 33.140 ;
        RECT 52.300 32.640 52.400 33.140 ;
        RECT 52.700 32.640 52.800 33.140 ;
        RECT 54.000 32.640 54.100 33.140 ;
        RECT 54.400 32.640 54.500 33.140 ;
        RECT 54.000 28.740 54.100 29.240 ;
        RECT 54.400 28.740 54.500 29.240 ;
        RECT 54.000 24.840 54.100 25.340 ;
        RECT 54.400 24.840 54.500 25.340 ;
        RECT 48.900 24.840 49.000 25.340 ;
        RECT 49.300 24.840 49.400 25.340 ;
        RECT 48.900 26.140 49.000 26.640 ;
        RECT 49.300 26.140 49.400 26.640 ;
        RECT 48.900 27.440 49.000 27.940 ;
        RECT 49.300 27.440 49.400 27.940 ;
        RECT 50.600 27.440 50.700 27.940 ;
        RECT 51.000 27.440 51.100 27.940 ;
        RECT 48.900 30.040 49.000 30.540 ;
        RECT 49.300 30.040 49.400 30.540 ;
        RECT 50.600 30.040 50.700 30.540 ;
        RECT 34.000 44.340 34.100 44.840 ;
        RECT 28.500 35.240 28.600 35.740 ;
        RECT 28.900 35.240 29.000 35.740 ;
        RECT 30.200 35.240 30.300 35.740 ;
        RECT 30.600 35.240 30.700 35.740 ;
        RECT 31.900 35.240 32.000 35.740 ;
        RECT 32.300 35.240 32.400 35.740 ;
        RECT 33.600 35.240 33.700 35.740 ;
        RECT 34.000 35.240 34.100 35.740 ;
        RECT 35.300 35.240 35.400 35.740 ;
        RECT 35.700 35.240 35.800 35.740 ;
        RECT 37.000 35.240 37.100 35.740 ;
        RECT 37.400 35.240 37.500 35.740 ;
        RECT 38.700 35.240 38.800 35.740 ;
        RECT 39.100 35.240 39.200 35.740 ;
        RECT 40.400 35.240 40.500 35.740 ;
        RECT 34.000 28.740 34.100 29.240 ;
        RECT 34.000 36.540 34.100 37.040 ;
        RECT 34.000 26.140 34.100 26.640 ;
        RECT 34.000 37.840 34.100 38.340 ;
        RECT 34.000 30.040 34.100 30.540 ;
        RECT 34.000 39.140 34.100 39.640 ;
        RECT 34.000 46.940 34.100 47.440 ;
        RECT 34.000 40.440 34.100 40.940 ;
        RECT 34.000 31.340 34.100 31.840 ;
        RECT 34.000 24.840 34.100 25.340 ;
        RECT 34.000 41.740 34.100 42.240 ;
        RECT 34.000 27.440 34.100 27.940 ;
        RECT 34.000 32.640 34.100 33.140 ;
        RECT 34.000 43.040 34.100 43.540 ;
        RECT 37.400 36.540 37.500 37.040 ;
        RECT 38.700 36.540 38.800 37.040 ;
        RECT 39.100 36.540 39.200 37.040 ;
        RECT 40.400 36.540 40.500 37.040 ;
        RECT 40.400 44.340 40.500 44.840 ;
        RECT 37.000 44.340 37.100 44.840 ;
        RECT 39.100 46.940 39.200 47.440 ;
        RECT 35.300 37.840 35.400 38.340 ;
        RECT 35.700 37.840 35.800 38.340 ;
        RECT 37.000 37.840 37.100 38.340 ;
        RECT 37.400 37.840 37.500 38.340 ;
        RECT 38.700 37.840 38.800 38.340 ;
        RECT 39.100 37.840 39.200 38.340 ;
        RECT 40.400 37.840 40.500 38.340 ;
        RECT 40.400 46.940 40.500 47.440 ;
        RECT 38.700 46.940 38.800 47.440 ;
        RECT 35.300 39.140 35.400 39.640 ;
        RECT 35.700 39.140 35.800 39.640 ;
        RECT 37.000 39.140 37.100 39.640 ;
        RECT 37.400 39.140 37.500 39.640 ;
        RECT 38.700 39.140 38.800 39.640 ;
        RECT 39.100 39.140 39.200 39.640 ;
        RECT 40.400 39.140 40.500 39.640 ;
        RECT 37.400 44.340 37.500 44.840 ;
        RECT 35.300 46.940 35.400 47.440 ;
        RECT 35.300 44.340 35.400 44.840 ;
        RECT 35.300 40.440 35.400 40.940 ;
        RECT 35.700 40.440 35.800 40.940 ;
        RECT 37.000 40.440 37.100 40.940 ;
        RECT 37.400 40.440 37.500 40.940 ;
        RECT 38.700 40.440 38.800 40.940 ;
        RECT 39.100 40.440 39.200 40.940 ;
        RECT 40.400 40.440 40.500 40.940 ;
        RECT 38.700 44.340 38.800 44.840 ;
        RECT 39.100 44.340 39.200 44.840 ;
        RECT 35.700 44.340 35.800 44.840 ;
        RECT 35.300 41.740 35.400 42.240 ;
        RECT 35.700 41.740 35.800 42.240 ;
        RECT 37.000 41.740 37.100 42.240 ;
        RECT 37.400 41.740 37.500 42.240 ;
        RECT 38.700 41.740 38.800 42.240 ;
        RECT 39.100 41.740 39.200 42.240 ;
        RECT 40.400 41.740 40.500 42.240 ;
        RECT 35.300 36.540 35.400 37.040 ;
        RECT 35.700 36.540 35.800 37.040 ;
        RECT 37.000 36.540 37.100 37.040 ;
        RECT 35.300 43.040 35.400 43.540 ;
        RECT 35.700 43.040 35.800 43.540 ;
        RECT 37.000 43.040 37.100 43.540 ;
        RECT 37.400 43.040 37.500 43.540 ;
        RECT 38.700 43.040 38.800 43.540 ;
        RECT 39.100 43.040 39.200 43.540 ;
        RECT 40.400 43.040 40.500 43.540 ;
        RECT 35.700 46.940 35.800 47.440 ;
        RECT 37.000 46.940 37.100 47.440 ;
        RECT 37.400 46.940 37.500 47.440 ;
        RECT 33.600 37.840 33.700 38.340 ;
        RECT 30.600 36.540 30.700 37.040 ;
        RECT 28.500 40.440 28.600 40.940 ;
        RECT 28.900 40.440 29.000 40.940 ;
        RECT 30.200 40.440 30.300 40.940 ;
        RECT 30.600 40.440 30.700 40.940 ;
        RECT 31.900 40.440 32.000 40.940 ;
        RECT 32.300 40.440 32.400 40.940 ;
        RECT 33.600 40.440 33.700 40.940 ;
        RECT 31.900 36.540 32.000 37.040 ;
        RECT 32.300 36.540 32.400 37.040 ;
        RECT 33.600 36.540 33.700 37.040 ;
        RECT 28.500 36.540 28.600 37.040 ;
        RECT 28.900 36.540 29.000 37.040 ;
        RECT 30.200 44.340 30.300 44.840 ;
        RECT 30.600 44.340 30.700 44.840 ;
        RECT 31.900 44.340 32.000 44.840 ;
        RECT 33.600 44.340 33.700 44.840 ;
        RECT 28.500 39.140 28.600 39.640 ;
        RECT 28.500 41.740 28.600 42.240 ;
        RECT 28.900 41.740 29.000 42.240 ;
        RECT 30.200 41.740 30.300 42.240 ;
        RECT 30.600 41.740 30.700 42.240 ;
        RECT 31.900 41.740 32.000 42.240 ;
        RECT 32.300 41.740 32.400 42.240 ;
        RECT 33.600 41.740 33.700 42.240 ;
        RECT 28.900 39.140 29.000 39.640 ;
        RECT 30.200 39.140 30.300 39.640 ;
        RECT 30.600 39.140 30.700 39.640 ;
        RECT 31.900 39.140 32.000 39.640 ;
        RECT 32.300 39.140 32.400 39.640 ;
        RECT 33.600 39.140 33.700 39.640 ;
        RECT 32.300 44.340 32.400 44.840 ;
        RECT 30.200 36.540 30.300 37.040 ;
        RECT 28.500 37.840 28.600 38.340 ;
        RECT 28.900 37.840 29.000 38.340 ;
        RECT 28.500 43.040 28.600 43.540 ;
        RECT 28.900 43.040 29.000 43.540 ;
        RECT 30.200 43.040 30.300 43.540 ;
        RECT 30.600 43.040 30.700 43.540 ;
        RECT 31.900 43.040 32.000 43.540 ;
        RECT 32.300 43.040 32.400 43.540 ;
        RECT 33.600 43.040 33.700 43.540 ;
        RECT 30.200 37.840 30.300 38.340 ;
        RECT 30.600 37.840 30.700 38.340 ;
        RECT 31.900 37.840 32.000 38.340 ;
        RECT 32.300 37.840 32.400 38.340 ;
        RECT 28.500 46.940 28.600 47.440 ;
        RECT 28.900 46.940 29.000 47.440 ;
        RECT 30.200 46.940 30.300 47.440 ;
        RECT 30.600 46.940 30.700 47.440 ;
        RECT 31.900 46.940 32.000 47.440 ;
        RECT 32.300 46.940 32.400 47.440 ;
        RECT 33.600 46.940 33.700 47.440 ;
        RECT 28.500 44.340 28.600 44.840 ;
        RECT 28.900 44.340 29.000 44.840 ;
        RECT 30.200 27.440 30.300 27.940 ;
        RECT 30.600 27.440 30.700 27.940 ;
        RECT 30.600 28.740 30.700 29.240 ;
        RECT 31.900 28.740 32.000 29.240 ;
        RECT 32.300 28.740 32.400 29.240 ;
        RECT 33.600 28.740 33.700 29.240 ;
        RECT 28.500 24.840 28.600 25.340 ;
        RECT 28.900 24.840 29.000 25.340 ;
        RECT 30.200 24.840 30.300 25.340 ;
        RECT 30.600 24.840 30.700 25.340 ;
        RECT 28.500 31.340 28.600 31.840 ;
        RECT 28.900 31.340 29.000 31.840 ;
        RECT 30.200 31.340 30.300 31.840 ;
        RECT 30.600 31.340 30.700 31.840 ;
        RECT 31.900 31.340 32.000 31.840 ;
        RECT 28.500 28.740 28.600 29.240 ;
        RECT 28.900 28.740 29.000 29.240 ;
        RECT 31.900 27.440 32.000 27.940 ;
        RECT 32.300 27.440 32.400 27.940 ;
        RECT 33.600 27.440 33.700 27.940 ;
        RECT 28.500 26.140 28.600 26.640 ;
        RECT 28.500 32.640 28.600 33.140 ;
        RECT 28.900 32.640 29.000 33.140 ;
        RECT 30.200 32.640 30.300 33.140 ;
        RECT 30.600 32.640 30.700 33.140 ;
        RECT 31.900 32.640 32.000 33.140 ;
        RECT 32.300 32.640 32.400 33.140 ;
        RECT 33.600 32.640 33.700 33.140 ;
        RECT 28.900 26.140 29.000 26.640 ;
        RECT 30.200 26.140 30.300 26.640 ;
        RECT 30.600 26.140 30.700 26.640 ;
        RECT 31.900 26.140 32.000 26.640 ;
        RECT 32.300 26.140 32.400 26.640 ;
        RECT 33.600 26.140 33.700 26.640 ;
        RECT 30.200 28.740 30.300 29.240 ;
        RECT 28.500 30.040 28.600 30.540 ;
        RECT 30.200 30.040 30.300 30.540 ;
        RECT 30.600 30.040 30.700 30.540 ;
        RECT 31.900 30.040 32.000 30.540 ;
        RECT 32.300 30.040 32.400 30.540 ;
        RECT 32.300 31.340 32.400 31.840 ;
        RECT 33.600 31.340 33.700 31.840 ;
        RECT 33.600 30.040 33.700 30.540 ;
        RECT 31.900 24.840 32.000 25.340 ;
        RECT 32.300 24.840 32.400 25.340 ;
        RECT 33.600 24.840 33.700 25.340 ;
        RECT 28.900 30.040 29.000 30.540 ;
        RECT 28.500 27.440 28.600 27.940 ;
        RECT 28.900 27.440 29.000 27.940 ;
        RECT 35.300 27.440 35.400 27.940 ;
        RECT 35.700 27.440 35.800 27.940 ;
        RECT 37.000 27.440 37.100 27.940 ;
        RECT 37.400 27.440 37.500 27.940 ;
        RECT 38.700 27.440 38.800 27.940 ;
        RECT 39.100 27.440 39.200 27.940 ;
        RECT 40.400 31.340 40.500 31.840 ;
        RECT 35.300 30.040 35.400 30.540 ;
        RECT 35.700 30.040 35.800 30.540 ;
        RECT 37.000 30.040 37.100 30.540 ;
        RECT 37.400 30.040 37.500 30.540 ;
        RECT 38.700 30.040 38.800 30.540 ;
        RECT 39.100 30.040 39.200 30.540 ;
        RECT 40.400 30.040 40.500 30.540 ;
        RECT 37.400 26.140 37.500 26.640 ;
        RECT 38.700 26.140 38.800 26.640 ;
        RECT 39.100 26.140 39.200 26.640 ;
        RECT 40.400 26.140 40.500 26.640 ;
        RECT 39.100 28.740 39.200 29.240 ;
        RECT 40.400 28.740 40.500 29.240 ;
        RECT 35.300 28.740 35.400 29.240 ;
        RECT 35.700 28.740 35.800 29.240 ;
        RECT 35.300 26.140 35.400 26.640 ;
        RECT 35.700 26.140 35.800 26.640 ;
        RECT 37.000 26.140 37.100 26.640 ;
        RECT 37.000 28.740 37.100 29.240 ;
        RECT 37.400 28.740 37.500 29.240 ;
        RECT 38.700 28.740 38.800 29.240 ;
        RECT 35.300 31.340 35.400 31.840 ;
        RECT 35.300 32.640 35.400 33.140 ;
        RECT 35.700 32.640 35.800 33.140 ;
        RECT 37.000 32.640 37.100 33.140 ;
        RECT 37.400 32.640 37.500 33.140 ;
        RECT 38.700 32.640 38.800 33.140 ;
        RECT 39.100 32.640 39.200 33.140 ;
        RECT 40.400 32.640 40.500 33.140 ;
        RECT 40.400 27.440 40.500 27.940 ;
        RECT 35.300 24.840 35.400 25.340 ;
        RECT 35.700 24.840 35.800 25.340 ;
        RECT 37.000 24.840 37.100 25.340 ;
        RECT 37.400 24.840 37.500 25.340 ;
        RECT 38.700 24.840 38.800 25.340 ;
        RECT 39.100 24.840 39.200 25.340 ;
        RECT 40.400 24.840 40.500 25.340 ;
        RECT 35.700 31.340 35.800 31.840 ;
        RECT 37.000 31.340 37.100 31.840 ;
        RECT 37.400 31.340 37.500 31.840 ;
        RECT 38.700 31.340 38.800 31.840 ;
        RECT 39.100 31.340 39.200 31.840 ;
        RECT 34.000 15.740 34.100 16.240 ;
        RECT 34.000 5.340 34.100 5.840 ;
        RECT 34.000 18.340 34.100 18.840 ;
        RECT 34.000 14.440 34.100 14.940 ;
        RECT 34.000 1.440 34.100 1.940 ;
        RECT 34.000 4.040 34.100 4.540 ;
        RECT 28.500 11.840 28.600 12.340 ;
        RECT 28.900 11.840 29.000 12.340 ;
        RECT 30.200 11.840 30.300 12.340 ;
        RECT 30.600 11.840 30.700 12.340 ;
        RECT 31.900 11.840 32.000 12.340 ;
        RECT 32.300 11.840 32.400 12.340 ;
        RECT 33.600 11.840 33.700 12.340 ;
        RECT 34.000 11.840 34.100 12.340 ;
        RECT 35.300 11.840 35.400 12.340 ;
        RECT 34.000 19.640 34.100 20.140 ;
        RECT 34.000 6.640 34.100 7.140 ;
        RECT 34.000 17.040 34.100 17.540 ;
        RECT 34.000 2.740 34.100 3.240 ;
        RECT 34.000 9.240 34.100 9.740 ;
        RECT 35.700 11.840 35.800 12.340 ;
        RECT 37.000 11.840 37.100 12.340 ;
        RECT 37.400 11.840 37.500 12.340 ;
        RECT 38.700 11.840 38.800 12.340 ;
        RECT 39.100 11.840 39.200 12.340 ;
        RECT 40.400 11.840 40.500 12.340 ;
        RECT 34.000 0.140 34.100 0.640 ;
        RECT 34.000 7.940 34.100 8.440 ;
        RECT 34.000 20.940 34.100 21.440 ;
        RECT 34.000 13.140 34.100 13.640 ;
        RECT 40.400 14.440 40.500 14.940 ;
        RECT 35.300 15.740 35.400 16.240 ;
        RECT 35.700 15.740 35.800 16.240 ;
        RECT 37.000 15.740 37.100 16.240 ;
        RECT 37.400 15.740 37.500 16.240 ;
        RECT 38.700 15.740 38.800 16.240 ;
        RECT 39.100 15.740 39.200 16.240 ;
        RECT 40.400 15.740 40.500 16.240 ;
        RECT 38.700 13.140 38.800 13.640 ;
        RECT 39.100 13.140 39.200 13.640 ;
        RECT 40.400 13.140 40.500 13.640 ;
        RECT 37.000 13.140 37.100 13.640 ;
        RECT 37.400 13.140 37.500 13.640 ;
        RECT 35.300 19.640 35.400 20.140 ;
        RECT 35.700 19.640 35.800 20.140 ;
        RECT 37.000 19.640 37.100 20.140 ;
        RECT 37.400 19.640 37.500 20.140 ;
        RECT 38.700 19.640 38.800 20.140 ;
        RECT 39.100 19.640 39.200 20.140 ;
        RECT 40.400 19.640 40.500 20.140 ;
        RECT 35.300 18.340 35.400 18.840 ;
        RECT 35.700 18.340 35.800 18.840 ;
        RECT 35.300 17.040 35.400 17.540 ;
        RECT 35.700 17.040 35.800 17.540 ;
        RECT 37.000 17.040 37.100 17.540 ;
        RECT 37.400 17.040 37.500 17.540 ;
        RECT 38.700 17.040 38.800 17.540 ;
        RECT 39.100 17.040 39.200 17.540 ;
        RECT 40.400 17.040 40.500 17.540 ;
        RECT 37.000 18.340 37.100 18.840 ;
        RECT 37.400 18.340 37.500 18.840 ;
        RECT 38.700 18.340 38.800 18.840 ;
        RECT 39.100 18.340 39.200 18.840 ;
        RECT 40.400 18.340 40.500 18.840 ;
        RECT 35.700 13.140 35.800 13.640 ;
        RECT 35.300 14.440 35.400 14.940 ;
        RECT 35.700 14.440 35.800 14.940 ;
        RECT 37.000 14.440 37.100 14.940 ;
        RECT 37.400 14.440 37.500 14.940 ;
        RECT 38.700 14.440 38.800 14.940 ;
        RECT 35.300 20.940 35.400 21.440 ;
        RECT 35.700 20.940 35.800 21.440 ;
        RECT 37.000 20.940 37.100 21.440 ;
        RECT 37.400 20.940 37.500 21.440 ;
        RECT 38.700 20.940 38.800 21.440 ;
        RECT 39.100 20.940 39.200 21.440 ;
        RECT 40.400 20.940 40.500 21.440 ;
        RECT 39.100 14.440 39.200 14.940 ;
        RECT 35.300 13.140 35.400 13.640 ;
        RECT 28.500 17.040 28.600 17.540 ;
        RECT 28.900 17.040 29.000 17.540 ;
        RECT 30.200 17.040 30.300 17.540 ;
        RECT 30.600 17.040 30.700 17.540 ;
        RECT 31.900 17.040 32.000 17.540 ;
        RECT 32.300 17.040 32.400 17.540 ;
        RECT 33.600 17.040 33.700 17.540 ;
        RECT 32.300 18.340 32.400 18.840 ;
        RECT 33.600 18.340 33.700 18.840 ;
        RECT 32.300 15.740 32.400 16.240 ;
        RECT 33.600 15.740 33.700 16.240 ;
        RECT 28.500 15.740 28.600 16.240 ;
        RECT 28.900 15.740 29.000 16.240 ;
        RECT 30.200 15.740 30.300 16.240 ;
        RECT 30.600 15.740 30.700 16.240 ;
        RECT 31.900 15.740 32.000 16.240 ;
        RECT 28.500 14.440 28.600 14.940 ;
        RECT 30.600 14.440 30.700 14.940 ;
        RECT 31.900 14.440 32.000 14.940 ;
        RECT 28.500 19.640 28.600 20.140 ;
        RECT 28.900 19.640 29.000 20.140 ;
        RECT 30.200 19.640 30.300 20.140 ;
        RECT 30.600 19.640 30.700 20.140 ;
        RECT 31.900 19.640 32.000 20.140 ;
        RECT 28.500 13.140 28.600 13.640 ;
        RECT 28.900 13.140 29.000 13.640 ;
        RECT 30.200 13.140 30.300 13.640 ;
        RECT 30.600 13.140 30.700 13.640 ;
        RECT 31.900 13.140 32.000 13.640 ;
        RECT 32.300 13.140 32.400 13.640 ;
        RECT 32.300 19.640 32.400 20.140 ;
        RECT 28.500 20.940 28.600 21.440 ;
        RECT 28.900 20.940 29.000 21.440 ;
        RECT 30.200 20.940 30.300 21.440 ;
        RECT 30.600 20.940 30.700 21.440 ;
        RECT 31.900 20.940 32.000 21.440 ;
        RECT 32.300 20.940 32.400 21.440 ;
        RECT 33.600 20.940 33.700 21.440 ;
        RECT 33.600 19.640 33.700 20.140 ;
        RECT 32.300 14.440 32.400 14.940 ;
        RECT 33.600 14.440 33.700 14.940 ;
        RECT 28.900 14.440 29.000 14.940 ;
        RECT 30.200 14.440 30.300 14.940 ;
        RECT 28.500 18.340 28.600 18.840 ;
        RECT 28.900 18.340 29.000 18.840 ;
        RECT 30.200 18.340 30.300 18.840 ;
        RECT 33.600 13.140 33.700 13.640 ;
        RECT 30.600 18.340 30.700 18.840 ;
        RECT 31.900 18.340 32.000 18.840 ;
        RECT 28.500 6.640 28.600 7.140 ;
        RECT 28.900 6.640 29.000 7.140 ;
        RECT 33.600 2.740 33.700 3.240 ;
        RECT 30.200 6.640 30.300 7.140 ;
        RECT 28.500 9.240 28.600 9.740 ;
        RECT 28.900 9.240 29.000 9.740 ;
        RECT 30.200 9.240 30.300 9.740 ;
        RECT 30.600 9.240 30.700 9.740 ;
        RECT 31.900 9.240 32.000 9.740 ;
        RECT 32.300 9.240 32.400 9.740 ;
        RECT 33.600 9.240 33.700 9.740 ;
        RECT 30.600 6.640 30.700 7.140 ;
        RECT 31.900 6.640 32.000 7.140 ;
        RECT 32.300 6.640 32.400 7.140 ;
        RECT 33.600 5.340 33.700 5.840 ;
        RECT 28.500 4.040 28.600 4.540 ;
        RECT 28.900 4.040 29.000 4.540 ;
        RECT 30.200 4.040 30.300 4.540 ;
        RECT 32.300 0.140 32.400 0.640 ;
        RECT 33.600 0.140 33.700 0.640 ;
        RECT 30.600 4.040 30.700 4.540 ;
        RECT 28.500 5.340 28.600 5.840 ;
        RECT 28.900 5.340 29.000 5.840 ;
        RECT 30.200 5.340 30.300 5.840 ;
        RECT 31.900 4.040 32.000 4.540 ;
        RECT 32.300 4.040 32.400 4.540 ;
        RECT 33.600 4.040 33.700 4.540 ;
        RECT 30.600 5.340 30.700 5.840 ;
        RECT 28.500 0.140 28.600 0.640 ;
        RECT 28.900 0.140 29.000 0.640 ;
        RECT 28.500 7.940 28.600 8.440 ;
        RECT 28.900 7.940 29.000 8.440 ;
        RECT 30.200 7.940 30.300 8.440 ;
        RECT 30.600 7.940 30.700 8.440 ;
        RECT 31.900 7.940 32.000 8.440 ;
        RECT 32.300 7.940 32.400 8.440 ;
        RECT 33.600 7.940 33.700 8.440 ;
        RECT 30.200 0.140 30.300 0.640 ;
        RECT 30.600 0.140 30.700 0.640 ;
        RECT 31.900 0.140 32.000 0.640 ;
        RECT 31.900 5.340 32.000 5.840 ;
        RECT 33.600 6.640 33.700 7.140 ;
        RECT 32.300 5.340 32.400 5.840 ;
        RECT 28.500 1.440 28.600 1.940 ;
        RECT 28.900 1.440 29.000 1.940 ;
        RECT 30.200 1.440 30.300 1.940 ;
        RECT 30.600 1.440 30.700 1.940 ;
        RECT 31.900 1.440 32.000 1.940 ;
        RECT 32.300 1.440 32.400 1.940 ;
        RECT 33.600 1.440 33.700 1.940 ;
        RECT 28.500 2.740 28.600 3.240 ;
        RECT 28.900 2.740 29.000 3.240 ;
        RECT 30.200 2.740 30.300 3.240 ;
        RECT 30.600 2.740 30.700 3.240 ;
        RECT 31.900 2.740 32.000 3.240 ;
        RECT 32.300 2.740 32.400 3.240 ;
        RECT 37.000 9.240 37.100 9.740 ;
        RECT 37.400 9.240 37.500 9.740 ;
        RECT 38.700 9.240 38.800 9.740 ;
        RECT 39.100 9.240 39.200 9.740 ;
        RECT 40.400 9.240 40.500 9.740 ;
        RECT 38.700 5.340 38.800 5.840 ;
        RECT 39.100 5.340 39.200 5.840 ;
        RECT 35.300 4.040 35.400 4.540 ;
        RECT 35.300 6.640 35.400 7.140 ;
        RECT 35.700 4.040 35.800 4.540 ;
        RECT 37.000 4.040 37.100 4.540 ;
        RECT 37.400 4.040 37.500 4.540 ;
        RECT 38.700 4.040 38.800 4.540 ;
        RECT 39.100 4.040 39.200 4.540 ;
        RECT 40.400 4.040 40.500 4.540 ;
        RECT 38.700 1.440 38.800 1.940 ;
        RECT 39.100 1.440 39.200 1.940 ;
        RECT 40.400 1.440 40.500 1.940 ;
        RECT 37.400 0.140 37.500 0.640 ;
        RECT 38.700 0.140 38.800 0.640 ;
        RECT 39.100 0.140 39.200 0.640 ;
        RECT 40.400 0.140 40.500 0.640 ;
        RECT 40.400 5.340 40.500 5.840 ;
        RECT 35.300 0.140 35.400 0.640 ;
        RECT 35.700 6.640 35.800 7.140 ;
        RECT 37.000 6.640 37.100 7.140 ;
        RECT 37.400 6.640 37.500 7.140 ;
        RECT 38.700 6.640 38.800 7.140 ;
        RECT 39.100 6.640 39.200 7.140 ;
        RECT 40.400 6.640 40.500 7.140 ;
        RECT 35.300 1.440 35.400 1.940 ;
        RECT 35.300 7.940 35.400 8.440 ;
        RECT 35.700 7.940 35.800 8.440 ;
        RECT 37.000 7.940 37.100 8.440 ;
        RECT 37.400 7.940 37.500 8.440 ;
        RECT 38.700 7.940 38.800 8.440 ;
        RECT 39.100 7.940 39.200 8.440 ;
        RECT 40.400 7.940 40.500 8.440 ;
        RECT 35.700 1.440 35.800 1.940 ;
        RECT 35.300 2.740 35.400 3.240 ;
        RECT 35.700 2.740 35.800 3.240 ;
        RECT 37.000 2.740 37.100 3.240 ;
        RECT 37.400 2.740 37.500 3.240 ;
        RECT 38.700 2.740 38.800 3.240 ;
        RECT 39.100 2.740 39.200 3.240 ;
        RECT 40.400 2.740 40.500 3.240 ;
        RECT 37.000 1.440 37.100 1.940 ;
        RECT 37.400 1.440 37.500 1.940 ;
        RECT 35.700 0.140 35.800 0.640 ;
        RECT 37.000 0.140 37.100 0.640 ;
        RECT 35.300 5.340 35.400 5.840 ;
        RECT 35.700 5.340 35.800 5.840 ;
        RECT 37.000 5.340 37.100 5.840 ;
        RECT 37.400 5.340 37.500 5.840 ;
        RECT 35.300 9.240 35.400 9.740 ;
        RECT 35.700 9.240 35.800 9.740 ;
        RECT 47.600 6.640 47.700 7.140 ;
        RECT 42.100 11.840 42.200 12.340 ;
        RECT 42.500 11.840 42.600 12.340 ;
        RECT 43.800 11.840 43.900 12.340 ;
        RECT 44.200 11.840 44.300 12.340 ;
        RECT 45.500 11.840 45.600 12.340 ;
        RECT 45.900 11.840 46.000 12.340 ;
        RECT 47.200 11.840 47.300 12.340 ;
        RECT 47.600 11.840 47.700 12.340 ;
        RECT 48.900 11.840 49.000 12.340 ;
        RECT 49.300 11.840 49.400 12.340 ;
        RECT 50.600 11.840 50.700 12.340 ;
        RECT 51.000 11.840 51.100 12.340 ;
        RECT 52.300 11.840 52.400 12.340 ;
        RECT 52.700 11.840 52.800 12.340 ;
        RECT 54.000 11.840 54.100 12.340 ;
        RECT 54.400 11.840 54.500 12.340 ;
        RECT 47.600 0.140 47.700 0.640 ;
        RECT 47.600 4.040 47.700 4.540 ;
        RECT 47.600 17.040 47.700 17.540 ;
        RECT 47.600 14.440 47.700 14.940 ;
        RECT 47.600 15.740 47.700 16.240 ;
        RECT 47.600 19.640 47.700 20.140 ;
        RECT 47.600 5.340 47.700 5.840 ;
        RECT 47.600 7.940 47.700 8.440 ;
        RECT 47.600 2.740 47.700 3.240 ;
        RECT 47.600 9.240 47.700 9.740 ;
        RECT 47.600 13.140 47.700 13.640 ;
        RECT 47.600 1.440 47.700 1.940 ;
        RECT 47.600 18.340 47.700 18.840 ;
        RECT 47.600 20.940 47.700 21.440 ;
        RECT 50.600 14.440 50.700 14.940 ;
        RECT 51.000 14.440 51.100 14.940 ;
        RECT 52.300 14.440 52.400 14.940 ;
        RECT 52.700 14.440 52.800 14.940 ;
        RECT 54.000 14.440 54.100 14.940 ;
        RECT 54.400 14.440 54.500 14.940 ;
        RECT 49.300 17.040 49.400 17.540 ;
        RECT 48.900 15.740 49.000 16.240 ;
        RECT 49.300 15.740 49.400 16.240 ;
        RECT 50.600 15.740 50.700 16.240 ;
        RECT 51.000 15.740 51.100 16.240 ;
        RECT 52.300 15.740 52.400 16.240 ;
        RECT 52.700 15.740 52.800 16.240 ;
        RECT 54.000 15.740 54.100 16.240 ;
        RECT 54.400 15.740 54.500 16.240 ;
        RECT 50.600 17.040 50.700 17.540 ;
        RECT 48.900 19.640 49.000 20.140 ;
        RECT 49.300 19.640 49.400 20.140 ;
        RECT 50.600 19.640 50.700 20.140 ;
        RECT 51.000 19.640 51.100 20.140 ;
        RECT 52.300 19.640 52.400 20.140 ;
        RECT 52.700 19.640 52.800 20.140 ;
        RECT 54.000 19.640 54.100 20.140 ;
        RECT 54.400 19.640 54.500 20.140 ;
        RECT 51.000 17.040 51.100 17.540 ;
        RECT 52.300 17.040 52.400 17.540 ;
        RECT 52.700 17.040 52.800 17.540 ;
        RECT 54.000 17.040 54.100 17.540 ;
        RECT 54.400 17.040 54.500 17.540 ;
        RECT 48.900 13.140 49.000 13.640 ;
        RECT 49.300 13.140 49.400 13.640 ;
        RECT 50.600 13.140 50.700 13.640 ;
        RECT 51.000 13.140 51.100 13.640 ;
        RECT 52.300 13.140 52.400 13.640 ;
        RECT 52.700 13.140 52.800 13.640 ;
        RECT 54.000 13.140 54.100 13.640 ;
        RECT 54.400 13.140 54.500 13.640 ;
        RECT 48.900 17.040 49.000 17.540 ;
        RECT 48.900 14.440 49.000 14.940 ;
        RECT 48.900 18.340 49.000 18.840 ;
        RECT 49.300 18.340 49.400 18.840 ;
        RECT 50.600 18.340 50.700 18.840 ;
        RECT 51.000 18.340 51.100 18.840 ;
        RECT 52.300 18.340 52.400 18.840 ;
        RECT 52.700 18.340 52.800 18.840 ;
        RECT 54.000 18.340 54.100 18.840 ;
        RECT 54.400 18.340 54.500 18.840 ;
        RECT 49.300 14.440 49.400 14.940 ;
        RECT 48.900 20.940 49.000 21.440 ;
        RECT 49.300 20.940 49.400 21.440 ;
        RECT 50.600 20.940 50.700 21.440 ;
        RECT 51.000 20.940 51.100 21.440 ;
        RECT 52.300 20.940 52.400 21.440 ;
        RECT 52.700 20.940 52.800 21.440 ;
        RECT 54.000 20.940 54.100 21.440 ;
        RECT 54.400 20.940 54.500 21.440 ;
        RECT 42.100 13.140 42.200 13.640 ;
        RECT 42.500 13.140 42.600 13.640 ;
        RECT 43.800 13.140 43.900 13.640 ;
        RECT 44.200 13.140 44.300 13.640 ;
        RECT 45.500 13.140 45.600 13.640 ;
        RECT 45.900 13.140 46.000 13.640 ;
        RECT 47.200 13.140 47.300 13.640 ;
        RECT 44.200 14.440 44.300 14.940 ;
        RECT 45.500 14.440 45.600 14.940 ;
        RECT 45.900 14.440 46.000 14.940 ;
        RECT 47.200 14.440 47.300 14.940 ;
        RECT 43.800 17.040 43.900 17.540 ;
        RECT 44.200 17.040 44.300 17.540 ;
        RECT 45.500 17.040 45.600 17.540 ;
        RECT 45.900 17.040 46.000 17.540 ;
        RECT 42.100 19.640 42.200 20.140 ;
        RECT 42.500 19.640 42.600 20.140 ;
        RECT 42.100 18.340 42.200 18.840 ;
        RECT 42.500 18.340 42.600 18.840 ;
        RECT 43.800 18.340 43.900 18.840 ;
        RECT 44.200 18.340 44.300 18.840 ;
        RECT 45.500 18.340 45.600 18.840 ;
        RECT 45.900 18.340 46.000 18.840 ;
        RECT 47.200 18.340 47.300 18.840 ;
        RECT 43.800 19.640 43.900 20.140 ;
        RECT 44.200 19.640 44.300 20.140 ;
        RECT 45.500 19.640 45.600 20.140 ;
        RECT 45.900 19.640 46.000 20.140 ;
        RECT 47.200 19.640 47.300 20.140 ;
        RECT 47.200 17.040 47.300 17.540 ;
        RECT 42.100 17.040 42.200 17.540 ;
        RECT 42.500 17.040 42.600 17.540 ;
        RECT 42.100 14.440 42.200 14.940 ;
        RECT 42.100 20.940 42.200 21.440 ;
        RECT 42.500 20.940 42.600 21.440 ;
        RECT 43.800 20.940 43.900 21.440 ;
        RECT 44.200 20.940 44.300 21.440 ;
        RECT 45.500 20.940 45.600 21.440 ;
        RECT 45.900 20.940 46.000 21.440 ;
        RECT 47.200 20.940 47.300 21.440 ;
        RECT 42.500 14.440 42.600 14.940 ;
        RECT 42.100 15.740 42.200 16.240 ;
        RECT 42.500 15.740 42.600 16.240 ;
        RECT 43.800 15.740 43.900 16.240 ;
        RECT 44.200 15.740 44.300 16.240 ;
        RECT 45.500 15.740 45.600 16.240 ;
        RECT 45.900 15.740 46.000 16.240 ;
        RECT 47.200 15.740 47.300 16.240 ;
        RECT 43.800 14.440 43.900 14.940 ;
        RECT 43.800 4.040 43.900 4.540 ;
        RECT 44.200 4.040 44.300 4.540 ;
        RECT 45.500 4.040 45.600 4.540 ;
        RECT 45.900 4.040 46.000 4.540 ;
        RECT 47.200 4.040 47.300 4.540 ;
        RECT 45.900 6.640 46.000 7.140 ;
        RECT 47.200 6.640 47.300 7.140 ;
        RECT 43.800 6.640 43.900 7.140 ;
        RECT 44.200 6.640 44.300 7.140 ;
        RECT 42.100 0.140 42.200 0.640 ;
        RECT 42.500 0.140 42.600 0.640 ;
        RECT 43.800 0.140 43.900 0.640 ;
        RECT 44.200 0.140 44.300 0.640 ;
        RECT 42.100 5.340 42.200 5.840 ;
        RECT 42.100 1.440 42.200 1.940 ;
        RECT 42.500 1.440 42.600 1.940 ;
        RECT 43.800 1.440 43.900 1.940 ;
        RECT 44.200 1.440 44.300 1.940 ;
        RECT 45.500 1.440 45.600 1.940 ;
        RECT 45.900 1.440 46.000 1.940 ;
        RECT 47.200 1.440 47.300 1.940 ;
        RECT 42.500 5.340 42.600 5.840 ;
        RECT 43.800 5.340 43.900 5.840 ;
        RECT 44.200 5.340 44.300 5.840 ;
        RECT 45.500 5.340 45.600 5.840 ;
        RECT 45.900 5.340 46.000 5.840 ;
        RECT 47.200 5.340 47.300 5.840 ;
        RECT 45.500 0.140 45.600 0.640 ;
        RECT 42.100 7.940 42.200 8.440 ;
        RECT 42.500 7.940 42.600 8.440 ;
        RECT 43.800 7.940 43.900 8.440 ;
        RECT 44.200 7.940 44.300 8.440 ;
        RECT 45.500 7.940 45.600 8.440 ;
        RECT 45.900 7.940 46.000 8.440 ;
        RECT 47.200 7.940 47.300 8.440 ;
        RECT 45.900 0.140 46.000 0.640 ;
        RECT 42.100 2.740 42.200 3.240 ;
        RECT 42.500 2.740 42.600 3.240 ;
        RECT 43.800 2.740 43.900 3.240 ;
        RECT 44.200 2.740 44.300 3.240 ;
        RECT 45.500 2.740 45.600 3.240 ;
        RECT 45.900 2.740 46.000 3.240 ;
        RECT 47.200 2.740 47.300 3.240 ;
        RECT 47.200 0.140 47.300 0.640 ;
        RECT 42.100 9.240 42.200 9.740 ;
        RECT 42.500 9.240 42.600 9.740 ;
        RECT 43.800 9.240 43.900 9.740 ;
        RECT 44.200 9.240 44.300 9.740 ;
        RECT 45.500 9.240 45.600 9.740 ;
        RECT 45.900 9.240 46.000 9.740 ;
        RECT 47.200 9.240 47.300 9.740 ;
        RECT 45.500 6.640 45.600 7.140 ;
        RECT 42.100 4.040 42.200 4.540 ;
        RECT 42.500 4.040 42.600 4.540 ;
        RECT 42.100 6.640 42.200 7.140 ;
        RECT 42.500 6.640 42.600 7.140 ;
        RECT 50.600 5.340 50.700 5.840 ;
        RECT 51.000 5.340 51.100 5.840 ;
        RECT 52.300 5.340 52.400 5.840 ;
        RECT 52.700 5.340 52.800 5.840 ;
        RECT 54.000 5.340 54.100 5.840 ;
        RECT 54.400 5.340 54.500 5.840 ;
        RECT 48.900 0.140 49.000 0.640 ;
        RECT 49.300 0.140 49.400 0.640 ;
        RECT 50.600 0.140 50.700 0.640 ;
        RECT 51.000 0.140 51.100 0.640 ;
        RECT 52.300 0.140 52.400 0.640 ;
        RECT 52.700 0.140 52.800 0.640 ;
        RECT 54.000 0.140 54.100 0.640 ;
        RECT 54.400 0.140 54.500 0.640 ;
        RECT 48.900 7.940 49.000 8.440 ;
        RECT 49.300 7.940 49.400 8.440 ;
        RECT 50.600 7.940 50.700 8.440 ;
        RECT 51.000 7.940 51.100 8.440 ;
        RECT 52.300 7.940 52.400 8.440 ;
        RECT 52.700 7.940 52.800 8.440 ;
        RECT 54.000 7.940 54.100 8.440 ;
        RECT 54.400 7.940 54.500 8.440 ;
        RECT 48.900 1.440 49.000 1.940 ;
        RECT 49.300 1.440 49.400 1.940 ;
        RECT 50.600 1.440 50.700 1.940 ;
        RECT 51.000 1.440 51.100 1.940 ;
        RECT 52.300 1.440 52.400 1.940 ;
        RECT 52.700 1.440 52.800 1.940 ;
        RECT 54.000 1.440 54.100 1.940 ;
        RECT 54.400 1.440 54.500 1.940 ;
        RECT 48.900 6.640 49.000 7.140 ;
        RECT 49.300 6.640 49.400 7.140 ;
        RECT 50.600 6.640 50.700 7.140 ;
        RECT 51.000 6.640 51.100 7.140 ;
        RECT 52.300 6.640 52.400 7.140 ;
        RECT 52.700 6.640 52.800 7.140 ;
        RECT 54.000 6.640 54.100 7.140 ;
        RECT 54.400 6.640 54.500 7.140 ;
        RECT 48.900 2.740 49.000 3.240 ;
        RECT 49.300 2.740 49.400 3.240 ;
        RECT 50.600 2.740 50.700 3.240 ;
        RECT 51.000 2.740 51.100 3.240 ;
        RECT 52.300 2.740 52.400 3.240 ;
        RECT 52.700 2.740 52.800 3.240 ;
        RECT 54.000 2.740 54.100 3.240 ;
        RECT 54.400 2.740 54.500 3.240 ;
        RECT 48.900 4.040 49.000 4.540 ;
        RECT 49.300 4.040 49.400 4.540 ;
        RECT 50.600 4.040 50.700 4.540 ;
        RECT 51.000 4.040 51.100 4.540 ;
        RECT 52.300 4.040 52.400 4.540 ;
        RECT 52.700 4.040 52.800 4.540 ;
        RECT 54.000 4.040 54.100 4.540 ;
        RECT 54.400 4.040 54.500 4.540 ;
        RECT 48.900 9.240 49.000 9.740 ;
        RECT 49.300 9.240 49.400 9.740 ;
        RECT 50.600 9.240 50.700 9.740 ;
        RECT 51.000 9.240 51.100 9.740 ;
        RECT 52.300 9.240 52.400 9.740 ;
        RECT 52.700 9.240 52.800 9.740 ;
        RECT 54.000 9.240 54.100 9.740 ;
        RECT 54.400 9.240 54.500 9.740 ;
        RECT 48.900 5.340 49.000 5.840 ;
        RECT 49.300 5.340 49.400 5.840 ;
  END
END macro_array_pc_64x32_all_pos
END LIBRARY

